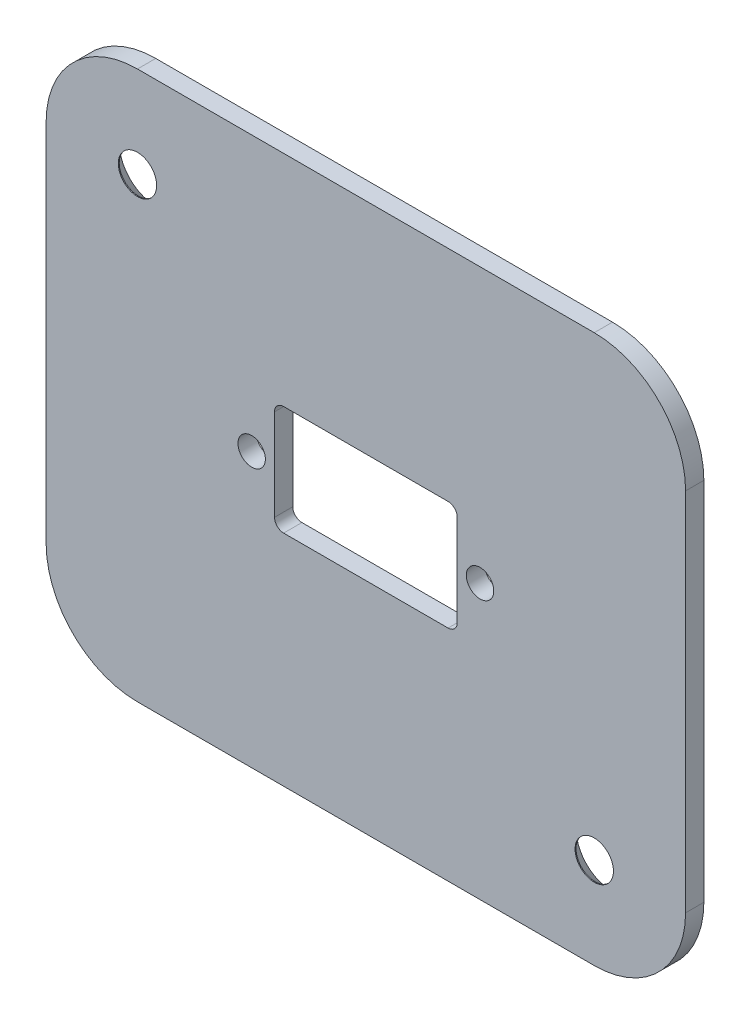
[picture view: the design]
ISO-10303-21;
HEADER;
FILE_DESCRIPTION(('STEP AP214'),'2;1');
FILE_NAME('part.step','',(''),(''),'','','');
FILE_SCHEMA(('AUTOMOTIVE_DESIGN { 1 0 10303 214 1 1 1 1 }'));
ENDSEC;
DATA;
#1=APPLICATION_CONTEXT('core data for automotive mechanical design processes');
#2=APPLICATION_PROTOCOL_DEFINITION('international standard','automotive_design',2000,#1);
#3=PRODUCT_CONTEXT('',#1,'mechanical');
#4=PRODUCT('Part','Part','',(#3));
#5=PRODUCT_RELATED_PRODUCT_CATEGORY('part','',(#4));
#6=PRODUCT_DEFINITION_FORMATION('','',#4);
#7=PRODUCT_DEFINITION_CONTEXT('part definition',#1,'design');
#8=PRODUCT_DEFINITION('design','',#6,#7);
#9=PRODUCT_DEFINITION_SHAPE('','',#8);
#10=(LENGTH_UNIT() NAMED_UNIT(*) SI_UNIT(.MILLI.,.METRE.));
#11=(NAMED_UNIT(*) PLANE_ANGLE_UNIT() SI_UNIT($,.RADIAN.));
#12=(NAMED_UNIT(*) SI_UNIT($,.STERADIAN.) SOLID_ANGLE_UNIT());
#13=UNCERTAINTY_MEASURE_WITH_UNIT(LENGTH_MEASURE(1.E-05),#10,'distance_accuracy_value','');
#14=(GEOMETRIC_REPRESENTATION_CONTEXT(3) GLOBAL_UNCERTAINTY_ASSIGNED_CONTEXT((#13)) GLOBAL_UNIT_ASSIGNED_CONTEXT((#10,
#11,#12)) REPRESENTATION_CONTEXT('',''));
#15=CARTESIAN_POINT('',(0.,0.,0.));
#16=DIRECTION('',(0.,0.,1.));
#17=DIRECTION('',(1.,0.,0.));
#18=AXIS2_PLACEMENT_3D('',#15,#16,#17);
#19=CARTESIAN_POINT('',(0.,0.,-2.));
#20=DIRECTION('',(0.,0.,-1.));
#21=DIRECTION('',(-1.,0.,0.));
#22=AXIS2_PLACEMENT_3D('',#19,#20,#21);
#23=PLANE('',#22);
#24=DIRECTION('',(1.,0.,0.));
#25=VECTOR('',#24,1.);
#26=CARTESIAN_POINT('',(33.2901806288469,15.781993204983,-2.));
#27=LINE('',#26,#25);
#28=CARTESIAN_POINT('',(33.2901806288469,15.781993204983,-2.));
#29=VERTEX_POINT('',#28);
#30=CARTESIAN_POINT('',(33.3350524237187,15.781993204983,-2.));
#31=VERTEX_POINT('',#30);
#32=EDGE_CURVE('E444',#29,#31,#27,.T.);
#33=ORIENTED_EDGE('',*,*,#32,.T.);
#34=DIRECTION('',(0.389639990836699,0.920967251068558,0.));
#35=VECTOR('',#34,1.);
#36=CARTESIAN_POINT('',(33.3350524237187,15.781993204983,-2.));
#37=LINE('',#36,#35);
#38=CARTESIAN_POINT('',(34.8158216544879,19.281993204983,-2.));
#39=VERTEX_POINT('',#38);
#40=EDGE_CURVE('E55',#31,#39,#37,.T.);
#41=ORIENTED_EDGE('',*,*,#40,.T.);
#42=DIRECTION('',(-1.,0.,0.));
#43=VECTOR('',#42,1.);
#44=CARTESIAN_POINT('',(34.8158216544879,19.281993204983,-2.));
#45=LINE('',#44,#43);
#46=CARTESIAN_POINT('',(34.4792831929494,19.281993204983,-2.));
#47=VERTEX_POINT('',#46);
#48=EDGE_CURVE('E434',#39,#47,#45,.T.);
#49=ORIENTED_EDGE('',*,*,#48,.T.);
#50=DIRECTION('',(-0.389563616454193,-0.920999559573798,0.));
#51=VECTOR('',#50,1.);
#52=CARTESIAN_POINT('',(34.4792831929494,19.281993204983,-2.));
#53=LINE('',#52,#51);
#54=CARTESIAN_POINT('',(33.3126165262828,16.5237800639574,-2.));
#55=VERTEX_POINT('',#54);
#56=EDGE_CURVE('E459',#47,#55,#53,.T.);
#57=ORIENTED_EDGE('',*,*,#56,.T.);
#58=DIRECTION('',(-0.389563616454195,0.920999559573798,0.));
#59=VECTOR('',#58,1.);
#60=CARTESIAN_POINT('',(33.3126165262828,16.5237800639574,-2.));
#61=LINE('',#60,#59);
#62=CARTESIAN_POINT('',(32.1459498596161,19.281993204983,-2.));
#63=VERTEX_POINT('',#62);
#64=EDGE_CURVE('E462',#55,#63,#61,.T.);
#65=ORIENTED_EDGE('',*,*,#64,.T.);
#66=DIRECTION('',(-1.,0.,0.));
#67=VECTOR('',#66,1.);
#68=CARTESIAN_POINT('',(32.1459498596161,19.281993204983,-2.));
#69=LINE('',#68,#67);
#70=CARTESIAN_POINT('',(31.8094113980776,19.281993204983,-2.));
#71=VERTEX_POINT('',#70);
#72=EDGE_CURVE('E465',#63,#71,#69,.T.);
#73=ORIENTED_EDGE('',*,*,#72,.T.);
#74=DIRECTION('',(0.389639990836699,-0.920967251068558,0.));
#75=VECTOR('',#74,1.);
#76=CARTESIAN_POINT('',(31.8094113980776,19.281993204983,-2.));
#77=LINE('',#76,#75);
#78=EDGE_CURVE('E468',#71,#29,#77,.T.);
#79=ORIENTED_EDGE('',*,*,#78,.T.);
#80=EDGE_LOOP('',(#33,#41,#49,#57,#65,#73,#79));
#81=FACE_BOUND('',#80,.T.);
#82=DIRECTION('',(-0.200944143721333,0.97960270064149,0.));
#83=VECTOR('',#82,1.);
#84=CARTESIAN_POINT('',(41.1876165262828,17.531993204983,-2.));
#85=LINE('',#84,#83);
#86=CARTESIAN_POINT('',(41.1876165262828,17.531993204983,-2.));
#87=VERTEX_POINT('',#86);
#88=CARTESIAN_POINT('',(40.8286421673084,19.281993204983,-2.));
#89=VERTEX_POINT('',#88);
#90=EDGE_CURVE('E610',#87,#89,#85,.T.);
#91=ORIENTED_EDGE('',*,*,#90,.T.);
#92=DIRECTION('',(-1.,0.,0.));
#93=VECTOR('',#92,1.);
#94=CARTESIAN_POINT('',(40.8286421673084,19.281993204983,-2.));
#95=LINE('',#94,#93);
#96=CARTESIAN_POINT('',(39.392744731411,19.281993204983,-2.));
#97=VERTEX_POINT('',#96);
#98=EDGE_CURVE('E605',#89,#97,#95,.T.);
#99=ORIENTED_EDGE('',*,*,#98,.T.);
#100=DIRECTION('',(0.,-1.,0.));
#101=VECTOR('',#100,1.);
#102=CARTESIAN_POINT('',(39.392744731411,19.281993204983,-2.));
#103=LINE('',#102,#101);
#104=CARTESIAN_POINT('',(39.392744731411,18.9230188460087,-2.));
#105=VERTEX_POINT('',#104);
#106=EDGE_CURVE('E1007',#97,#105,#103,.T.);
#107=ORIENTED_EDGE('',*,*,#106,.T.);
#108=DIRECTION('',(1.,0.,0.));
#109=VECTOR('',#108,1.);
#110=CARTESIAN_POINT('',(39.392744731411,18.9230188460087,-2.));
#111=LINE('',#110,#109);
#112=CARTESIAN_POINT('',(40.5832495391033,18.9230188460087,-2.));
#113=VERTEX_POINT('',#112);
#114=EDGE_CURVE('E1004',#105,#113,#111,.T.);
#115=ORIENTED_EDGE('',*,*,#114,.T.);
#116=DIRECTION('',(0.20070547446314,-0.979651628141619,0.));
#117=VECTOR('',#116,1.);
#118=CARTESIAN_POINT('',(40.5832495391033,18.9230188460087,-2.));
#119=LINE('',#118,#117);
#120=CARTESIAN_POINT('',(40.7718513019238,18.002445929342,-2.));
#121=VERTEX_POINT('',#120);
#122=EDGE_CURVE('E998',#113,#121,#119,.T.);
#123=ORIENTED_EDGE('',*,*,#122,.T.);
#124=CARTESIAN_POINT('',(40.7718513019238,18.002445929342,-2.));
#125=CARTESIAN_POINT('',(40.7347954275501,18.0126762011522,-2.));
#126=CARTESIAN_POINT('',(40.6630055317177,18.0324957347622,-2.));
#127=CARTESIAN_POINT('',(40.557045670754,18.0545015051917,-2.));
#128=CARTESIAN_POINT('',(40.456453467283,18.0677669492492,-2.));
#129=CARTESIAN_POINT('',(40.3911780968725,18.0695782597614,-2.));
#130=CARTESIAN_POINT('',(40.3595916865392,18.0704547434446,-2.));
#131=B_SPLINE_CURVE_WITH_KNOTS('',3,(#124,#125,#126,#127,#128,#129,#130),.UNSPECIFIED.,.F.,.F.,
(4,1,1,1,4),(0.,0.275068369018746,0.532901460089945,0.773973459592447,1.),.UNSPECIFIED.);
#132=CARTESIAN_POINT('',(40.3595916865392,18.0704547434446,-2.));
#133=VERTEX_POINT('',#132);
#134=EDGE_CURVE('E990',#121,#133,#131,.T.);
#135=ORIENTED_EDGE('',*,*,#134,.T.);
#136=CARTESIAN_POINT('',(40.3595916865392,18.0704547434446,-2.));
#137=CARTESIAN_POINT('',(40.320507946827,18.0696088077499,-2.));
#138=CARTESIAN_POINT('',(40.2436595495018,18.0679454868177,-2.));
#139=CARTESIAN_POINT('',(40.1312206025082,18.0519736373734,-2.));
#140=CARTESIAN_POINT('',(40.0238877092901,18.0268337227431,-2.));
#141=CARTESIAN_POINT('',(39.9218853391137,17.9917132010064,-2.));
#142=CARTESIAN_POINT('',(39.8250247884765,17.9468034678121,-2.));
#143=CARTESIAN_POINT('',(39.7341972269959,17.8907035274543,-2.));
#144=CARTESIAN_POINT('',(39.6480393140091,17.8251701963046,-2.));
#145=CARTESIAN_POINT('',(39.5680967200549,17.749825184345,-2.));
#146=CARTESIAN_POINT('',(39.4955724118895,17.6669035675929,-2.));
#147=CARTESIAN_POINT('',(39.4318064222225,17.5777456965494,-2.));
#148=CARTESIAN_POINT('',(39.3776438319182,17.4832180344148,-2.));
#149=CARTESIAN_POINT('',(39.3340830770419,17.3824174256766,-2.));
#150=CARTESIAN_POINT('',(39.2992987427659,17.2764582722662,-2.));
#151=CARTESIAN_POINT('',(39.2761467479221,17.164225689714,-2.));
#152=CARTESIAN_POINT('',(39.2607300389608,17.0467775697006,-2.));
#153=CARTESIAN_POINT('',(39.2590076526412,16.9664729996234,-2.));
#154=CARTESIAN_POINT('',(39.2581293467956,16.9255228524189,-2.));
#155=B_SPLINE_CURVE_WITH_KNOTS('',3,(#136,#137,#138,#139,#140,#141,#142,#143,#144,#145,#146,
#147,#148,#149,#150,#151,#152,#153,#154),.UNSPECIFIED.,.F.,.F.,(4,1,1,1,1,1,1,1,1,1,1,1,1,1,1,1,
4),(0.,0.0658076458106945,0.129394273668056,0.190894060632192,0.251281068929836,
0.310814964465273,0.370370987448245,0.430768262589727,0.492881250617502,0.555103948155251,
0.616067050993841,0.677256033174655,0.738259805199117,0.800762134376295,0.864777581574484,
0.931045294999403,1.),.UNSPECIFIED.);
#156=CARTESIAN_POINT('',(39.2581293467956,16.9255228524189,-2.));
#157=VERTEX_POINT('',#156);
#158=EDGE_CURVE('E982',#133,#157,#155,.T.);
#159=ORIENTED_EDGE('',*,*,#158,.T.);
#160=CARTESIAN_POINT('',(39.2581293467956,16.9255228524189,-2.));
#161=CARTESIAN_POINT('',(39.2587944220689,16.897000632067,-2.));
#162=CARTESIAN_POINT('',(39.2601155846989,16.8403416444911,-2.));
#163=CARTESIAN_POINT('',(39.2668341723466,16.7561974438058,-2.));
#164=CARTESIAN_POINT('',(39.2797698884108,16.6738346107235,-2.));
#165=CARTESIAN_POINT('',(39.2971376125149,16.5932422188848,-2.));
#166=CARTESIAN_POINT('',(39.3196800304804,16.5145728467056,-2.));
#167=CARTESIAN_POINT('',(39.3469690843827,16.4376013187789,-2.));
#168=CARTESIAN_POINT('',(39.3803651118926,16.3628067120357,-2.));
#169=CARTESIAN_POINT('',(39.4169964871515,16.2894813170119,-2.));
#170=CARTESIAN_POINT('',(39.4582429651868,16.2192828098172,-2.));
#171=CARTESIAN_POINT('',(39.5040214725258,16.1536338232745,-2.));
#172=CARTESIAN_POINT('',(39.5523869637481,16.0915495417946,-2.));
#173=CARTESIAN_POINT('',(39.6044283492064,16.0336958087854,-2.));
#174=CARTESIAN_POINT('',(39.660629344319,15.9804527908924,-2.));
#175=CARTESIAN_POINT('',(39.7203093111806,15.9315045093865,-2.));
#176=CARTESIAN_POINT('',(39.7829920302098,15.8860231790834,-2.));
#177=CARTESIAN_POINT('',(39.8496472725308,15.8458549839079,-2.));
#178=CARTESIAN_POINT('',(39.9187897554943,15.8088920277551,-2.));
#179=CARTESIAN_POINT('',(39.9914179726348,15.7785684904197,-2.));
#180=CARTESIAN_POINT('',(40.0658786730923,15.7514579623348,-2.));
#181=CARTESIAN_POINT('',(40.1432435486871,15.7298484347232,-2.));
#182=CARTESIAN_POINT('',(40.2233373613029,15.7129158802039,-2.));
#183=CARTESIAN_POINT('',(40.306292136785,15.7014152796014,-2.));
#184=CARTESIAN_POINT('',(40.3916728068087,15.6930388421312,-2.));
#185=CARTESIAN_POINT('',(40.4495478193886,15.6925144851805,-2.));
#186=CARTESIAN_POINT('',(40.4787823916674,15.6922496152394,-2.));
#187=B_SPLINE_CURVE_WITH_KNOTS('',3,(#160,#161,#162,#163,#164,#165,#166,#167,#168,#169,#170,
#171,#172,#173,#174,#175,#176,#177,#178,#179,#180,#181,#182,#183,#184,#185,#186),.UNSPECIFIED.,
.F.,.F.,(4,1,1,1,1,1,1,1,1,1,1,1,1,1,1,1,1,1,1,1,1,1,1,1,4),(0.,0.0440144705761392,
0.0874341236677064,0.130118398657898,0.172553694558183,0.21455475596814,0.256298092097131,
0.29843822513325,0.340849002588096,0.382715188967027,0.423924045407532,0.464246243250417,
0.504073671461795,0.543861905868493,0.583566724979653,0.623094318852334,0.663229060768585,
0.703551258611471,0.743937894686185,0.784541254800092,0.825750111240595,0.867757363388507,
0.910745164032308,0.954914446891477,1.),.UNSPECIFIED.);
#188=CARTESIAN_POINT('',(40.4787823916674,15.6922496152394,-2.));
#189=VERTEX_POINT('',#188);
#190=EDGE_CURVE('E974',#157,#189,#187,.T.);
#191=ORIENTED_EDGE('',*,*,#190,.T.);
#192=CARTESIAN_POINT('',(40.4787823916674,15.6922496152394,-2.));
#193=CARTESIAN_POINT('',(40.5136565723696,15.6929404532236,-2.));
#194=CARTESIAN_POINT('',(40.5822674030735,15.694299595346,-2.));
#195=CARTESIAN_POINT('',(40.682787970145,15.7085180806,-2.));
#196=CARTESIAN_POINT('',(40.7795025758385,15.7288819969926,-2.));
#197=CARTESIAN_POINT('',(40.8716326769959,15.7595182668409,-2.));
#198=CARTESIAN_POINT('',(40.9600039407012,15.7979055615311,-2.));
#199=CARTESIAN_POINT('',(41.04342665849,15.8464217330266,-2.));
#200=CARTESIAN_POINT('',(41.1240324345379,15.9014008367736,-2.));
#201=CARTESIAN_POINT('',(41.1985444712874,15.9662811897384,-2.));
#202=CARTESIAN_POINT('',(41.267700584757,16.0371968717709,-2.));
#203=CARTESIAN_POINT('',(41.3296070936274,16.1141545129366,-2.));
#204=CARTESIAN_POINT('',(41.384740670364,16.1958839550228,-2.));
#205=CARTESIAN_POINT('',(41.4322184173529,16.2827821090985,-2.));
#206=CARTESIAN_POINT('',(41.4727164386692,16.3746206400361,-2.));
#207=CARTESIAN_POINT('',(41.504531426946,16.4717436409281,-2.));
#208=CARTESIAN_POINT('',(41.5302097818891,16.5736436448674,-2.));
#209=CARTESIAN_POINT('',(41.5410732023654,16.643797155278,-2.));
#210=CARTESIAN_POINT('',(41.5465908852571,16.6794291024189,-2.));
#211=B_SPLINE_CURVE_WITH_KNOTS('',3,(#192,#193,#194,#195,#196,#197,#198,#199,#200,#201,#202,
#203,#204,#205,#206,#207,#208,#209,#210),.UNSPECIFIED.,.F.,.F.,(4,1,1,1,1,1,1,1,1,1,1,1,1,1,1,1,
4),(0.,0.0654211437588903,0.128708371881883,0.190236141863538,0.250724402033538,
0.310637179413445,0.370766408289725,0.431614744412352,0.493522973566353,0.555883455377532,
0.61734236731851,0.678668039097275,0.740711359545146,0.802985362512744,0.866802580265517,
0.932347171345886,1.),.UNSPECIFIED.);
#212=CARTESIAN_POINT('',(41.5465908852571,16.6794291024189,-2.));
#213=VERTEX_POINT('',#212);
#214=EDGE_CURVE('E969',#189,#213,#211,.T.);
#215=ORIENTED_EDGE('',*,*,#214,.T.);
#216=DIRECTION('',(-1.,0.,0.));
#217=VECTOR('',#216,1.);
#218=CARTESIAN_POINT('',(41.5465908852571,16.6794291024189,-2.));
#219=LINE('',#218,#217);
#220=CARTESIAN_POINT('',(41.2324883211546,16.6794291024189,-2.));
#221=VERTEX_POINT('',#220);
#222=EDGE_CURVE('E963',#213,#221,#219,.T.);
#223=ORIENTED_EDGE('',*,*,#222,.T.);
#224=CARTESIAN_POINT('',(41.2324883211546,16.6794291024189,-2.));
#225=CARTESIAN_POINT('',(41.2247597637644,16.6460526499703,-2.));
#226=CARTESIAN_POINT('',(41.2099050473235,16.5819012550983,-2.));
#227=CARTESIAN_POINT('',(41.1772992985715,16.4917699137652,-2.));
#228=CARTESIAN_POINT('',(41.1374334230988,16.4114506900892,-2.));
#229=CARTESIAN_POINT('',(41.0900290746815,16.3398811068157,-2.));
#230=CARTESIAN_POINT('',(41.0334790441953,16.2774721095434,-2.));
#231=CARTESIAN_POINT('',(40.9689496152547,16.2218550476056,-2.));
#232=CARTESIAN_POINT('',(40.8966018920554,16.1716799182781,-2.));
#233=CARTESIAN_POINT('',(40.8162086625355,16.1298571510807,-2.));
#234=CARTESIAN_POINT('',(40.7313955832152,16.0941883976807,-2.));
#235=CARTESIAN_POINT('',(40.6426283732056,16.0704367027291,-2.));
#236=CARTESIAN_POINT('',(40.5523240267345,16.0537358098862,-2.));
#237=CARTESIAN_POINT('',(40.491245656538,16.0520640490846,-2.));
#238=CARTESIAN_POINT('',(40.4605532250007,16.0512239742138,-2.));
#239=B_SPLINE_CURVE_WITH_KNOTS('',3,(#224,#225,#226,#227,#228,#229,#230,#231,#232,#233,#234,
#235,#236,#237,#238),.UNSPECIFIED.,.F.,.F.,(4,1,1,1,1,1,1,1,1,1,1,1,4),(0.,0.0946872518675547,
0.181994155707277,0.264376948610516,0.342179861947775,0.418617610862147,0.496509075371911,
0.577369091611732,0.661510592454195,0.746732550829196,0.831257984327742,0.915205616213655,1.),.UNSPECIFIED.);
#240=CARTESIAN_POINT('',(40.4605532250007,16.0512239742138,-2.));
#241=VERTEX_POINT('',#240);
#242=EDGE_CURVE('E955',#221,#241,#239,.T.);
#243=ORIENTED_EDGE('',*,*,#242,.T.);
#244=CARTESIAN_POINT('',(40.4605532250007,16.0512239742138,-2.));
#245=CARTESIAN_POINT('',(40.4305947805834,16.0520447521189,-2.));
#246=CARTESIAN_POINT('',(40.3716063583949,16.05366087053,-2.));
#247=CARTESIAN_POINT('',(40.2847949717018,16.0660998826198,-2.));
#248=CARTESIAN_POINT('',(40.2009820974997,16.0852574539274,-2.));
#249=CARTESIAN_POINT('',(40.1209947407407,16.1139273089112,-2.));
#250=CARTESIAN_POINT('',(40.0434332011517,16.148772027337,-2.));
#251=CARTESIAN_POINT('',(39.9702594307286,16.1934871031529,-2.));
#252=CARTESIAN_POINT('',(39.8993565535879,16.2449471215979,-2.));
#253=CARTESIAN_POINT('',(39.8329284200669,16.3039037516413,-2.));
#254=CARTESIAN_POINT('',(39.7720889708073,16.3688734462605,-2.));
#255=CARTESIAN_POINT('',(39.7183328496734,16.4383508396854,-2.));
#256=CARTESIAN_POINT('',(39.6735559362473,16.5124676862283,-2.));
#257=CARTESIAN_POINT('',(39.6358218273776,16.5899408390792,-2.));
#258=CARTESIAN_POINT('',(39.6071685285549,16.6716193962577,-2.));
#259=CARTESIAN_POINT('',(39.5867275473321,16.7571205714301,-2.));
#260=CARTESIAN_POINT('',(39.5747244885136,16.8466555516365,-2.));
#261=CARTESIAN_POINT('',(39.5730733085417,16.9077248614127,-2.));
#262=CARTESIAN_POINT('',(39.5722319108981,16.9388441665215,-2.));
#263=B_SPLINE_CURVE_WITH_KNOTS('',3,(#244,#245,#246,#247,#248,#249,#250,#251,#252,#253,#254,
#255,#256,#257,#258,#259,#260,#261,#262),.UNSPECIFIED.,.F.,.F.,(4,1,1,1,1,1,1,1,1,1,1,1,1,1,1,1,
4),(0.,0.0642072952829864,0.12642468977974,0.187680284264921,0.248216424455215,
0.308305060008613,0.369660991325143,0.43169855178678,0.495946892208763,0.559758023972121,
0.622295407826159,0.683910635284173,0.745092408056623,0.806740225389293,0.869086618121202,
0.9332900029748,1.),.UNSPECIFIED.);
#264=CARTESIAN_POINT('',(39.5722319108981,16.9388441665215,-2.));
#265=VERTEX_POINT('',#264);
#266=EDGE_CURVE('E947',#241,#265,#263,.T.);
#267=ORIENTED_EDGE('',*,*,#266,.T.);
#268=CARTESIAN_POINT('',(39.5722319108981,16.9388441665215,-2.));
#269=CARTESIAN_POINT('',(39.5728903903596,16.9669199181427,-2.));
#270=CARTESIAN_POINT('',(39.574179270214,17.0218742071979,-2.));
#271=CARTESIAN_POINT('',(39.5847098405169,17.1022734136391,-2.));
#272=CARTESIAN_POINT('',(39.6030268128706,17.1783464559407,-2.));
#273=CARTESIAN_POINT('',(39.6284506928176,17.2504606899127,-2.));
#274=CARTESIAN_POINT('',(39.6607302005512,17.3186841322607,-2.));
#275=CARTESIAN_POINT('',(39.70017651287,17.3830871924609,-2.));
#276=CARTESIAN_POINT('',(39.7475299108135,17.4428210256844,-2.));
#277=CARTESIAN_POINT('',(39.8016217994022,17.4979135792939,-2.));
#278=CARTESIAN_POINT('',(39.8608798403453,17.548758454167,-2.));
#279=CARTESIAN_POINT('',(39.9263235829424,17.5921025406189,-2.));
#280=CARTESIAN_POINT('',(39.9965835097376,17.6285664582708,-2.));
#281=CARTESIAN_POINT('',(40.0708131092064,17.6600344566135,-2.));
#282=CARTESIAN_POINT('',(40.1507780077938,17.6826352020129,-2.));
#283=CARTESIAN_POINT('',(40.2348946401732,17.699603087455,-2.));
#284=CARTESIAN_POINT('',(40.3240713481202,17.7094184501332,-2.));
#285=CARTESIAN_POINT('',(40.3850420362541,17.710780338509,-2.));
#286=CARTESIAN_POINT('',(40.4163825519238,17.7114803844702,-2.));
#287=B_SPLINE_CURVE_WITH_KNOTS('',3,(#268,#269,#270,#271,#272,#273,#274,#275,#276,#277,#278,
#279,#280,#281,#282,#283,#284,#285,#286),.UNSPECIFIED.,.F.,.F.,(4,1,1,1,1,1,1,1,1,1,1,1,1,1,1,1,
4),(0.,0.0653513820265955,0.127916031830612,0.1883602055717,0.247216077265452,0.305630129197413,
0.36376983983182,0.42266091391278,0.482687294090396,0.543300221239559,0.604117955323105,
0.664964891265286,0.727413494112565,0.791467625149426,0.858055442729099,0.927036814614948,1.),.UNSPECIFIED.);
#288=CARTESIAN_POINT('',(40.4163825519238,17.7114803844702,-2.));
#289=VERTEX_POINT('',#288);
#290=EDGE_CURVE('E939',#265,#289,#287,.T.);
#291=ORIENTED_EDGE('',*,*,#290,.T.);
#292=CARTESIAN_POINT('',(40.4163825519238,17.7114803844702,-2.));
#293=CARTESIAN_POINT('',(40.4435114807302,17.7108997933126,-2.));
#294=CARTESIAN_POINT('',(40.4995258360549,17.7097010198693,-2.));
#295=CARTESIAN_POINT('',(40.5854486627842,17.7008745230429,-2.));
#296=CARTESIAN_POINT('',(40.6757403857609,17.6866352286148,-2.));
#297=CARTESIAN_POINT('',(40.7700548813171,17.6670489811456,-2.));
#298=CARTESIAN_POINT('',(40.8686753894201,17.641417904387,-2.));
#299=CARTESIAN_POINT('',(40.9713937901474,17.6107034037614,-2.));
#300=CARTESIAN_POINT('',(41.0784260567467,17.5739814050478,-2.));
#301=CARTESIAN_POINT('',(41.1505437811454,17.5462491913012,-2.));
#302=CARTESIAN_POINT('',(41.1876165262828,17.531993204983,-2.));
#303=B_SPLINE_CURVE_WITH_KNOTS('',3,(#292,#293,#294,#295,#296,#297,#298,#299,#300,#301,#302),
.UNSPECIFIED.,.F.,.F.,(4,1,1,1,1,1,1,1,4),(0.,0.102203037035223,0.211023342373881,
0.325099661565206,0.446502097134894,0.573787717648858,0.708900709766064,0.850357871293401,1.),.UNSPECIFIED.);
#304=EDGE_CURVE('E934',#289,#87,#303,.T.);
#305=ORIENTED_EDGE('',*,*,#304,.T.);
#306=EDGE_LOOP('',(#91,#99,#107,#115,#123,#135,#159,#191,#215,#223,#243,#267,#291,#305));
#307=FACE_BOUND('',#306,.T.);
#308=CARTESIAN_POINT('',(44.,25.,-2.));
#309=DIRECTION('',(0.,0.,-1.));
#310=DIRECTION('',(-1.,0.,0.));
#311=AXIS2_PLACEMENT_3D('',#308,#309,#310);
#312=CIRCLE('',#311,1.);
#313=CARTESIAN_POINT('',(45.,25.,-2.));
#314=VERTEX_POINT('',#313);
#315=CARTESIAN_POINT('',(44.,24.,-2.));
#316=VERTEX_POINT('',#315);
#317=EDGE_CURVE('E877',#314,#316,#312,.T.);
#318=ORIENTED_EDGE('',*,*,#317,.F.);
#319=DIRECTION('',(0.,-1.,0.));
#320=VECTOR('',#319,1.);
#321=CARTESIAN_POINT('',(45.,35.,-2.));
#322=LINE('',#321,#320);
#323=CARTESIAN_POINT('',(45.,35.,-2.));
#324=VERTEX_POINT('',#323);
#325=EDGE_CURVE('E855',#324,#314,#322,.T.);
#326=ORIENTED_EDGE('',*,*,#325,.F.);
#327=CARTESIAN_POINT('',(44.,35.,-2.));
#328=DIRECTION('',(0.,0.,-1.));
#329=DIRECTION('',(-1.,0.,0.));
#330=AXIS2_PLACEMENT_3D('',#327,#328,#329);
#331=CIRCLE('',#330,1.);
#332=CARTESIAN_POINT('',(44.,36.,-2.));
#333=VERTEX_POINT('',#332);
#334=EDGE_CURVE('E859',#333,#324,#331,.T.);
#335=ORIENTED_EDGE('',*,*,#334,.F.);
#336=DIRECTION('',(1.,0.,0.));
#337=VECTOR('',#336,1.);
#338=CARTESIAN_POINT('',(44.,36.,-2.));
#339=LINE('',#338,#337);
#340=CARTESIAN_POINT('',(26.,36.,-2.));
#341=VERTEX_POINT('',#340);
#342=EDGE_CURVE('E862',#341,#333,#339,.T.);
#343=ORIENTED_EDGE('',*,*,#342,.F.);
#344=CARTESIAN_POINT('',(26.,35.,-2.));
#345=DIRECTION('',(0.,0.,-1.));
#346=DIRECTION('',(-1.,0.,0.));
#347=AXIS2_PLACEMENT_3D('',#344,#345,#346);
#348=CIRCLE('',#347,1.);
#349=CARTESIAN_POINT('',(25.,35.,-2.));
#350=VERTEX_POINT('',#349);
#351=EDGE_CURVE('E865',#350,#341,#348,.T.);
#352=ORIENTED_EDGE('',*,*,#351,.F.);
#353=DIRECTION('',(0.,1.,0.));
#354=VECTOR('',#353,1.);
#355=CARTESIAN_POINT('',(25.,35.,-2.));
#356=LINE('',#355,#354);
#357=CARTESIAN_POINT('',(25.,25.,-2.));
#358=VERTEX_POINT('',#357);
#359=EDGE_CURVE('E868',#358,#350,#356,.T.);
#360=ORIENTED_EDGE('',*,*,#359,.F.);
#361=CARTESIAN_POINT('',(26.,25.,-2.));
#362=DIRECTION('',(0.,0.,-1.));
#363=DIRECTION('',(-1.,0.,0.));
#364=AXIS2_PLACEMENT_3D('',#361,#362,#363);
#365=CIRCLE('',#364,1.);
#366=CARTESIAN_POINT('',(26.,24.,-2.));
#367=VERTEX_POINT('',#366);
#368=EDGE_CURVE('E871',#367,#358,#365,.T.);
#369=ORIENTED_EDGE('',*,*,#368,.F.);
#370=DIRECTION('',(-1.,0.,0.));
#371=VECTOR('',#370,1.);
#372=CARTESIAN_POINT('',(44.,24.,-2.));
#373=LINE('',#372,#371);
#374=EDGE_CURVE('E874',#316,#367,#373,.T.);
#375=ORIENTED_EDGE('',*,*,#374,.F.);
#376=EDGE_LOOP('',(#318,#326,#335,#343,#352,#360,#369,#375));
#377=FACE_BOUND('',#376,.T.);
#378=CARTESIAN_POINT('',(22.5,30.,-2.));
#379=DIRECTION('',(0.,0.,-1.));
#380=DIRECTION('',(-1.,0.,0.));
#381=AXIS2_PLACEMENT_3D('',#378,#379,#380);
#382=CIRCLE('',#381,1.5);
#383=CARTESIAN_POINT('',(21.,30.,-2.));
#384=VERTEX_POINT('',#383);
#385=EDGE_CURVE('E832',#384,#384,#382,.T.);
#386=ORIENTED_EDGE('',*,*,#385,.F.);
#387=EDGE_LOOP('',(#386));
#388=FACE_BOUND('',#387,.T.);
#389=CARTESIAN_POINT('',(47.5,30.,-2.));
#390=DIRECTION('',(0.,0.,-1.));
#391=DIRECTION('',(-1.,0.,0.));
#392=AXIS2_PLACEMENT_3D('',#389,#390,#391);
#393=CIRCLE('',#392,1.5);
#394=CARTESIAN_POINT('',(46.,30.,-2.));
#395=VERTEX_POINT('',#394);
#396=EDGE_CURVE('E826',#395,#395,#393,.T.);
#397=ORIENTED_EDGE('',*,*,#396,.F.);
#398=EDGE_LOOP('',(#397));
#399=FACE_BOUND('',#398,.T.);
#400=CARTESIAN_POINT('',(10.,50.,-2.));
#401=DIRECTION('',(0.,0.,-1.));
#402=DIRECTION('',(-1.,0.,0.));
#403=AXIS2_PLACEMENT_3D('',#400,#401,#402);
#404=CIRCLE('',#403,4.);
#405=CARTESIAN_POINT('',(6.,50.,-2.));
#406=VERTEX_POINT('',#405);
#407=EDGE_CURVE('E752',#406,#406,#404,.F.);
#408=ORIENTED_EDGE('',*,*,#407,.T.);
#409=EDGE_LOOP('',(#408));
#410=FACE_BOUND('',#409,.T.);
#411=CARTESIAN_POINT('',(60.,10.,-2.));
#412=DIRECTION('',(0.,0.,-1.));
#413=DIRECTION('',(-1.,0.,0.));
#414=AXIS2_PLACEMENT_3D('',#411,#412,#413);
#415=CIRCLE('',#414,4.);
#416=CARTESIAN_POINT('',(56.,10.,-2.));
#417=VERTEX_POINT('',#416);
#418=EDGE_CURVE('E754',#417,#417,#415,.F.);
#419=ORIENTED_EDGE('',*,*,#418,.T.);
#420=EDGE_LOOP('',(#419));
#421=FACE_BOUND('',#420,.T.);
#422=DIRECTION('',(0.,1.,0.));
#423=VECTOR('',#422,1.);
#424=CARTESIAN_POINT('',(70.,0.,-2.));
#425=LINE('',#424,#423);
#426=CARTESIAN_POINT('',(70.,10.,-2.));
#427=VERTEX_POINT('',#426);
#428=CARTESIAN_POINT('',(70.,50.,-2.));
#429=VERTEX_POINT('',#428);
#430=EDGE_CURVE('E812',#427,#429,#425,.T.);
#431=ORIENTED_EDGE('',*,*,#430,.F.);
#432=CARTESIAN_POINT('',(60.,10.,-2.));
#433=DIRECTION('',(0.,0.,-1.));
#434=DIRECTION('',(-1.,0.,0.));
#435=AXIS2_PLACEMENT_3D('',#432,#433,#434);
#436=CIRCLE('',#435,10.);
#437=CARTESIAN_POINT('',(60.,0.,-2.));
#438=VERTEX_POINT('',#437);
#439=EDGE_CURVE('E769',#427,#438,#436,.T.);
#440=ORIENTED_EDGE('',*,*,#439,.T.);
#441=DIRECTION('',(1.,0.,0.));
#442=VECTOR('',#441,1.);
#443=CARTESIAN_POINT('',(0.,0.,-2.));
#444=LINE('',#443,#442);
#445=CARTESIAN_POINT('',(10.,0.,-2.));
#446=VERTEX_POINT('',#445);
#447=EDGE_CURVE('E815',#446,#438,#444,.T.);
#448=ORIENTED_EDGE('',*,*,#447,.F.);
#449=CARTESIAN_POINT('',(10.,10.,-2.));
#450=DIRECTION('',(0.,0.,-1.));
#451=DIRECTION('',(-1.,0.,0.));
#452=AXIS2_PLACEMENT_3D('',#449,#450,#451);
#453=CIRCLE('',#452,10.);
#454=CARTESIAN_POINT('',(0.,10.,-2.));
#455=VERTEX_POINT('',#454);
#456=EDGE_CURVE('E771',#446,#455,#453,.T.);
#457=ORIENTED_EDGE('',*,*,#456,.T.);
#458=DIRECTION('',(0.,-1.,0.));
#459=VECTOR('',#458,1.);
#460=CARTESIAN_POINT('',(0.,0.,-2.));
#461=LINE('',#460,#459);
#462=CARTESIAN_POINT('',(0.,50.,-2.));
#463=VERTEX_POINT('',#462);
#464=EDGE_CURVE('E799',#463,#455,#461,.T.);
#465=ORIENTED_EDGE('',*,*,#464,.F.);
#466=CARTESIAN_POINT('',(10.,50.,-2.));
#467=DIRECTION('',(0.,0.,-1.));
#468=DIRECTION('',(-1.,0.,0.));
#469=AXIS2_PLACEMENT_3D('',#466,#467,#468);
#470=CIRCLE('',#469,10.);
#471=CARTESIAN_POINT('',(10.,60.,-2.));
#472=VERTEX_POINT('',#471);
#473=EDGE_CURVE('E773',#463,#472,#470,.T.);
#474=ORIENTED_EDGE('',*,*,#473,.T.);
#475=DIRECTION('',(-1.,0.,0.));
#476=VECTOR('',#475,1.);
#477=CARTESIAN_POINT('',(0.,60.,-2.));
#478=LINE('',#477,#476);
#479=CARTESIAN_POINT('',(60.,60.,-2.));
#480=VERTEX_POINT('',#479);
#481=EDGE_CURVE('E795',#480,#472,#478,.T.);
#482=ORIENTED_EDGE('',*,*,#481,.F.);
#483=CARTESIAN_POINT('',(60.,50.,-2.));
#484=DIRECTION('',(0.,0.,-1.));
#485=DIRECTION('',(-1.,0.,0.));
#486=AXIS2_PLACEMENT_3D('',#483,#484,#485);
#487=CIRCLE('',#486,10.);
#488=EDGE_CURVE('E775',#480,#429,#487,.T.);
#489=ORIENTED_EDGE('',*,*,#488,.T.);
#490=EDGE_LOOP('',(#431,#440,#448,#457,#465,#474,#482,#489));
#491=FACE_BOUND('',#490,.T.);
#492=CARTESIAN_POINT('',(36.6555652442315,18.2962159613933,-2.));
#493=CARTESIAN_POINT('',(36.6567436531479,18.2594721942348,-2.));
#494=CARTESIAN_POINT('',(36.65913376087,18.1849466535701,-2.));
#495=CARTESIAN_POINT('',(36.6758700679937,18.0717163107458,-2.));
#496=CARTESIAN_POINT('',(36.7042902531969,17.9562650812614,-2.));
#497=CARTESIAN_POINT('',(36.736541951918,17.8585434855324,-2.));
#498=CARTESIAN_POINT('',(36.7676741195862,17.7778350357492,-2.));
#499=CARTESIAN_POINT('',(36.7969752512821,17.7140834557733,-2.));
#500=CARTESIAN_POINT('',(36.8294874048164,17.6469821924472,-2.));
#501=CARTESIAN_POINT('',(36.8674061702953,17.5772348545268,-2.));
#502=CARTESIAN_POINT('',(36.9081684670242,17.5039523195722,-2.));
#503=CARTESIAN_POINT('',(36.9542277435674,17.4278696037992,-2.));
#504=CARTESIAN_POINT('',(37.0045333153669,17.3488846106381,-2.));
#505=CARTESIAN_POINT('',(37.0403630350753,17.2956375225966,-2.));
#506=CARTESIAN_POINT('',(37.0587102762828,17.2683714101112,-2.));
#507=B_SPLINE_CURVE_WITH_KNOTS('',3,(#492,#493,#494,#495,#496,#497,#498,#499,#500,#501,#502,
#503,#504,#505,#506),.UNSPECIFIED.,.F.,.F.,(4,1,1,1,1,1,1,1,1,1,1,1,4),(0.,0.0983199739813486,
0.19941747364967,0.305602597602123,0.416162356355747,0.474582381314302,0.537006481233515,
0.603857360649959,0.674089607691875,0.749416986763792,0.828253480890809,0.912054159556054,1.),.UNSPECIFIED.);
#508=CARTESIAN_POINT('',(36.6555652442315,18.2962159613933,-2.));
#509=VERTEX_POINT('',#508);
#510=CARTESIAN_POINT('',(37.0587102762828,17.2683714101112,-2.));
#511=VERTEX_POINT('',#510);
#512=EDGE_CURVE('E576',#509,#511,#507,.T.);
#513=ORIENTED_EDGE('',*,*,#512,.T.);
#514=DIRECTION('',(0.564407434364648,-0.825496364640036,0.));
#515=VECTOR('',#514,1.);
#516=CARTESIAN_POINT('',(37.0587102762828,17.2683714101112,-2.));
#517=LINE('',#516,#515);
#518=CARTESIAN_POINT('',(38.1363344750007,15.6922496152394,-2.));
#519=VERTEX_POINT('',#518);
#520=EDGE_CURVE('E534',#511,#519,#517,.T.);
#521=ORIENTED_EDGE('',*,*,#520,.T.);
#522=DIRECTION('',(0.820951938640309,0.570997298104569,0.));
#523=VECTOR('',#522,1.);
#524=CARTESIAN_POINT('',(38.1363344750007,15.6922496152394,-2.));
#525=LINE('',#524,#523);
#526=CARTESIAN_POINT('',(38.3873360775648,15.8668289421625,-2.));
#527=VERTEX_POINT('',#526);
#528=EDGE_CURVE('E540',#519,#527,#525,.T.);
#529=ORIENTED_EDGE('',*,*,#528,.T.);
#530=DIRECTION('',(-0.564610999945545,0.825357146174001,0.));
#531=VECTOR('',#530,1.);
#532=CARTESIAN_POINT('',(38.3873360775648,15.8668289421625,-2.));
#533=LINE('',#532,#531);
#534=CARTESIAN_POINT('',(37.4141790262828,17.2894050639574,-2.));
#535=VERTEX_POINT('',#534);
#536=EDGE_CURVE('E544',#527,#535,#533,.T.);
#537=ORIENTED_EDGE('',*,*,#536,.T.);
#538=CARTESIAN_POINT('',(37.4141790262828,17.2894050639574,-2.));
#539=CARTESIAN_POINT('',(37.4762697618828,17.2818120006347,-2.));
#540=CARTESIAN_POINT('',(37.5985298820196,17.2668608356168,-2.));
#541=CARTESIAN_POINT('',(37.7216669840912,17.2641141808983,-2.));
#542=CARTESIAN_POINT('',(37.7822679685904,17.2627624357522,-2.));
#543=B_SPLINE_CURVE_WITH_KNOTS('',3,(#538,#539,#540,#541,#542),.UNSPECIFIED.,.F.,.F.,(4,1,4),
(0.,0.50785763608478,1.),.UNSPECIFIED.);
#544=CARTESIAN_POINT('',(37.7822679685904,17.2627624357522,-2.));
#545=VERTEX_POINT('',#544);
#546=EDGE_CURVE('E547',#535,#545,#543,.T.);
#547=ORIENTED_EDGE('',*,*,#546,.T.);
#548=CARTESIAN_POINT('',(37.7822679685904,17.2627624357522,-2.));
#549=CARTESIAN_POINT('',(37.8190100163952,17.2637035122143,-2.));
#550=CARTESIAN_POINT('',(37.8911314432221,17.2655507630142,-2.));
#551=CARTESIAN_POINT('',(37.9971630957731,17.2801925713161,-2.));
#552=CARTESIAN_POINT('',(38.0990486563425,17.3027426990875,-2.));
#553=CARTESIAN_POINT('',(38.1965180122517,17.3363914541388,-2.));
#554=CARTESIAN_POINT('',(38.2899375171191,17.3782096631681,-2.));
#555=CARTESIAN_POINT('',(38.3791032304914,17.4300666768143,-2.));
#556=CARTESIAN_POINT('',(38.4638951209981,17.4910729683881,-2.));
#557=CARTESIAN_POINT('',(38.5434025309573,17.5609059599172,-2.));
#558=CARTESIAN_POINT('',(38.6157142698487,17.6375840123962,-2.));
#559=CARTESIAN_POINT('',(38.6801375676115,17.7187396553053,-2.));
#560=CARTESIAN_POINT('',(38.7336786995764,17.8053156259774,-2.));
#561=CARTESIAN_POINT('',(38.7781552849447,17.8955458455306,-2.));
#562=CARTESIAN_POINT('',(38.8118857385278,17.9907271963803,-2.));
#563=CARTESIAN_POINT('',(38.8364482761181,18.089776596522,-2.));
#564=CARTESIAN_POINT('',(38.8515706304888,18.1933882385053,-2.));
#565=CARTESIAN_POINT('',(38.8533697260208,18.2639133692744,-2.));
#566=CARTESIAN_POINT('',(38.8542831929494,18.2997215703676,-2.));
#567=B_SPLINE_CURVE_WITH_KNOTS('',3,(#548,#549,#550,#551,#552,#553,#554,#555,#556,#557,#558,
#559,#560,#561,#562,#563,#564,#565,#566),.UNSPECIFIED.,.F.,.F.,(4,1,1,1,1,1,1,1,1,1,1,1,1,1,1,1,
4),(0.,0.066294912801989,0.130131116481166,0.192862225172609,0.254360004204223,
0.315909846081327,0.377338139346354,0.44020526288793,0.504175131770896,0.56803363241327,
0.63022772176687,0.690861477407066,0.751421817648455,0.811465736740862,0.872750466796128,
0.935390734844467,1.),.UNSPECIFIED.);
#568=CARTESIAN_POINT('',(38.8542831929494,18.2997215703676,-2.));
#569=VERTEX_POINT('',#568);
#570=EDGE_CURVE('E552',#545,#569,#567,.T.);
#571=ORIENTED_EDGE('',*,*,#570,.T.);
#572=CARTESIAN_POINT('',(38.8542831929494,18.2997215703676,-2.));
#573=CARTESIAN_POINT('',(38.8525487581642,18.3486902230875,-2.));
#574=CARTESIAN_POINT('',(38.8491444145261,18.4448057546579,-2.));
#575=CARTESIAN_POINT('',(38.8217458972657,18.5852395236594,-2.));
#576=CARTESIAN_POINT('',(38.7766855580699,18.7180260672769,-2.));
#577=CARTESIAN_POINT('',(38.7138571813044,18.8428162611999,-2.));
#578=CARTESIAN_POINT('',(38.6347224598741,18.9578150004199,-2.));
#579=CARTESIAN_POINT('',(38.5396138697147,19.0614236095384,-2.));
#580=CARTESIAN_POINT('',(38.4291099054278,19.1521684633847,-2.));
#581=CARTESIAN_POINT('',(38.305727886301,19.2301725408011,-2.));
#582=CARTESIAN_POINT('',(38.1723748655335,19.2929075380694,-2.));
#583=CARTESIAN_POINT('',(38.0327062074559,19.3391468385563,-2.));
#584=CARTESIAN_POINT('',(37.8877920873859,19.3663455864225,-2.));
#585=CARTESIAN_POINT('',(37.7896244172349,19.3699314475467,-2.));
#586=CARTESIAN_POINT('',(37.7402006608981,19.3717367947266,-2.));
#587=B_SPLINE_CURVE_WITH_KNOTS('',3,(#572,#573,#574,#575,#576,#577,#578,#579,#580,#581,#582,
#583,#584,#585,#586),.UNSPECIFIED.,.F.,.F.,(4,1,1,1,1,1,1,1,1,1,1,1,4),(0.,0.0852490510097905,
0.167326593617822,0.248175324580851,0.328829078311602,0.409908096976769,0.490584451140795,
0.57299348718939,0.658264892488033,0.744221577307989,0.829060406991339,0.913938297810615,1.),.UNSPECIFIED.);
#588=CARTESIAN_POINT('',(37.7402006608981,19.3717367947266,-2.));
#589=VERTEX_POINT('',#588);
#590=EDGE_CURVE('E560',#569,#589,#587,.T.);
#591=ORIENTED_EDGE('',*,*,#590,.T.);
#592=CARTESIAN_POINT('',(37.7402006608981,19.3717367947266,-2.));
#593=CARTESIAN_POINT('',(37.691712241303,19.3699066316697,-2.));
#594=CARTESIAN_POINT('',(37.5959036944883,19.3662904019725,-2.));
#595=CARTESIAN_POINT('',(37.4550146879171,19.3398064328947,-2.));
#596=CARTESIAN_POINT('',(37.3200736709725,19.2951697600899,-2.));
#597=CARTESIAN_POINT('',(37.1918286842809,19.2334851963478,-2.));
#598=CARTESIAN_POINT('',(37.0730892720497,19.1561642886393,-2.));
#599=CARTESIAN_POINT('',(36.9663134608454,19.0640297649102,-2.));
#600=CARTESIAN_POINT('',(36.8739379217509,18.9570242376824,-2.));
#601=CARTESIAN_POINT('',(36.7961140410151,18.8377357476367,-2.));
#602=CARTESIAN_POINT('',(36.7336440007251,18.7095687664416,-2.));
#603=CARTESIAN_POINT('',(36.6885717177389,18.5757848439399,-2.));
#604=CARTESIAN_POINT('',(36.6608260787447,18.437346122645,-2.));
#605=CARTESIAN_POINT('',(36.6573297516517,18.3435516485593,-2.));
#606=CARTESIAN_POINT('',(36.6555652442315,18.2962159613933,-2.));
#607=B_SPLINE_CURVE_WITH_KNOTS('',3,(#592,#593,#594,#595,#596,#597,#598,#599,#600,#601,#602,
#603,#604,#605,#606),.UNSPECIFIED.,.F.,.F.,(4,1,1,1,1,1,1,1,1,1,1,1,4),(0.,0.0855321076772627,
0.169003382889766,0.25194324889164,0.335682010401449,0.419408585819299,0.501264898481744,
0.583702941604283,0.668000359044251,0.751918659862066,0.834597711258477,0.916525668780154,1.),.UNSPECIFIED.);
#608=EDGE_CURVE('E568',#589,#509,#607,.T.);
#609=ORIENTED_EDGE('',*,*,#608,.T.);
#610=EDGE_LOOP('',(#513,#521,#529,#537,#547,#571,#591,#609));
#611=FACE_BOUND('',#610,.T.);
#612=CARTESIAN_POINT('',(31.3606934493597,17.5523257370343,-2.));
#613=CARTESIAN_POINT('',(31.3591382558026,17.6152811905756,-2.));
#614=CARTESIAN_POINT('',(31.3560785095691,17.7391421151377,-2.));
#615=CARTESIAN_POINT('',(31.3300827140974,17.9209160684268,-2.));
#616=CARTESIAN_POINT('',(31.2882639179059,18.0950674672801,-2.));
#617=CARTESIAN_POINT('',(31.2288670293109,18.261271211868,-2.));
#618=CARTESIAN_POINT('',(31.1535616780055,18.4204014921,-2.));
#619=CARTESIAN_POINT('',(31.060535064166,18.5712426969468,-2.));
#620=CARTESIAN_POINT('',(30.9508679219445,18.7147594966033,-2.));
#621=CARTESIAN_POINT('',(30.8254203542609,18.8487742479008,-2.));
#622=CARTESIAN_POINT('',(30.6878530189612,18.9713136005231,-2.));
#623=CARTESIAN_POINT('',(30.5405342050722,19.0791198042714,-2.));
#624=CARTESIAN_POINT('',(30.3837522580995,19.1688373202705,-2.));
#625=CARTESIAN_POINT('',(30.219234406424,19.2438334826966,-2.));
#626=CARTESIAN_POINT('',(30.0457487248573,19.3014779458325,-2.));
#627=CARTESIAN_POINT('',(29.8636653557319,19.3418311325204,-2.));
#628=CARTESIAN_POINT('',(29.6733264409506,19.3669482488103,-2.));
#629=CARTESIAN_POINT('',(29.5434640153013,19.3701234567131,-2.));
#630=CARTESIAN_POINT('',(29.477480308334,19.3717367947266,-2.));
#631=B_SPLINE_CURVE_WITH_KNOTS('',3,(#612,#613,#614,#615,#616,#617,#618,#619,#620,#621,#622,
#623,#624,#625,#626,#627,#628,#629,#630),.UNSPECIFIED.,.F.,.F.,(4,1,1,1,1,1,1,1,1,1,1,1,1,1,1,1,
4),(0.,0.0645578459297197,0.127013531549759,0.18795481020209,0.248013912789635,
0.307747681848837,0.368234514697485,0.42946984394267,0.492743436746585,0.556257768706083,
0.618216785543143,0.679655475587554,0.74124554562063,0.803415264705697,0.866815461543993,
0.932328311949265,1.),.UNSPECIFIED.);
#632=CARTESIAN_POINT('',(31.3606934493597,17.5523257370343,-2.));
#633=VERTEX_POINT('',#632);
#634=CARTESIAN_POINT('',(29.477480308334,19.3717367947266,-2.));
#635=VERTEX_POINT('',#634);
#636=EDGE_CURVE('E427',#633,#635,#631,.T.);
#637=ORIENTED_EDGE('',*,*,#636,.T.);
#638=CARTESIAN_POINT('',(29.477480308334,19.3717367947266,-2.));
#639=CARTESIAN_POINT('',(29.4372658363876,19.3712546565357,-2.));
#640=CARTESIAN_POINT('',(29.3576653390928,19.3703003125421,-2.));
#641=CARTESIAN_POINT('',(29.2399126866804,19.3609941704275,-2.));
#642=CARTESIAN_POINT('',(29.1252703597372,19.3454805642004,-2.));
#643=CARTESIAN_POINT('',(29.0136593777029,19.3243644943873,-2.));
#644=CARTESIAN_POINT('',(28.9045367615,19.2981571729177,-2.));
#645=CARTESIAN_POINT('',(28.7987365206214,19.2640168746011,-2.));
#646=CARTESIAN_POINT('',(28.6956378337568,19.2249803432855,-2.));
#647=CARTESIAN_POINT('',(28.5958909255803,19.1800218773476,-2.));
#648=CARTESIAN_POINT('',(28.49997437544,19.1295551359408,-2.));
#649=CARTESIAN_POINT('',(28.4079180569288,19.0741395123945,-2.));
#650=CARTESIAN_POINT('',(28.3204531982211,19.01384370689,-2.));
#651=CARTESIAN_POINT('',(28.2369643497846,18.9491805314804,-2.));
#652=CARTESIAN_POINT('',(28.1588481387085,18.878781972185,-2.));
#653=CARTESIAN_POINT('',(28.0838866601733,18.8045843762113,-2.));
#654=CARTESIAN_POINT('',(28.0146255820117,18.724450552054,-2.));
#655=CARTESIAN_POINT('',(27.9718723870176,18.668045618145,-2.));
#656=CARTESIAN_POINT('',(27.9504370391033,18.6397656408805,-2.));
#657=B_SPLINE_CURVE_WITH_KNOTS('',3,(#638,#639,#640,#641,#642,#643,#644,#645,#646,#647,#648,
#649,#650,#651,#652,#653,#654,#655,#656),.UNSPECIFIED.,.F.,.F.,(4,1,1,1,1,1,1,1,1,1,1,1,1,1,1,1,
4),(0.,0.0685475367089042,0.135682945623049,0.20121498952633,0.265682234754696,
0.329266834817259,0.392395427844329,0.455069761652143,0.517126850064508,0.578790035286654,
0.639739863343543,0.700191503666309,0.759806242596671,0.819628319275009,0.879354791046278,
0.939511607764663,1.),.UNSPECIFIED.);
#658=CARTESIAN_POINT('',(27.9504370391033,18.6397656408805,-2.));
#659=VERTEX_POINT('',#658);
#660=EDGE_CURVE('E47',#635,#659,#657,.T.);
#661=ORIENTED_EDGE('',*,*,#660,.T.);
#662=DIRECTION('',(0.794127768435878,-0.607750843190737,0.));
#663=VECTOR('',#662,1.);
#664=CARTESIAN_POINT('',(27.9504370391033,18.6397656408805,-2.));
#665=LINE('',#664,#663);
#666=CARTESIAN_POINT('',(28.225276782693,18.4294291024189,-2.));
#667=VERTEX_POINT('',#666);
#668=EDGE_CURVE('E431',#659,#667,#665,.T.);
#669=ORIENTED_EDGE('',*,*,#668,.T.);
#670=CARTESIAN_POINT('',(28.225276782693,18.4294291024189,-2.));
#671=CARTESIAN_POINT('',(28.2448826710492,18.45279507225,-2.));
#672=CARTESIAN_POINT('',(28.2838301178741,18.4992119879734,-2.));
#673=CARTESIAN_POINT('',(28.346489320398,18.5643915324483,-2.));
#674=CARTESIAN_POINT('',(28.4117909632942,18.625456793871,-2.));
#675=CARTESIAN_POINT('',(28.4797100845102,18.6826986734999,-2.));
#676=CARTESIAN_POINT('',(28.5514692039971,18.7341154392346,-2.));
#677=CARTESIAN_POINT('',(28.6253300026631,18.7823865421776,-2.));
#678=CARTESIAN_POINT('',(28.7025280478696,18.8256542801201,-2.));
#679=CARTESIAN_POINT('',(28.8092797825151,18.878117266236,-2.));
#680=CARTESIAN_POINT('',(28.9489276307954,18.9328634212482,-2.));
#681=CARTESIAN_POINT('',(29.1247224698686,18.9787666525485,-2.));
#682=CARTESIAN_POINT('',(29.3082335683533,19.0079878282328,-2.));
#683=CARTESIAN_POINT('',(29.4334311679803,19.0111526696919,-2.));
#684=CARTESIAN_POINT('',(29.4971117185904,19.0127624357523,-2.));
#685=B_SPLINE_CURVE_WITH_KNOTS('',3,(#670,#671,#672,#673,#674,#675,#676,#677,#678,#679,#680,
#681,#682,#683,#684),.UNSPECIFIED.,.F.,.F.,(4,1,1,1,1,1,1,1,1,1,1,1,4),(0.,0.0631632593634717,
0.125474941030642,0.187121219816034,0.248294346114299,0.309294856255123,0.369850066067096,
0.430973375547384,0.492455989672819,0.616147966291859,0.740843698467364,0.868182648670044,1.),.UNSPECIFIED.);
#686=CARTESIAN_POINT('',(29.4971117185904,19.0127624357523,-2.));
#687=VERTEX_POINT('',#686);
#688=EDGE_CURVE('E1483',#667,#687,#685,.T.);
#689=ORIENTED_EDGE('',*,*,#688,.T.);
#690=CARTESIAN_POINT('',(29.4971117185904,19.0127624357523,-2.));
#691=CARTESIAN_POINT('',(29.5321950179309,19.0123584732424,-2.));
#692=CARTESIAN_POINT('',(29.6020360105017,19.0115542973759,-2.));
#693=CARTESIAN_POINT('',(29.7056844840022,19.0009451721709,-2.));
#694=CARTESIAN_POINT('',(29.8073975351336,18.9860339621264,-2.));
#695=CARTESIAN_POINT('',(29.9071090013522,18.9639086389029,-2.));
#696=CARTESIAN_POINT('',(30.0046919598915,18.9359360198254,-2.));
#697=CARTESIAN_POINT('',(30.1007843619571,18.9025106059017,-2.));
#698=CARTESIAN_POINT('',(30.1939949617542,18.8611557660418,-2.));
#699=CARTESIAN_POINT('',(30.2856131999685,18.8154475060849,-2.));
#700=CARTESIAN_POINT('',(30.3733924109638,18.7638200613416,-2.));
#701=CARTESIAN_POINT('',(30.4564474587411,18.70750670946,-2.));
#702=CARTESIAN_POINT('',(30.5344754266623,18.6471376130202,-2.));
#703=CARTESIAN_POINT('',(30.6075380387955,18.5824865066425,-2.));
#704=CARTESIAN_POINT('',(30.6757099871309,18.5138445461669,-2.));
#705=CARTESIAN_POINT('',(30.7384972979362,18.4404802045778,-2.));
#706=CARTESIAN_POINT('',(30.7956827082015,18.3626280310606,-2.));
#707=CARTESIAN_POINT('',(30.8483997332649,18.2813146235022,-2.));
#708=CARTESIAN_POINT('',(30.8956124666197,18.1967768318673,-2.));
#709=CARTESIAN_POINT('',(30.9351423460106,18.1087017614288,-2.));
#710=CARTESIAN_POINT('',(30.9701474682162,18.0185976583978,-2.));
#711=CARTESIAN_POINT('',(30.9978467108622,17.9254464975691,-2.));
#712=CARTESIAN_POINT('',(31.0197712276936,17.8299037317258,-2.));
#713=CARTESIAN_POINT('',(31.0348988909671,17.7317129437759,-2.));
#714=CARTESIAN_POINT('',(31.0453873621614,17.6310792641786,-2.));
#715=CARTESIAN_POINT('',(31.0461875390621,17.5628699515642,-2.));
#716=CARTESIAN_POINT('',(31.0465908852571,17.5284875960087,-2.));
#717=B_SPLINE_CURVE_WITH_KNOTS('',3,(#690,#691,#692,#693,#694,#695,#696,#697,#698,#699,#700,
#701,#702,#703,#704,#705,#706,#707,#708,#709,#710,#711,#712,#713,#714,#715,#716),.UNSPECIFIED.,
.F.,.F.,(4,1,1,1,1,1,1,1,1,1,1,1,1,1,1,1,1,1,1,1,1,1,1,1,4),(0.,0.0439549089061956,
0.0875018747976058,0.130462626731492,0.172752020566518,0.215403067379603,0.25764982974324,
0.300152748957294,0.343121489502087,0.385925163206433,0.427685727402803,0.46881795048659,
0.509491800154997,0.54988303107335,0.589980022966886,0.630405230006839,0.670868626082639,
0.711383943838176,0.751627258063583,0.791775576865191,0.832458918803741,0.873319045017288,
0.914542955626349,0.956923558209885,1.),.UNSPECIFIED.);
#718=CARTESIAN_POINT('',(31.0465908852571,17.5284875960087,-2.));
#719=VERTEX_POINT('',#718);
#720=EDGE_CURVE('E1427',#687,#719,#717,.T.);
#721=ORIENTED_EDGE('',*,*,#720,.T.);
#722=CARTESIAN_POINT('',(31.0465908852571,17.5284875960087,-2.));
#723=CARTESIAN_POINT('',(31.0453290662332,17.4767562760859,-2.));
#724=CARTESIAN_POINT('',(31.0428516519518,17.3751886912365,-2.));
#725=CARTESIAN_POINT('',(31.0208033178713,17.2264180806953,-2.));
#726=CARTESIAN_POINT('',(30.9872982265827,17.083897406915,-2.));
#727=CARTESIAN_POINT('',(30.937082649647,16.9485175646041,-2.));
#728=CARTESIAN_POINT('',(30.8751635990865,16.8186092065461,-2.));
#729=CARTESIAN_POINT('',(30.7969229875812,16.6963703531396,-2.));
#730=CARTESIAN_POINT('',(30.706306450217,16.5799537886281,-2.));
#731=CARTESIAN_POINT('',(30.6020320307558,16.4721108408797,-2.));
#732=CARTESIAN_POINT('',(30.4876262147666,16.3735971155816,-2.));
#733=CARTESIAN_POINT('',(30.3648783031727,16.2868465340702,-2.));
#734=CARTESIAN_POINT('',(30.2340940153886,16.2145316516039,-2.));
#735=CARTESIAN_POINT('',(30.096717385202,16.1543557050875,-2.));
#736=CARTESIAN_POINT('',(29.9516912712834,16.108098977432,-2.));
#737=CARTESIAN_POINT('',(29.7992764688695,16.0755348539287,-2.));
#738=CARTESIAN_POINT('',(29.6398044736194,16.0542926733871,-2.));
#739=CARTESIAN_POINT('',(29.5308350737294,16.052258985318,-2.));
#740=CARTESIAN_POINT('',(29.4753769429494,16.0512239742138,-2.));
#741=B_SPLINE_CURVE_WITH_KNOTS('',3,(#722,#723,#724,#725,#726,#727,#728,#729,#730,#731,#732,
#733,#734,#735,#736,#737,#738,#739,#740),.UNSPECIFIED.,.F.,.F.,(4,1,1,1,1,1,1,1,1,1,1,1,1,1,1,1,
4),(0.,0.0643232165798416,0.126290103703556,0.186726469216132,0.246146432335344,
0.305575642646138,0.365429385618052,0.42632630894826,0.488839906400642,0.551724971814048,
0.613918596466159,0.675483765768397,0.737333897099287,0.800229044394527,0.864502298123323,
0.931040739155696,1.),.UNSPECIFIED.);
#742=CARTESIAN_POINT('',(29.4753769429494,16.0512239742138,-2.));
#743=VERTEX_POINT('',#742);
#744=EDGE_CURVE('E1424',#719,#743,#741,.T.);
#745=ORIENTED_EDGE('',*,*,#744,.T.);
#746=CARTESIAN_POINT('',(29.4753769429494,16.0512239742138,-2.));
#747=CARTESIAN_POINT('',(29.4142742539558,16.0529127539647,-2.));
#748=CARTESIAN_POINT('',(29.2940095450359,16.0562366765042,-2.));
#749=CARTESIAN_POINT('',(29.1176415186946,16.0843959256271,-2.));
#750=CARTESIAN_POINT('',(28.9488057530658,16.1300538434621,-2.));
#751=CARTESIAN_POINT('',(28.7874931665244,16.1939517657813,-2.));
#752=CARTESIAN_POINT('',(28.6341585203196,16.277017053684,-2.));
#753=CARTESIAN_POINT('',(28.4885618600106,16.3777149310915,-2.));
#754=CARTESIAN_POINT('',(28.3505802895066,16.4970032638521,-2.));
#755=CARTESIAN_POINT('',(28.2676090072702,16.5880863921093,-2.));
#756=CARTESIAN_POINT('',(28.225276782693,16.6345573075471,-2.));
#757=B_SPLINE_CURVE_WITH_KNOTS('',3,(#746,#747,#748,#749,#750,#751,#752,#753,#754,#755,#756),
.UNSPECIFIED.,.F.,.F.,(4,1,1,1,1,1,1,1,4),(0.,0.128515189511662,0.252948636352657,
0.374754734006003,0.495939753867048,0.617180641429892,0.740909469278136,0.867811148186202,1.),.UNSPECIFIED.);
#758=CARTESIAN_POINT('',(28.225276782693,16.6345573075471,-2.));
#759=VERTEX_POINT('',#758);
#760=EDGE_CURVE('E1417',#743,#759,#757,.T.);
#761=ORIENTED_EDGE('',*,*,#760,.T.);
#762=DIRECTION('',(-0.797062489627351,-0.603896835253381,0.));
#763=VECTOR('',#762,1.);
#764=CARTESIAN_POINT('',(28.225276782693,16.6345573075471,-2.));
#765=LINE('',#764,#763);
#766=CARTESIAN_POINT('',(27.9504370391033,16.4263241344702,-2.));
#767=VERTEX_POINT('',#766);
#768=EDGE_CURVE('E1408',#759,#767,#765,.T.);
#769=ORIENTED_EDGE('',*,*,#768,.T.);
#770=CARTESIAN_POINT('',(27.9504370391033,16.4263241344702,-2.));
#771=CARTESIAN_POINT('',(27.9725551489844,16.3977856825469,-2.));
#772=CARTESIAN_POINT('',(28.0166854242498,16.3408454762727,-2.));
#773=CARTESIAN_POINT('',(28.0881434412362,16.2605737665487,-2.));
#774=CARTESIAN_POINT('',(28.1634207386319,16.1850697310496,-2.));
#775=CARTESIAN_POINT('',(28.2430764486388,16.1149421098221,-2.));
#776=CARTESIAN_POINT('',(28.3261942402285,16.0487876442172,-2.));
#777=CARTESIAN_POINT('',(28.4142665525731,15.9884858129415,-2.));
#778=CARTESIAN_POINT('',(28.5061355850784,15.9331949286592,-2.));
#779=CARTESIAN_POINT('',(28.601490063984,15.8825680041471,-2.));
#780=CARTESIAN_POINT('',(28.7002286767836,15.8376507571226,-2.));
#781=CARTESIAN_POINT('',(28.8022331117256,15.7991969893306,-2.));
#782=CARTESIAN_POINT('',(28.9070636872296,15.766072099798,-2.));
#783=CARTESIAN_POINT('',(29.0147251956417,15.7388201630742,-2.));
#784=CARTESIAN_POINT('',(29.1254409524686,15.7175490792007,-2.));
#785=CARTESIAN_POINT('',(29.2388114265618,15.7033294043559,-2.));
#786=CARTESIAN_POINT('',(29.3550813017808,15.6935874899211,-2.));
#787=CARTESIAN_POINT('',(29.4335227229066,15.6926995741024,-2.));
#788=CARTESIAN_POINT('',(29.4732735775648,15.6922496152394,-2.));
#789=B_SPLINE_CURVE_WITH_KNOTS('',3,(#770,#771,#772,#773,#774,#775,#776,#777,#778,#779,#780,
#781,#782,#783,#784,#785,#786,#787,#788),.UNSPECIFIED.,.F.,.F.,(4,1,1,1,1,1,1,1,1,1,1,1,1,1,1,1,
4),(0.,0.061674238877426,0.123053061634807,0.183475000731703,0.243726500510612,
0.304278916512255,0.364862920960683,0.42594620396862,0.487391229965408,0.549220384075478,
0.611143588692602,0.673528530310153,0.736961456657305,0.80078528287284,0.866012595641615,
0.932100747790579,1.),.UNSPECIFIED.);
#790=CARTESIAN_POINT('',(29.4732735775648,15.6922496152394,-2.));
#791=VERTEX_POINT('',#790);
#792=EDGE_CURVE('E1416',#767,#791,#789,.T.);
#793=ORIENTED_EDGE('',*,*,#792,.T.);
#794=CARTESIAN_POINT('',(29.4732735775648,15.6922496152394,-2.));
#795=CARTESIAN_POINT('',(29.5109172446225,15.6925116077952,-2.));
#796=CARTESIAN_POINT('',(29.5853529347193,15.6930296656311,-2.));
#797=CARTESIAN_POINT('',(29.6952516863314,15.7014218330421,-2.));
#798=CARTESIAN_POINT('',(29.802241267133,15.712871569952,-2.));
#799=CARTESIAN_POINT('',(29.9060158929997,15.730111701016,-2.));
#800=CARTESIAN_POINT('',(30.0071418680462,15.7504560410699,-2.));
#801=CARTESIAN_POINT('',(30.104702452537,15.7777272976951,-2.));
#802=CARTESIAN_POINT('',(30.1996576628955,15.8082764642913,-2.));
#803=CARTESIAN_POINT('',(30.2916260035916,15.844181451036,-2.));
#804=CARTESIAN_POINT('',(30.3806857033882,15.8846976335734,-2.));
#805=CARTESIAN_POINT('',(30.4665495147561,15.9304891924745,-2.));
#806=CARTESIAN_POINT('',(30.5491779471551,15.9811710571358,-2.));
#807=CARTESIAN_POINT('',(30.6293833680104,16.0356260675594,-2.));
#808=CARTESIAN_POINT('',(30.7059809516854,16.0956033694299,-2.));
#809=CARTESIAN_POINT('',(30.7796344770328,16.1602700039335,-2.));
#810=CARTESIAN_POINT('',(30.8507569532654,16.2294080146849,-2.));
#811=CARTESIAN_POINT('',(30.8947596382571,16.2792628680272,-2.));
#812=CARTESIAN_POINT('',(30.9168833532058,16.3043289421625,-2.));
#813=B_SPLINE_CURVE_WITH_KNOTS('',3,(#794,#795,#796,#797,#798,#799,#800,#801,#802,#803,#804,
#805,#806,#807,#808,#809,#810,#811,#812),.UNSPECIFIED.,.F.,.F.,(4,1,1,1,1,1,1,1,1,1,1,1,1,1,1,1,
4),(0.,0.0696628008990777,0.137749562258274,0.203916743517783,0.268779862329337,
0.332413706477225,0.394753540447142,0.45618003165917,0.516995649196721,0.577395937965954,
0.637198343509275,0.696999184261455,0.75675619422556,0.816553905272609,0.876947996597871,
0.938131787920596,1.),.UNSPECIFIED.);
#814=CARTESIAN_POINT('',(30.9168833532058,16.3043289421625,-2.));
#815=VERTEX_POINT('',#814);
#816=EDGE_CURVE('E1441',#791,#815,#813,.T.);
#817=ORIENTED_EDGE('',*,*,#816,.T.);
#818=CARTESIAN_POINT('',(30.9168833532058,16.3043289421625,-2.));
#819=CARTESIAN_POINT('',(30.9523189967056,16.3478701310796,-2.));
#820=CARTESIAN_POINT('',(31.0227624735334,16.4344268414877,-2.));
#821=CARTESIAN_POINT('',(31.1128881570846,16.5747128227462,-2.));
#822=CARTESIAN_POINT('',(31.1900357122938,16.721181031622,-2.));
#823=CARTESIAN_POINT('',(31.252411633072,16.8746009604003,-2.));
#824=CARTESIAN_POINT('',(31.3011743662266,17.0346283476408,-2.));
#825=CARTESIAN_POINT('',(31.3349555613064,17.2013438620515,-2.));
#826=CARTESIAN_POINT('',(31.3569071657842,17.3745918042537,-2.));
#827=CARTESIAN_POINT('',(31.3594174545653,17.4924285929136,-2.));
#828=CARTESIAN_POINT('',(31.3606934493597,17.5523257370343,-2.));
#829=B_SPLINE_CURVE_WITH_KNOTS('',3,(#818,#819,#820,#821,#822,#823,#824,#825,#826,#827,#828),
.UNSPECIFIED.,.F.,.F.,(4,1,1,1,1,1,1,1,4),(0.,0.12432850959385,0.247156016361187,
0.368779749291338,0.490733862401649,0.613613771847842,0.738957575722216,0.867310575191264,1.),.UNSPECIFIED.);
#830=EDGE_CURVE('E1449',#815,#633,#829,.T.);
#831=ORIENTED_EDGE('',*,*,#830,.T.);
#832=EDGE_LOOP('',(#637,#661,#669,#689,#721,#745,#761,#769,#793,#817,#831));
#833=FACE_BOUND('',#832,.T.);
#834=ADVANCED_FACE('F32',(#81,#307,#377,#388,#399,#410,#421,#491,#611,#833),#23,.T.);
#835=CARTESIAN_POINT('',(0.,0.,-2.));
#836=DIRECTION('',(-1.,0.,0.));
#837=DIRECTION('',(0.,0.,1.));
#838=AXIS2_PLACEMENT_3D('',#835,#836,#837);
#839=PLANE('',#838);
#840=ORIENTED_EDGE('',*,*,#464,.T.);
#841=DIRECTION('',(0.,0.,1.));
#842=VECTOR('',#841,1.);
#843=CARTESIAN_POINT('',(0.,10.,-2.));
#844=LINE('',#843,#842);
#845=CARTESIAN_POINT('',(0.,10.,0.));
#846=VERTEX_POINT('',#845);
#847=EDGE_CURVE('E764',#455,#846,#844,.T.);
#848=ORIENTED_EDGE('',*,*,#847,.T.);
#849=DIRECTION('',(0.,-1.,0.));
#850=VECTOR('',#849,1.);
#851=CARTESIAN_POINT('',(0.,0.,0.));
#852=LINE('',#851,#850);
#853=CARTESIAN_POINT('',(0.,50.,0.));
#854=VERTEX_POINT('',#853);
#855=EDGE_CURVE('E806',#854,#846,#852,.T.);
#856=ORIENTED_EDGE('',*,*,#855,.F.);
#857=DIRECTION('',(0.,0.,1.));
#858=VECTOR('',#857,1.);
#859=CARTESIAN_POINT('',(0.,50.,-2.));
#860=LINE('',#859,#858);
#861=EDGE_CURVE('E767',#854,#463,#860,.F.);
#862=ORIENTED_EDGE('',*,*,#861,.T.);
#863=EDGE_LOOP('',(#840,#848,#856,#862));
#864=FACE_BOUND('',#863,.T.);
#865=ADVANCED_FACE('F705',(#864),#839,.T.);
#866=CARTESIAN_POINT('',(0.,60.,-2.));
#867=DIRECTION('',(0.,1.,0.));
#868=DIRECTION('',(0.,0.,1.));
#869=AXIS2_PLACEMENT_3D('',#866,#867,#868);
#870=PLANE('',#869);
#871=ORIENTED_EDGE('',*,*,#481,.T.);
#872=DIRECTION('',(0.,0.,1.));
#873=VECTOR('',#872,1.);
#874=CARTESIAN_POINT('',(10.,60.,-2.));
#875=LINE('',#874,#873);
#876=CARTESIAN_POINT('',(10.,60.,0.));
#877=VERTEX_POINT('',#876);
#878=EDGE_CURVE('E757',#472,#877,#875,.T.);
#879=ORIENTED_EDGE('',*,*,#878,.T.);
#880=DIRECTION('',(-1.,0.,0.));
#881=VECTOR('',#880,1.);
#882=CARTESIAN_POINT('',(0.,60.,0.));
#883=LINE('',#882,#881);
#884=CARTESIAN_POINT('',(60.,60.,0.));
#885=VERTEX_POINT('',#884);
#886=EDGE_CURVE('E796',#885,#877,#883,.T.);
#887=ORIENTED_EDGE('',*,*,#886,.F.);
#888=DIRECTION('',(0.,0.,1.));
#889=VECTOR('',#888,1.);
#890=CARTESIAN_POINT('',(60.,60.,-2.));
#891=LINE('',#890,#889);
#892=EDGE_CURVE('E762',#885,#480,#891,.F.);
#893=ORIENTED_EDGE('',*,*,#892,.T.);
#894=EDGE_LOOP('',(#871,#879,#887,#893));
#895=FACE_BOUND('',#894,.T.);
#896=ADVANCED_FACE('F714',(#895),#870,.T.);
#897=CARTESIAN_POINT('',(70.,0.,-2.));
#898=DIRECTION('',(1.,0.,0.));
#899=DIRECTION('',(0.,0.,-1.));
#900=AXIS2_PLACEMENT_3D('',#897,#898,#899);
#901=PLANE('',#900);
#902=DIRECTION('',(0.,1.,0.));
#903=VECTOR('',#902,1.);
#904=CARTESIAN_POINT('',(70.,0.,0.));
#905=LINE('',#904,#903);
#906=CARTESIAN_POINT('',(70.,10.,0.));
#907=VERTEX_POINT('',#906);
#908=CARTESIAN_POINT('',(70.,50.,0.));
#909=VERTEX_POINT('',#908);
#910=EDGE_CURVE('E800',#907,#909,#905,.T.);
#911=ORIENTED_EDGE('',*,*,#910,.F.);
#912=DIRECTION('',(0.,0.,1.));
#913=VECTOR('',#912,1.);
#914=CARTESIAN_POINT('',(70.,10.,-2.));
#915=LINE('',#914,#913);
#916=EDGE_CURVE('E777',#907,#427,#915,.F.);
#917=ORIENTED_EDGE('',*,*,#916,.T.);
#918=ORIENTED_EDGE('',*,*,#430,.T.);
#919=DIRECTION('',(0.,0.,1.));
#920=VECTOR('',#919,1.);
#921=CARTESIAN_POINT('',(70.,50.,-2.));
#922=LINE('',#921,#920);
#923=EDGE_CURVE('E779',#429,#909,#922,.T.);
#924=ORIENTED_EDGE('',*,*,#923,.T.);
#925=EDGE_LOOP('',(#911,#917,#918,#924));
#926=FACE_BOUND('',#925,.T.);
#927=ADVANCED_FACE('F717',(#926),#901,.T.);
#928=CARTESIAN_POINT('',(0.,0.,-2.));
#929=DIRECTION('',(0.,-1.,0.));
#930=DIRECTION('',(0.,0.,-1.));
#931=AXIS2_PLACEMENT_3D('',#928,#929,#930);
#932=PLANE('',#931);
#933=ORIENTED_EDGE('',*,*,#447,.T.);
#934=DIRECTION('',(0.,0.,1.));
#935=VECTOR('',#934,1.);
#936=CARTESIAN_POINT('',(60.,0.,-2.));
#937=LINE('',#936,#935);
#938=CARTESIAN_POINT('',(60.,0.,0.));
#939=VERTEX_POINT('',#938);
#940=EDGE_CURVE('E790',#438,#939,#937,.T.);
#941=ORIENTED_EDGE('',*,*,#940,.T.);
#942=DIRECTION('',(1.,0.,0.));
#943=VECTOR('',#942,1.);
#944=CARTESIAN_POINT('',(0.,0.,0.));
#945=LINE('',#944,#943);
#946=CARTESIAN_POINT('',(10.,0.,0.));
#947=VERTEX_POINT('',#946);
#948=EDGE_CURVE('E803',#947,#939,#945,.T.);
#949=ORIENTED_EDGE('',*,*,#948,.F.);
#950=DIRECTION('',(0.,0.,1.));
#951=VECTOR('',#950,1.);
#952=CARTESIAN_POINT('',(10.,0.,-2.));
#953=LINE('',#952,#951);
#954=EDGE_CURVE('E793',#947,#446,#953,.F.);
#955=ORIENTED_EDGE('',*,*,#954,.T.);
#956=EDGE_LOOP('',(#933,#941,#949,#955));
#957=FACE_BOUND('',#956,.T.);
#958=ADVANCED_FACE('F712',(#957),#932,.T.);
#959=CARTESIAN_POINT('',(0.,0.,0.));
#960=DIRECTION('',(0.,0.,-1.));
#961=DIRECTION('',(-1.,0.,0.));
#962=AXIS2_PLACEMENT_3D('',#959,#960,#961);
#963=PLANE('',#962);
#964=DIRECTION('',(0.,-1.,0.));
#965=VECTOR('',#964,1.);
#966=CARTESIAN_POINT('',(45.,35.,0.));
#967=LINE('',#966,#965);
#968=CARTESIAN_POINT('',(45.,35.,0.));
#969=VERTEX_POINT('',#968);
#970=CARTESIAN_POINT('',(45.,25.,0.));
#971=VERTEX_POINT('',#970);
#972=EDGE_CURVE('E842',#969,#971,#967,.T.);
#973=ORIENTED_EDGE('',*,*,#972,.T.);
#974=CARTESIAN_POINT('',(44.,25.,0.));
#975=DIRECTION('',(0.,0.,-1.));
#976=DIRECTION('',(-1.,0.,0.));
#977=AXIS2_PLACEMENT_3D('',#974,#975,#976);
#978=CIRCLE('',#977,1.);
#979=CARTESIAN_POINT('',(44.,24.,0.));
#980=VERTEX_POINT('',#979);
#981=EDGE_CURVE('E858',#971,#980,#978,.T.);
#982=ORIENTED_EDGE('',*,*,#981,.T.);
#983=DIRECTION('',(-1.,0.,0.));
#984=VECTOR('',#983,1.);
#985=CARTESIAN_POINT('',(44.,24.,0.));
#986=LINE('',#985,#984);
#987=CARTESIAN_POINT('',(26.,24.,0.));
#988=VERTEX_POINT('',#987);
#989=EDGE_CURVE('E897',#980,#988,#986,.T.);
#990=ORIENTED_EDGE('',*,*,#989,.T.);
#991=CARTESIAN_POINT('',(26.,25.,0.));
#992=DIRECTION('',(0.,0.,-1.));
#993=DIRECTION('',(-1.,0.,0.));
#994=AXIS2_PLACEMENT_3D('',#991,#992,#993);
#995=CIRCLE('',#994,1.);
#996=CARTESIAN_POINT('',(25.,25.,0.));
#997=VERTEX_POINT('',#996);
#998=EDGE_CURVE('E894',#988,#997,#995,.T.);
#999=ORIENTED_EDGE('',*,*,#998,.T.);
#1000=DIRECTION('',(0.,1.,0.));
#1001=VECTOR('',#1000,1.);
#1002=CARTESIAN_POINT('',(25.,35.,0.));
#1003=LINE('',#1002,#1001);
#1004=CARTESIAN_POINT('',(25.,35.,0.));
#1005=VERTEX_POINT('',#1004);
#1006=EDGE_CURVE('E891',#997,#1005,#1003,.T.);
#1007=ORIENTED_EDGE('',*,*,#1006,.T.);
#1008=CARTESIAN_POINT('',(26.,35.,0.));
#1009=DIRECTION('',(0.,0.,-1.));
#1010=DIRECTION('',(-1.,0.,0.));
#1011=AXIS2_PLACEMENT_3D('',#1008,#1009,#1010);
#1012=CIRCLE('',#1011,1.);
#1013=CARTESIAN_POINT('',(26.,36.,0.));
#1014=VERTEX_POINT('',#1013);
#1015=EDGE_CURVE('E888',#1005,#1014,#1012,.T.);
#1016=ORIENTED_EDGE('',*,*,#1015,.T.);
#1017=DIRECTION('',(1.,0.,0.));
#1018=VECTOR('',#1017,1.);
#1019=CARTESIAN_POINT('',(44.,36.,0.));
#1020=LINE('',#1019,#1018);
#1021=CARTESIAN_POINT('',(44.,36.,0.));
#1022=VERTEX_POINT('',#1021);
#1023=EDGE_CURVE('E885',#1014,#1022,#1020,.T.);
#1024=ORIENTED_EDGE('',*,*,#1023,.T.);
#1025=CARTESIAN_POINT('',(44.,35.,0.));
#1026=DIRECTION('',(0.,0.,-1.));
#1027=DIRECTION('',(-1.,0.,0.));
#1028=AXIS2_PLACEMENT_3D('',#1025,#1026,#1027);
#1029=CIRCLE('',#1028,1.);
#1030=EDGE_CURVE('E882',#1022,#969,#1029,.T.);
#1031=ORIENTED_EDGE('',*,*,#1030,.T.);
#1032=EDGE_LOOP('',(#973,#982,#990,#999,#1007,#1016,#1024,#1031));
#1033=FACE_BOUND('',#1032,.T.);
#1034=CARTESIAN_POINT('',(22.5,30.,0.));
#1035=DIRECTION('',(0.,0.,-1.));
#1036=DIRECTION('',(-1.,0.,0.));
#1037=AXIS2_PLACEMENT_3D('',#1034,#1035,#1036);
#1038=CIRCLE('',#1037,1.5);
#1039=CARTESIAN_POINT('',(21.,30.,0.));
#1040=VERTEX_POINT('',#1039);
#1041=EDGE_CURVE('E829',#1040,#1040,#1038,.T.);
#1042=ORIENTED_EDGE('',*,*,#1041,.T.);
#1043=EDGE_LOOP('',(#1042));
#1044=FACE_BOUND('',#1043,.T.);
#1045=CARTESIAN_POINT('',(47.5,30.,0.));
#1046=DIRECTION('',(0.,0.,-1.));
#1047=DIRECTION('',(-1.,0.,0.));
#1048=AXIS2_PLACEMENT_3D('',#1045,#1046,#1047);
#1049=CIRCLE('',#1048,1.5);
#1050=CARTESIAN_POINT('',(46.,30.,0.));
#1051=VERTEX_POINT('',#1050);
#1052=EDGE_CURVE('E825',#1051,#1051,#1049,.T.);
#1053=ORIENTED_EDGE('',*,*,#1052,.T.);
#1054=EDGE_LOOP('',(#1053));
#1055=FACE_BOUND('',#1054,.T.);
#1056=CARTESIAN_POINT('',(60.,10.,0.));
#1057=DIRECTION('',(0.,0.,1.));
#1058=DIRECTION('',(1.,0.,0.));
#1059=AXIS2_PLACEMENT_3D('',#1056,#1057,#1058);
#1060=CIRCLE('',#1059,2.1);
#1061=CARTESIAN_POINT('',(62.1,10.,0.));
#1062=VERTEX_POINT('',#1061);
#1063=EDGE_CURVE('E822',#1062,#1062,#1060,.T.);
#1064=ORIENTED_EDGE('',*,*,#1063,.F.);
#1065=EDGE_LOOP('',(#1064));
#1066=FACE_BOUND('',#1065,.T.);
#1067=CARTESIAN_POINT('',(10.,50.,0.));
#1068=DIRECTION('',(0.,0.,1.));
#1069=DIRECTION('',(1.,0.,0.));
#1070=AXIS2_PLACEMENT_3D('',#1067,#1068,#1069);
#1071=CIRCLE('',#1070,2.1);
#1072=CARTESIAN_POINT('',(12.1,50.,0.));
#1073=VERTEX_POINT('',#1072);
#1074=EDGE_CURVE('E809',#1073,#1073,#1071,.T.);
#1075=ORIENTED_EDGE('',*,*,#1074,.F.);
#1076=EDGE_LOOP('',(#1075));
#1077=FACE_BOUND('',#1076,.T.);
#1078=ORIENTED_EDGE('',*,*,#948,.T.);
#1079=CARTESIAN_POINT('',(60.,10.,0.));
#1080=DIRECTION('',(0.,0.,-1.));
#1081=DIRECTION('',(-1.,0.,0.));
#1082=AXIS2_PLACEMENT_3D('',#1079,#1080,#1081);
#1083=CIRCLE('',#1082,10.);
#1084=EDGE_CURVE('E782',#939,#907,#1083,.F.);
#1085=ORIENTED_EDGE('',*,*,#1084,.T.);
#1086=ORIENTED_EDGE('',*,*,#910,.T.);
#1087=CARTESIAN_POINT('',(60.,50.,0.));
#1088=DIRECTION('',(0.,0.,-1.));
#1089=DIRECTION('',(-1.,0.,0.));
#1090=AXIS2_PLACEMENT_3D('',#1087,#1088,#1089);
#1091=CIRCLE('',#1090,10.);
#1092=EDGE_CURVE('E788',#909,#885,#1091,.F.);
#1093=ORIENTED_EDGE('',*,*,#1092,.T.);
#1094=ORIENTED_EDGE('',*,*,#886,.T.);
#1095=CARTESIAN_POINT('',(10.,50.,0.));
#1096=DIRECTION('',(0.,0.,-1.));
#1097=DIRECTION('',(-1.,0.,0.));
#1098=AXIS2_PLACEMENT_3D('',#1095,#1096,#1097);
#1099=CIRCLE('',#1098,10.);
#1100=EDGE_CURVE('E786',#877,#854,#1099,.F.);
#1101=ORIENTED_EDGE('',*,*,#1100,.T.);
#1102=ORIENTED_EDGE('',*,*,#855,.T.);
#1103=CARTESIAN_POINT('',(10.,10.,0.));
#1104=DIRECTION('',(0.,0.,-1.));
#1105=DIRECTION('',(-1.,0.,0.));
#1106=AXIS2_PLACEMENT_3D('',#1103,#1104,#1105);
#1107=CIRCLE('',#1106,10.);
#1108=EDGE_CURVE('E784',#846,#947,#1107,.F.);
#1109=ORIENTED_EDGE('',*,*,#1108,.T.);
#1110=EDGE_LOOP('',(#1078,#1085,#1086,#1093,#1094,#1101,#1102,#1109));
#1111=FACE_BOUND('',#1110,.T.);
#1112=ADVANCED_FACE('F708',(#1033,#1044,#1055,#1066,#1077,#1111),#963,.F.);
#1113=CARTESIAN_POINT('',(60.,10.,-2.));
#1114=DIRECTION('',(0.,0.,1.));
#1115=DIRECTION('',(1.,0.,0.));
#1116=AXIS2_PLACEMENT_3D('',#1113,#1114,#1115);
#1117=CYLINDRICAL_SURFACE('',#1116,10.);
#1118=ORIENTED_EDGE('',*,*,#439,.F.);
#1119=ORIENTED_EDGE('',*,*,#916,.F.);
#1120=ORIENTED_EDGE('',*,*,#1084,.F.);
#1121=ORIENTED_EDGE('',*,*,#940,.F.);
#1122=EDGE_LOOP('',(#1118,#1119,#1120,#1121));
#1123=FACE_BOUND('',#1122,.T.);
#1124=ADVANCED_FACE('F711',(#1123),#1117,.T.);
#1125=CARTESIAN_POINT('',(10.,10.,-2.));
#1126=DIRECTION('',(0.,0.,1.));
#1127=DIRECTION('',(1.,0.,0.));
#1128=AXIS2_PLACEMENT_3D('',#1125,#1126,#1127);
#1129=CYLINDRICAL_SURFACE('',#1128,10.);
#1130=ORIENTED_EDGE('',*,*,#456,.F.);
#1131=ORIENTED_EDGE('',*,*,#954,.F.);
#1132=ORIENTED_EDGE('',*,*,#1108,.F.);
#1133=ORIENTED_EDGE('',*,*,#847,.F.);
#1134=EDGE_LOOP('',(#1130,#1131,#1132,#1133));
#1135=FACE_BOUND('',#1134,.T.);
#1136=ADVANCED_FACE('F730',(#1135),#1129,.T.);
#1137=CARTESIAN_POINT('',(10.,50.,-2.));
#1138=DIRECTION('',(0.,0.,1.));
#1139=DIRECTION('',(1.,0.,0.));
#1140=AXIS2_PLACEMENT_3D('',#1137,#1138,#1139);
#1141=CYLINDRICAL_SURFACE('',#1140,10.);
#1142=ORIENTED_EDGE('',*,*,#473,.F.);
#1143=ORIENTED_EDGE('',*,*,#861,.F.);
#1144=ORIENTED_EDGE('',*,*,#1100,.F.);
#1145=ORIENTED_EDGE('',*,*,#878,.F.);
#1146=EDGE_LOOP('',(#1142,#1143,#1144,#1145));
#1147=FACE_BOUND('',#1146,.T.);
#1148=ADVANCED_FACE('F734',(#1147),#1141,.T.);
#1149=CARTESIAN_POINT('',(60.,50.,-2.));
#1150=DIRECTION('',(0.,0.,1.));
#1151=DIRECTION('',(1.,0.,0.));
#1152=AXIS2_PLACEMENT_3D('',#1149,#1150,#1151);
#1153=CYLINDRICAL_SURFACE('',#1152,10.);
#1154=ORIENTED_EDGE('',*,*,#488,.F.);
#1155=ORIENTED_EDGE('',*,*,#892,.F.);
#1156=ORIENTED_EDGE('',*,*,#1092,.F.);
#1157=ORIENTED_EDGE('',*,*,#923,.F.);
#1158=EDGE_LOOP('',(#1154,#1155,#1156,#1157));
#1159=FACE_BOUND('',#1158,.T.);
#1160=ADVANCED_FACE('F701',(#1159),#1153,.T.);
#1161=CARTESIAN_POINT('',(10.,50.,-2.));
#1162=DIRECTION('',(0.,0.,1.));
#1163=DIRECTION('',(1.,0.,0.));
#1164=AXIS2_PLACEMENT_3D('',#1161,#1162,#1163);
#1165=CYLINDRICAL_SURFACE('',#1164,2.1);
#1166=CARTESIAN_POINT('',(10.,50.,-0.100000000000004));
#1167=DIRECTION('',(0.,0.,-1.));
#1168=DIRECTION('',(-1.,0.,0.));
#1169=AXIS2_PLACEMENT_3D('',#1166,#1167,#1168);
#1170=CIRCLE('',#1169,2.1);
#1171=CARTESIAN_POINT('',(7.9,50.,-0.100000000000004));
#1172=VERTEX_POINT('',#1171);
#1173=EDGE_CURVE('E40',#1172,#1172,#1170,.T.);
#1174=ORIENTED_EDGE('',*,*,#1173,.T.);
#1175=EDGE_LOOP('',(#1174));
#1176=FACE_BOUND('',#1175,.T.);
#1177=ORIENTED_EDGE('',*,*,#1074,.T.);
#1178=EDGE_LOOP('',(#1177));
#1179=FACE_BOUND('',#1178,.T.);
#1180=ADVANCED_FACE('F697',(#1176,#1179),#1165,.F.);
#1181=CARTESIAN_POINT('',(60.,10.,-2.));
#1182=DIRECTION('',(0.,0.,1.));
#1183=DIRECTION('',(1.,0.,0.));
#1184=AXIS2_PLACEMENT_3D('',#1181,#1182,#1183);
#1185=CYLINDRICAL_SURFACE('',#1184,2.1);
#1186=CARTESIAN_POINT('',(60.,10.,-0.100000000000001));
#1187=DIRECTION('',(0.,0.,-1.));
#1188=DIRECTION('',(-1.,0.,0.));
#1189=AXIS2_PLACEMENT_3D('',#1186,#1187,#1188);
#1190=CIRCLE('',#1189,2.1);
#1191=CARTESIAN_POINT('',(57.9,10.,-0.100000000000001));
#1192=VERTEX_POINT('',#1191);
#1193=EDGE_CURVE('E11',#1192,#1192,#1190,.T.);
#1194=ORIENTED_EDGE('',*,*,#1193,.T.);
#1195=EDGE_LOOP('',(#1194));
#1196=FACE_BOUND('',#1195,.T.);
#1197=ORIENTED_EDGE('',*,*,#1063,.T.);
#1198=EDGE_LOOP('',(#1197));
#1199=FACE_BOUND('',#1198,.T.);
#1200=ADVANCED_FACE('F693',(#1196,#1199),#1185,.F.);
#1201=CARTESIAN_POINT('',(10.,50.,-2.));
#1202=DIRECTION('',(0.,0.,-1.));
#1203=DIRECTION('',(-1.,0.,0.));
#1204=AXIS2_PLACEMENT_3D('',#1201,#1202,#1203);
#1205=CONICAL_SURFACE('',#1204,4.,0.78539816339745);
#1206=CARTESIAN_POINT('',(7.9,50.,-0.100000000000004));
#1207=CARTESIAN_POINT('',(7.88020833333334,50.,-0.11979166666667));
#1208=CARTESIAN_POINT('',(7.86041666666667,50.,-0.139583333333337));
#1209=CARTESIAN_POINT('',(7.82083333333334,50.,-0.17916666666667));
#1210=CARTESIAN_POINT('',(7.80104166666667,50.,-0.198958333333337));
#1211=CARTESIAN_POINT('',(7.76145833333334,50.,-0.23854166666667));
#1212=CARTESIAN_POINT('',(7.74166666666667,50.,-0.258333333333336));
#1213=CARTESIAN_POINT('',(7.70208333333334,50.,-0.29791666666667));
#1214=CARTESIAN_POINT('',(7.68229166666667,50.,-0.317708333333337));
#1215=CARTESIAN_POINT('',(7.64270833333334,50.,-0.35729166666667));
#1216=CARTESIAN_POINT('',(7.62291666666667,50.,-0.377083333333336));
#1217=CARTESIAN_POINT('',(7.58333333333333,50.,-0.41666666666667));
#1218=CARTESIAN_POINT('',(7.56354166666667,50.,-0.436458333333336));
#1219=CARTESIAN_POINT('',(7.52395833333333,50.,-0.47604166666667));
#1220=CARTESIAN_POINT('',(7.50416666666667,50.,-0.495833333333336));
#1221=CARTESIAN_POINT('',(7.46458333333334,50.,-0.535416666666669));
#1222=CARTESIAN_POINT('',(7.44479166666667,50.,-0.555208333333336));
#1223=CARTESIAN_POINT('',(7.40520833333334,50.,-0.594791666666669));
#1224=CARTESIAN_POINT('',(7.38541666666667,50.,-0.614583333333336));
#1225=CARTESIAN_POINT('',(7.34583333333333,50.,-0.654166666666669));
#1226=CARTESIAN_POINT('',(7.32604166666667,50.,-0.673958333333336));
#1227=CARTESIAN_POINT('',(7.28645833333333,50.,-0.713541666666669));
#1228=CARTESIAN_POINT('',(7.26666666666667,50.,-0.733333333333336));
#1229=CARTESIAN_POINT('',(7.22708333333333,50.,-0.772916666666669));
#1230=CARTESIAN_POINT('',(7.20729166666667,50.,-0.792708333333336));
#1231=CARTESIAN_POINT('',(7.16770833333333,50.,-0.832291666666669));
#1232=CARTESIAN_POINT('',(7.14791666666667,50.,-0.852083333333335));
#1233=CARTESIAN_POINT('',(7.10833333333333,50.,-0.891666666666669));
#1234=CARTESIAN_POINT('',(7.08854166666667,50.,-0.911458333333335));
#1235=CARTESIAN_POINT('',(7.04895833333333,50.,-0.951041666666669));
#1236=CARTESIAN_POINT('',(7.02916666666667,50.,-0.970833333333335));
#1237=CARTESIAN_POINT('',(6.98958333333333,50.,-1.01041666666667));
#1238=CARTESIAN_POINT('',(6.96979166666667,50.,-1.03020833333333));
#1239=CARTESIAN_POINT('',(6.93020833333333,50.,-1.06979166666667));
#1240=CARTESIAN_POINT('',(6.91041666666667,50.,-1.08958333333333));
#1241=CARTESIAN_POINT('',(6.87083333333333,50.,-1.12916666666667));
#1242=CARTESIAN_POINT('',(6.85104166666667,50.,-1.14895833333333));
#1243=CARTESIAN_POINT('',(6.81145833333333,50.,-1.18854166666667));
#1244=CARTESIAN_POINT('',(6.79166666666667,50.,-1.20833333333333));
#1245=CARTESIAN_POINT('',(6.75208333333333,50.,-1.24791666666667));
#1246=CARTESIAN_POINT('',(6.73229166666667,50.,-1.26770833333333));
#1247=CARTESIAN_POINT('',(6.69270833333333,50.,-1.30729166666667));
#1248=CARTESIAN_POINT('',(6.67291666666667,50.,-1.32708333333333));
#1249=CARTESIAN_POINT('',(6.63333333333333,50.,-1.36666666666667));
#1250=CARTESIAN_POINT('',(6.61354166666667,50.,-1.38645833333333));
#1251=CARTESIAN_POINT('',(6.57395833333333,50.,-1.42604166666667));
#1252=CARTESIAN_POINT('',(6.55416666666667,50.,-1.44583333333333));
#1253=CARTESIAN_POINT('',(6.51458333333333,50.,-1.48541666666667));
#1254=CARTESIAN_POINT('',(6.49479166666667,50.,-1.50520833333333));
#1255=CARTESIAN_POINT('',(6.45520833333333,50.,-1.54479166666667));
#1256=CARTESIAN_POINT('',(6.43541666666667,50.,-1.56458333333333));
#1257=CARTESIAN_POINT('',(6.39583333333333,50.,-1.60416666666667));
#1258=CARTESIAN_POINT('',(6.37604166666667,50.,-1.62395833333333));
#1259=CARTESIAN_POINT('',(6.33645833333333,50.,-1.66354166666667));
#1260=CARTESIAN_POINT('',(6.31666666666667,50.,-1.68333333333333));
#1261=CARTESIAN_POINT('',(6.27708333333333,50.,-1.72291666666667));
#1262=CARTESIAN_POINT('',(6.25729166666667,50.,-1.74270833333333));
#1263=CARTESIAN_POINT('',(6.21770833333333,50.,-1.78229166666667));
#1264=CARTESIAN_POINT('',(6.19791666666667,50.,-1.80208333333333));
#1265=CARTESIAN_POINT('',(6.15833333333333,50.,-1.84166666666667));
#1266=CARTESIAN_POINT('',(6.13854166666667,50.,-1.86145833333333));
#1267=CARTESIAN_POINT('',(6.09895833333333,50.,-1.90104166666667));
#1268=CARTESIAN_POINT('',(6.07916666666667,50.,-1.92083333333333));
#1269=CARTESIAN_POINT('',(6.03958333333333,50.,-1.96041666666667));
#1270=CARTESIAN_POINT('',(6.01979166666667,50.,-1.98020833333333));
#1271=CARTESIAN_POINT('',(6.,50.,-2.));
#1272=B_SPLINE_CURVE_WITH_KNOTS('',3,(#1206,#1207,#1208,#1209,#1210,#1211,#1212,#1213,#1214,
#1215,#1216,#1217,#1218,#1219,#1220,#1221,#1222,#1223,#1224,#1225,#1226,#1227,#1228,#1229,#1230,
#1231,#1232,#1233,#1234,#1235,#1236,#1237,#1238,#1239,#1240,#1241,#1242,#1243,#1244,#1245,#1246,
#1247,#1248,#1249,#1250,#1251,#1252,#1253,#1254,#1255,#1256,#1257,#1258,#1259,#1260,#1261,#1262,
#1263,#1264,#1265,#1266,#1267,#1268,#1269,#1270,#1271),.UNSPECIFIED.,.F.,.F.,(4,2,2,2,2,2,2,2,2,
2,2,2,2,2,2,2,2,2,2,2,2,2,2,2,2,2,2,2,2,2,2,2,4),(0.,0.0839689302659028,0.167937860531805,
0.251906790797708,0.33587572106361,0.419844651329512,0.503813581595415,0.587782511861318,
0.67175144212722,0.755720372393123,0.839689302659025,0.923658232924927,1.00762716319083,
1.09159609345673,1.17556502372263,1.25953395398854,1.34350288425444,1.42747181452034,
1.51144074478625,1.59540967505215,1.67937860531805,1.76334753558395,1.84731646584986,
1.93128539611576,2.01525432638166,2.09922325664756,2.18319218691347,2.26716111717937,
2.35113004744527,2.43509897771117,2.51906790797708,2.60303683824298,2.68700576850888),.UNSPECIFIED.);
#1273=EDGE_CURVE('BSEAM696',#1172,#406,#1272,.T.);
#1274=ORIENTED_EDGE('',*,*,#1173,.F.);
#1275=ORIENTED_EDGE('',*,*,#407,.F.);
#1276=ORIENTED_EDGE('',*,*,#1273,.T.);
#1277=ORIENTED_EDGE('',*,*,#1273,.F.);
#1278=EDGE_LOOP('',(#1274,#1276,#1275,#1277));
#1279=FACE_BOUND('',#1278,.T.);
#1280=ADVANCED_FACE('F696',(#1279),#1205,.F.);
#1281=CARTESIAN_POINT('',(60.,10.,-2.));
#1282=DIRECTION('',(0.,0.,-1.));
#1283=DIRECTION('',(-1.,0.,0.));
#1284=AXIS2_PLACEMENT_3D('',#1281,#1282,#1283);
#1285=CONICAL_SURFACE('',#1284,4.,0.78539816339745);
#1286=ORIENTED_EDGE('',*,*,#1193,.F.);
#1287=EDGE_LOOP('',(#1286));
#1288=FACE_BOUND('',#1287,.T.);
#1289=ORIENTED_EDGE('',*,*,#418,.F.);
#1290=EDGE_LOOP('',(#1289));
#1291=FACE_BOUND('',#1290,.T.);
#1292=ADVANCED_FACE('F34',(#1288,#1291),#1285,.F.);
#1293=CARTESIAN_POINT('',(47.5,30.,0.));
#1294=DIRECTION('',(0.,0.,-1.));
#1295=DIRECTION('',(-1.,0.,0.));
#1296=AXIS2_PLACEMENT_3D('',#1293,#1294,#1295);
#1297=CYLINDRICAL_SURFACE('',#1296,1.5);
#1298=ORIENTED_EDGE('',*,*,#1052,.F.);
#1299=EDGE_LOOP('',(#1298));
#1300=FACE_BOUND('',#1299,.T.);
#1301=ORIENTED_EDGE('',*,*,#396,.T.);
#1302=EDGE_LOOP('',(#1301));
#1303=FACE_BOUND('',#1302,.T.);
#1304=ADVANCED_FACE('F688',(#1300,#1303),#1297,.F.);
#1305=CARTESIAN_POINT('',(22.5,30.,0.));
#1306=DIRECTION('',(0.,0.,-1.));
#1307=DIRECTION('',(-1.,0.,0.));
#1308=AXIS2_PLACEMENT_3D('',#1305,#1306,#1307);
#1309=CYLINDRICAL_SURFACE('',#1308,1.5);
#1310=ORIENTED_EDGE('',*,*,#1041,.F.);
#1311=EDGE_LOOP('',(#1310));
#1312=FACE_BOUND('',#1311,.T.);
#1313=ORIENTED_EDGE('',*,*,#385,.T.);
#1314=EDGE_LOOP('',(#1313));
#1315=FACE_BOUND('',#1314,.T.);
#1316=ADVANCED_FACE('F684',(#1312,#1315),#1309,.F.);
#1317=CARTESIAN_POINT('',(44.,25.,0.));
#1318=DIRECTION('',(0.,0.,-1.));
#1319=DIRECTION('',(-1.,0.,0.));
#1320=AXIS2_PLACEMENT_3D('',#1317,#1318,#1319);
#1321=CYLINDRICAL_SURFACE('',#1320,1.);
#1322=ORIENTED_EDGE('',*,*,#317,.T.);
#1323=DIRECTION('',(0.,0.,-1.));
#1324=VECTOR('',#1323,1.);
#1325=CARTESIAN_POINT('',(44.,24.,0.));
#1326=LINE('',#1325,#1324);
#1327=EDGE_CURVE('E838',#980,#316,#1326,.T.);
#1328=ORIENTED_EDGE('',*,*,#1327,.F.);
#1329=ORIENTED_EDGE('',*,*,#981,.F.);
#1330=DIRECTION('',(0.,0.,-1.));
#1331=VECTOR('',#1330,1.);
#1332=CARTESIAN_POINT('',(45.,25.,0.));
#1333=LINE('',#1332,#1331);
#1334=EDGE_CURVE('E835',#971,#314,#1333,.T.);
#1335=ORIENTED_EDGE('',*,*,#1334,.T.);
#1336=EDGE_LOOP('',(#1322,#1328,#1329,#1335));
#1337=FACE_BOUND('',#1336,.T.);
#1338=ADVANCED_FACE('F658',(#1337),#1321,.F.);
#1339=CARTESIAN_POINT('',(45.,35.,0.));
#1340=DIRECTION('',(1.,0.,0.));
#1341=DIRECTION('',(0.,0.,-1.));
#1342=AXIS2_PLACEMENT_3D('',#1339,#1340,#1341);
#1343=PLANE('',#1342);
#1344=ORIENTED_EDGE('',*,*,#325,.T.);
#1345=ORIENTED_EDGE('',*,*,#1334,.F.);
#1346=ORIENTED_EDGE('',*,*,#972,.F.);
#1347=DIRECTION('',(0.,0.,-1.));
#1348=VECTOR('',#1347,1.);
#1349=CARTESIAN_POINT('',(45.,35.,0.));
#1350=LINE('',#1349,#1348);
#1351=EDGE_CURVE('E852',#969,#324,#1350,.T.);
#1352=ORIENTED_EDGE('',*,*,#1351,.T.);
#1353=EDGE_LOOP('',(#1344,#1345,#1346,#1352));
#1354=FACE_BOUND('',#1353,.T.);
#1355=ADVANCED_FACE('F654',(#1354),#1343,.F.);
#1356=CARTESIAN_POINT('',(44.,35.,0.));
#1357=DIRECTION('',(0.,0.,-1.));
#1358=DIRECTION('',(-1.,0.,0.));
#1359=AXIS2_PLACEMENT_3D('',#1356,#1357,#1358);
#1360=CYLINDRICAL_SURFACE('',#1359,1.);
#1361=ORIENTED_EDGE('',*,*,#334,.T.);
#1362=ORIENTED_EDGE('',*,*,#1351,.F.);
#1363=ORIENTED_EDGE('',*,*,#1030,.F.);
#1364=DIRECTION('',(0.,0.,-1.));
#1365=VECTOR('',#1364,1.);
#1366=CARTESIAN_POINT('',(44.,36.,0.));
#1367=LINE('',#1366,#1365);
#1368=EDGE_CURVE('E850',#1022,#333,#1367,.T.);
#1369=ORIENTED_EDGE('',*,*,#1368,.T.);
#1370=EDGE_LOOP('',(#1361,#1362,#1363,#1369));
#1371=FACE_BOUND('',#1370,.T.);
#1372=ADVANCED_FACE('F657',(#1371),#1360,.F.);
#1373=CARTESIAN_POINT('',(44.,36.,0.));
#1374=DIRECTION('',(0.,1.,0.));
#1375=DIRECTION('',(0.,0.,1.));
#1376=AXIS2_PLACEMENT_3D('',#1373,#1374,#1375);
#1377=PLANE('',#1376);
#1378=ORIENTED_EDGE('',*,*,#342,.T.);
#1379=ORIENTED_EDGE('',*,*,#1368,.F.);
#1380=ORIENTED_EDGE('',*,*,#1023,.F.);
#1381=DIRECTION('',(0.,0.,-1.));
#1382=VECTOR('',#1381,1.);
#1383=CARTESIAN_POINT('',(26.,36.,0.));
#1384=LINE('',#1383,#1382);
#1385=EDGE_CURVE('E848',#1014,#341,#1384,.T.);
#1386=ORIENTED_EDGE('',*,*,#1385,.T.);
#1387=EDGE_LOOP('',(#1378,#1379,#1380,#1386));
#1388=FACE_BOUND('',#1387,.T.);
#1389=ADVANCED_FACE('F662',(#1388),#1377,.F.);
#1390=CARTESIAN_POINT('',(26.,35.,0.));
#1391=DIRECTION('',(0.,0.,-1.));
#1392=DIRECTION('',(-1.,0.,0.));
#1393=AXIS2_PLACEMENT_3D('',#1390,#1391,#1392);
#1394=CYLINDRICAL_SURFACE('',#1393,1.);
#1395=ORIENTED_EDGE('',*,*,#351,.T.);
#1396=ORIENTED_EDGE('',*,*,#1385,.F.);
#1397=ORIENTED_EDGE('',*,*,#1015,.F.);
#1398=DIRECTION('',(0.,0.,-1.));
#1399=VECTOR('',#1398,1.);
#1400=CARTESIAN_POINT('',(25.,35.,0.));
#1401=LINE('',#1400,#1399);
#1402=EDGE_CURVE('E846',#1005,#350,#1401,.T.);
#1403=ORIENTED_EDGE('',*,*,#1402,.T.);
#1404=EDGE_LOOP('',(#1395,#1396,#1397,#1403));
#1405=FACE_BOUND('',#1404,.T.);
#1406=ADVANCED_FACE('F666',(#1405),#1394,.F.);
#1407=CARTESIAN_POINT('',(25.,35.,0.));
#1408=DIRECTION('',(-1.,0.,0.));
#1409=DIRECTION('',(0.,0.,1.));
#1410=AXIS2_PLACEMENT_3D('',#1407,#1408,#1409);
#1411=PLANE('',#1410);
#1412=ORIENTED_EDGE('',*,*,#359,.T.);
#1413=ORIENTED_EDGE('',*,*,#1402,.F.);
#1414=ORIENTED_EDGE('',*,*,#1006,.F.);
#1415=DIRECTION('',(0.,0.,-1.));
#1416=VECTOR('',#1415,1.);
#1417=CARTESIAN_POINT('',(25.,25.,0.));
#1418=LINE('',#1417,#1416);
#1419=EDGE_CURVE('E844',#997,#358,#1418,.T.);
#1420=ORIENTED_EDGE('',*,*,#1419,.T.);
#1421=EDGE_LOOP('',(#1412,#1413,#1414,#1420));
#1422=FACE_BOUND('',#1421,.T.);
#1423=ADVANCED_FACE('F670',(#1422),#1411,.F.);
#1424=CARTESIAN_POINT('',(26.,25.,0.));
#1425=DIRECTION('',(0.,0.,-1.));
#1426=DIRECTION('',(-1.,0.,0.));
#1427=AXIS2_PLACEMENT_3D('',#1424,#1425,#1426);
#1428=CYLINDRICAL_SURFACE('',#1427,1.);
#1429=ORIENTED_EDGE('',*,*,#368,.T.);
#1430=ORIENTED_EDGE('',*,*,#1419,.F.);
#1431=ORIENTED_EDGE('',*,*,#998,.F.);
#1432=DIRECTION('',(0.,0.,-1.));
#1433=VECTOR('',#1432,1.);
#1434=CARTESIAN_POINT('',(26.,24.,0.));
#1435=LINE('',#1434,#1433);
#1436=EDGE_CURVE('E841',#988,#367,#1435,.T.);
#1437=ORIENTED_EDGE('',*,*,#1436,.T.);
#1438=EDGE_LOOP('',(#1429,#1430,#1431,#1437));
#1439=FACE_BOUND('',#1438,.T.);
#1440=ADVANCED_FACE('F674',(#1439),#1428,.F.);
#1441=CARTESIAN_POINT('',(44.,24.,0.));
#1442=DIRECTION('',(0.,-1.,0.));
#1443=DIRECTION('',(0.,0.,-1.));
#1444=AXIS2_PLACEMENT_3D('',#1441,#1442,#1443);
#1445=PLANE('',#1444);
#1446=ORIENTED_EDGE('',*,*,#374,.T.);
#1447=ORIENTED_EDGE('',*,*,#1436,.F.);
#1448=ORIENTED_EDGE('',*,*,#989,.F.);
#1449=ORIENTED_EDGE('',*,*,#1327,.T.);
#1450=EDGE_LOOP('',(#1446,#1447,#1448,#1449));
#1451=FACE_BOUND('',#1450,.T.);
#1452=ADVANCED_FACE('F652',(#1451),#1445,.F.);
#1453=CARTESIAN_POINT('',(40.8286421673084,19.281993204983,-1.));
#1454=DIRECTION('',(0.,-1.,0.));
#1455=DIRECTION('',(0.,0.,-1.));
#1456=AXIS2_PLACEMENT_3D('',#1453,#1454,#1455);
#1457=PLANE('',#1456);
#1458=ORIENTED_EDGE('',*,*,#98,.F.);
#1459=DIRECTION('',(0.,0.,-1.));
#1460=VECTOR('',#1459,1.);
#1461=CARTESIAN_POINT('',(40.8286421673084,19.281993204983,-1.));
#1462=LINE('',#1461,#1460);
#1463=CARTESIAN_POINT('',(40.8286421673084,19.281993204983,-1.));
#1464=VERTEX_POINT('',#1463);
#1465=EDGE_CURVE('E928',#1464,#89,#1462,.T.);
#1466=ORIENTED_EDGE('',*,*,#1465,.F.);
#1467=DIRECTION('',(-1.,0.,0.));
#1468=VECTOR('',#1467,1.);
#1469=CARTESIAN_POINT('',(40.8286421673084,19.281993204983,-1.));
#1470=LINE('',#1469,#1468);
#1471=CARTESIAN_POINT('',(39.392744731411,19.281993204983,-1.));
#1472=VERTEX_POINT('',#1471);
#1473=EDGE_CURVE('E606',#1464,#1472,#1470,.T.);
#1474=ORIENTED_EDGE('',*,*,#1473,.T.);
#1475=DIRECTION('',(0.,0.,-1.));
#1476=VECTOR('',#1475,1.);
#1477=CARTESIAN_POINT('',(39.392744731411,19.281993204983,-1.));
#1478=LINE('',#1477,#1476);
#1479=EDGE_CURVE('E879',#1472,#97,#1478,.T.);
#1480=ORIENTED_EDGE('',*,*,#1479,.T.);
#1481=EDGE_LOOP('',(#1458,#1466,#1474,#1480));
#1482=FACE_BOUND('',#1481,.T.);
#1483=ADVANCED_FACE('F648',(#1482),#1457,.T.);
#1484=CARTESIAN_POINT('',(39.392744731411,19.281993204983,-1.));
#1485=DIRECTION('',(1.,0.,0.));
#1486=DIRECTION('',(0.,0.,-1.));
#1487=AXIS2_PLACEMENT_3D('',#1484,#1485,#1486);
#1488=PLANE('',#1487);
#1489=ORIENTED_EDGE('',*,*,#106,.F.);
#1490=ORIENTED_EDGE('',*,*,#1479,.F.);
#1491=DIRECTION('',(0.,-1.,0.));
#1492=VECTOR('',#1491,1.);
#1493=CARTESIAN_POINT('',(39.392744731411,19.281993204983,-1.));
#1494=LINE('',#1493,#1492);
#1495=CARTESIAN_POINT('',(39.392744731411,18.9230188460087,-1.));
#1496=VERTEX_POINT('',#1495);
#1497=EDGE_CURVE('E609',#1472,#1496,#1494,.T.);
#1498=ORIENTED_EDGE('',*,*,#1497,.T.);
#1499=DIRECTION('',(0.,0.,-1.));
#1500=VECTOR('',#1499,1.);
#1501=CARTESIAN_POINT('',(39.392744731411,18.9230188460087,-1.));
#1502=LINE('',#1501,#1500);
#1503=EDGE_CURVE('E904',#1496,#105,#1502,.T.);
#1504=ORIENTED_EDGE('',*,*,#1503,.T.);
#1505=EDGE_LOOP('',(#1489,#1490,#1498,#1504));
#1506=FACE_BOUND('',#1505,.T.);
#1507=ADVANCED_FACE('F644',(#1506),#1488,.T.);
#1508=CARTESIAN_POINT('',(39.392744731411,18.9230188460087,-1.));
#1509=DIRECTION('',(0.,1.,0.));
#1510=DIRECTION('',(0.,0.,1.));
#1511=AXIS2_PLACEMENT_3D('',#1508,#1509,#1510);
#1512=PLANE('',#1511);
#1513=ORIENTED_EDGE('',*,*,#114,.F.);
#1514=ORIENTED_EDGE('',*,*,#1503,.F.);
#1515=DIRECTION('',(1.,0.,0.));
#1516=VECTOR('',#1515,1.);
#1517=CARTESIAN_POINT('',(39.392744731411,18.9230188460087,-1.));
#1518=LINE('',#1517,#1516);
#1519=CARTESIAN_POINT('',(40.5832495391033,18.9230188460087,-1.));
#1520=VERTEX_POINT('',#1519);
#1521=EDGE_CURVE('E612',#1496,#1520,#1518,.T.);
#1522=ORIENTED_EDGE('',*,*,#1521,.T.);
#1523=DIRECTION('',(0.,0.,-1.));
#1524=VECTOR('',#1523,1.);
#1525=CARTESIAN_POINT('',(40.5832495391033,18.9230188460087,-1.));
#1526=LINE('',#1525,#1524);
#1527=EDGE_CURVE('E906',#1520,#113,#1526,.T.);
#1528=ORIENTED_EDGE('',*,*,#1527,.T.);
#1529=EDGE_LOOP('',(#1513,#1514,#1522,#1528));
#1530=FACE_BOUND('',#1529,.T.);
#1531=ADVANCED_FACE('F640',(#1530),#1512,.T.);
#1532=CARTESIAN_POINT('',(40.5832495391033,18.9230188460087,-1.));
#1533=DIRECTION('',(0.979651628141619,0.20070547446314,0.));
#1534=DIRECTION('',(-0.20070547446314,0.979651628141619,0.));
#1535=AXIS2_PLACEMENT_3D('',#1532,#1533,#1534);
#1536=PLANE('',#1535);
#1537=ORIENTED_EDGE('',*,*,#122,.F.);
#1538=ORIENTED_EDGE('',*,*,#1527,.F.);
#1539=DIRECTION('',(0.20070547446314,-0.979651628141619,0.));
#1540=VECTOR('',#1539,1.);
#1541=CARTESIAN_POINT('',(40.5832495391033,18.9230188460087,-1.));
#1542=LINE('',#1541,#1540);
#1543=CARTESIAN_POINT('',(40.7718513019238,18.002445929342,-1.));
#1544=VERTEX_POINT('',#1543);
#1545=EDGE_CURVE('E614',#1520,#1544,#1542,.T.);
#1546=ORIENTED_EDGE('',*,*,#1545,.T.);
#1547=DIRECTION('',(0.,0.,-1.));
#1548=VECTOR('',#1547,1.);
#1549=CARTESIAN_POINT('',(40.7718513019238,18.002445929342,-1.));
#1550=LINE('',#1549,#1548);
#1551=EDGE_CURVE('E908',#1544,#121,#1550,.T.);
#1552=ORIENTED_EDGE('',*,*,#1551,.T.);
#1553=EDGE_LOOP('',(#1537,#1538,#1546,#1552));
#1554=FACE_BOUND('',#1553,.T.);
#1555=ADVANCED_FACE('F635',(#1554),#1536,.T.);
#1556=CARTESIAN_POINT('',(40.7718513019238,18.002445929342,-1.));
#1557=CARTESIAN_POINT('',(40.7347954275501,18.0126762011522,-1.));
#1558=CARTESIAN_POINT('',(40.6630055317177,18.0324957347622,-1.));
#1559=CARTESIAN_POINT('',(40.557045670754,18.0545015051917,-1.));
#1560=CARTESIAN_POINT('',(40.456453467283,18.0677669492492,-1.));
#1561=CARTESIAN_POINT('',(40.3911780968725,18.0695782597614,-1.));
#1562=CARTESIAN_POINT('',(40.3595916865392,18.0704547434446,-1.));
#1563=B_SPLINE_CURVE_WITH_KNOTS('',3,(#1556,#1557,#1558,#1559,#1560,#1561,#1562),.UNSPECIFIED.,
.F.,.F.,(4,1,1,1,4),(0.,0.275068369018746,0.532901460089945,0.773973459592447,1.),.UNSPECIFIED.);
#1564=DIRECTION('',(0.,0.,-1.));
#1565=VECTOR('',#1564,1.);
#1566=SURFACE_OF_LINEAR_EXTRUSION('',#1563,#1565);
#1567=ORIENTED_EDGE('',*,*,#134,.F.);
#1568=ORIENTED_EDGE('',*,*,#1551,.F.);
#1569=CARTESIAN_POINT('',(40.3595916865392,18.0704547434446,-1.));
#1570=VERTEX_POINT('',#1569);
#1571=EDGE_CURVE('E616',#1544,#1570,#1563,.T.);
#1572=ORIENTED_EDGE('',*,*,#1571,.T.);
#1573=DIRECTION('',(0.,0.,-1.));
#1574=VECTOR('',#1573,1.);
#1575=CARTESIAN_POINT('',(40.3595916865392,18.0704547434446,-1.));
#1576=LINE('',#1575,#1574);
#1577=EDGE_CURVE('E910',#1570,#133,#1576,.T.);
#1578=ORIENTED_EDGE('',*,*,#1577,.T.);
#1579=EDGE_LOOP('',(#1567,#1568,#1572,#1578));
#1580=FACE_BOUND('',#1579,.T.);
#1581=ADVANCED_FACE('F630',(#1580),#1566,.T.);
#1582=CARTESIAN_POINT('',(40.3595916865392,18.0704547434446,-1.));
#1583=CARTESIAN_POINT('',(40.320507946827,18.0696088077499,-1.));
#1584=CARTESIAN_POINT('',(40.2436595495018,18.0679454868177,-1.));
#1585=CARTESIAN_POINT('',(40.1312206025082,18.0519736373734,-0.999999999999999));
#1586=CARTESIAN_POINT('',(40.0238877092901,18.0268337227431,-1.));
#1587=CARTESIAN_POINT('',(39.9218853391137,17.9917132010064,-1.));
#1588=CARTESIAN_POINT('',(39.8250247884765,17.9468034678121,-1.));
#1589=CARTESIAN_POINT('',(39.7341972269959,17.8907035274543,-1.));
#1590=CARTESIAN_POINT('',(39.6480393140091,17.8251701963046,-1.));
#1591=CARTESIAN_POINT('',(39.5680967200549,17.749825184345,-1.));
#1592=CARTESIAN_POINT('',(39.4955724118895,17.6669035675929,-1.));
#1593=CARTESIAN_POINT('',(39.4318064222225,17.5777456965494,-1.));
#1594=CARTESIAN_POINT('',(39.3776438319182,17.4832180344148,-0.999999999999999));
#1595=CARTESIAN_POINT('',(39.3340830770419,17.3824174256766,-1.));
#1596=CARTESIAN_POINT('',(39.2992987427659,17.2764582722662,-1.));
#1597=CARTESIAN_POINT('',(39.2761467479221,17.164225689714,-1.));
#1598=CARTESIAN_POINT('',(39.2607300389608,17.0467775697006,-1.));
#1599=CARTESIAN_POINT('',(39.2590076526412,16.9664729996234,-1.));
#1600=CARTESIAN_POINT('',(39.2581293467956,16.9255228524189,-1.));
#1601=B_SPLINE_CURVE_WITH_KNOTS('',3,(#1582,#1583,#1584,#1585,#1586,#1587,#1588,#1589,#1590,
#1591,#1592,#1593,#1594,#1595,#1596,#1597,#1598,#1599,#1600),.UNSPECIFIED.,.F.,.F.,(4,1,1,1,1,1,
1,1,1,1,1,1,1,1,1,1,4),(0.,0.0658076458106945,0.129394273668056,0.190894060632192,
0.251281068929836,0.310814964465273,0.370370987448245,0.430768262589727,0.492881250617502,
0.555103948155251,0.616067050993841,0.677256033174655,0.738259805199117,0.800762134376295,
0.864777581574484,0.931045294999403,1.),.UNSPECIFIED.);
#1602=DIRECTION('',(0.,0.,-1.));
#1603=VECTOR('',#1602,1.);
#1604=SURFACE_OF_LINEAR_EXTRUSION('',#1601,#1603);
#1605=ORIENTED_EDGE('',*,*,#158,.F.);
#1606=ORIENTED_EDGE('',*,*,#1577,.F.);
#1607=CARTESIAN_POINT('',(39.2581293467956,16.9255228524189,-1.));
#1608=VERTEX_POINT('',#1607);
#1609=EDGE_CURVE('E621',#1570,#1608,#1601,.T.);
#1610=ORIENTED_EDGE('',*,*,#1609,.T.);
#1611=DIRECTION('',(0.,0.,-1.));
#1612=VECTOR('',#1611,1.);
#1613=CARTESIAN_POINT('',(39.2581293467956,16.9255228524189,-1.));
#1614=LINE('',#1613,#1612);
#1615=EDGE_CURVE('E912',#1608,#157,#1614,.T.);
#1616=ORIENTED_EDGE('',*,*,#1615,.T.);
#1617=EDGE_LOOP('',(#1605,#1606,#1610,#1616));
#1618=FACE_BOUND('',#1617,.T.);
#1619=ADVANCED_FACE('F634',(#1618),#1604,.T.);
#1620=CARTESIAN_POINT('',(39.2581293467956,16.9255228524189,-1.));
#1621=CARTESIAN_POINT('',(39.2587944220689,16.897000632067,-1.));
#1622=CARTESIAN_POINT('',(39.2601155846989,16.8403416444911,-1.));
#1623=CARTESIAN_POINT('',(39.2668341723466,16.7561974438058,-1.));
#1624=CARTESIAN_POINT('',(39.2797698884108,16.6738346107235,-1.));
#1625=CARTESIAN_POINT('',(39.2971376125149,16.5932422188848,-1.));
#1626=CARTESIAN_POINT('',(39.3196800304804,16.5145728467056,-1.));
#1627=CARTESIAN_POINT('',(39.3469690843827,16.4376013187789,-1.));
#1628=CARTESIAN_POINT('',(39.3803651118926,16.3628067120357,-1.));
#1629=CARTESIAN_POINT('',(39.4169964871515,16.2894813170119,-0.999999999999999));
#1630=CARTESIAN_POINT('',(39.4582429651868,16.2192828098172,-1.));
#1631=CARTESIAN_POINT('',(39.5040214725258,16.1536338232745,-1.));
#1632=CARTESIAN_POINT('',(39.5523869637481,16.0915495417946,-1.));
#1633=CARTESIAN_POINT('',(39.6044283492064,16.0336958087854,-1.));
#1634=CARTESIAN_POINT('',(39.660629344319,15.9804527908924,-1.));
#1635=CARTESIAN_POINT('',(39.7203093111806,15.9315045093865,-1.));
#1636=CARTESIAN_POINT('',(39.7829920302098,15.8860231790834,-1.));
#1637=CARTESIAN_POINT('',(39.8496472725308,15.8458549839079,-1.));
#1638=CARTESIAN_POINT('',(39.9187897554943,15.8088920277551,-1.));
#1639=CARTESIAN_POINT('',(39.9914179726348,15.7785684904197,-1.));
#1640=CARTESIAN_POINT('',(40.0658786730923,15.7514579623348,-1.));
#1641=CARTESIAN_POINT('',(40.1432435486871,15.7298484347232,-1.));
#1642=CARTESIAN_POINT('',(40.2233373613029,15.7129158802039,-1.));
#1643=CARTESIAN_POINT('',(40.306292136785,15.7014152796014,-1.));
#1644=CARTESIAN_POINT('',(40.3916728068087,15.6930388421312,-1.));
#1645=CARTESIAN_POINT('',(40.4495478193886,15.6925144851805,-1.));
#1646=CARTESIAN_POINT('',(40.4787823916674,15.6922496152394,-1.));
#1647=B_SPLINE_CURVE_WITH_KNOTS('',3,(#1620,#1621,#1622,#1623,#1624,#1625,#1626,#1627,#1628,
#1629,#1630,#1631,#1632,#1633,#1634,#1635,#1636,#1637,#1638,#1639,#1640,#1641,#1642,#1643,#1644,
#1645,#1646),.UNSPECIFIED.,.F.,.F.,(4,1,1,1,1,1,1,1,1,1,1,1,1,1,1,1,1,1,1,1,1,1,1,1,4),(0.,
0.0440144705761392,0.0874341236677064,0.130118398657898,0.172553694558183,0.21455475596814,
0.256298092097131,0.29843822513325,0.340849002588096,0.382715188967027,0.423924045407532,
0.464246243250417,0.504073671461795,0.543861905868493,0.583566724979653,0.623094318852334,
0.663229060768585,0.703551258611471,0.743937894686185,0.784541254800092,0.825750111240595,
0.867757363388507,0.910745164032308,0.954914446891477,1.),.UNSPECIFIED.);
#1648=DIRECTION('',(0.,0.,-1.));
#1649=VECTOR('',#1648,1.);
#1650=SURFACE_OF_LINEAR_EXTRUSION('',#1647,#1649);
#1651=ORIENTED_EDGE('',*,*,#190,.F.);
#1652=ORIENTED_EDGE('',*,*,#1615,.F.);
#1653=CARTESIAN_POINT('',(40.4787823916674,15.6922496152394,-1.));
#1654=VERTEX_POINT('',#1653);
#1655=EDGE_CURVE('E1066',#1608,#1654,#1647,.T.);
#1656=ORIENTED_EDGE('',*,*,#1655,.T.);
#1657=DIRECTION('',(0.,0.,-1.));
#1658=VECTOR('',#1657,1.);
#1659=CARTESIAN_POINT('',(40.4787823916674,15.6922496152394,-1.));
#1660=LINE('',#1659,#1658);
#1661=EDGE_CURVE('E914',#1654,#189,#1660,.T.);
#1662=ORIENTED_EDGE('',*,*,#1661,.T.);
#1663=EDGE_LOOP('',(#1651,#1652,#1656,#1662));
#1664=FACE_BOUND('',#1663,.T.);
#1665=ADVANCED_FACE('F1077',(#1664),#1650,.T.);
#1666=CARTESIAN_POINT('',(40.4787823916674,15.6922496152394,-1.));
#1667=CARTESIAN_POINT('',(40.5136565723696,15.6929404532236,-1.));
#1668=CARTESIAN_POINT('',(40.5822674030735,15.694299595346,-1.));
#1669=CARTESIAN_POINT('',(40.682787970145,15.7085180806,-1.));
#1670=CARTESIAN_POINT('',(40.7795025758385,15.7288819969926,-1.));
#1671=CARTESIAN_POINT('',(40.8716326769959,15.7595182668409,-1.));
#1672=CARTESIAN_POINT('',(40.9600039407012,15.7979055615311,-1.));
#1673=CARTESIAN_POINT('',(41.04342665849,15.8464217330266,-1.));
#1674=CARTESIAN_POINT('',(41.1240324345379,15.9014008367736,-0.999999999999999));
#1675=CARTESIAN_POINT('',(41.1985444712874,15.9662811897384,-1.));
#1676=CARTESIAN_POINT('',(41.267700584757,16.0371968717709,-1.));
#1677=CARTESIAN_POINT('',(41.3296070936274,16.1141545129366,-1.));
#1678=CARTESIAN_POINT('',(41.384740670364,16.1958839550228,-1.));
#1679=CARTESIAN_POINT('',(41.4322184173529,16.2827821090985,-1.));
#1680=CARTESIAN_POINT('',(41.4727164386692,16.3746206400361,-1.));
#1681=CARTESIAN_POINT('',(41.504531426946,16.4717436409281,-1.));
#1682=CARTESIAN_POINT('',(41.5302097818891,16.5736436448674,-1.));
#1683=CARTESIAN_POINT('',(41.5410732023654,16.643797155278,-0.999999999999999));
#1684=CARTESIAN_POINT('',(41.5465908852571,16.6794291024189,-1.));
#1685=B_SPLINE_CURVE_WITH_KNOTS('',3,(#1666,#1667,#1668,#1669,#1670,#1671,#1672,#1673,#1674,
#1675,#1676,#1677,#1678,#1679,#1680,#1681,#1682,#1683,#1684),.UNSPECIFIED.,.F.,.F.,(4,1,1,1,1,1,
1,1,1,1,1,1,1,1,1,1,4),(0.,0.0654211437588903,0.128708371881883,0.190236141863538,
0.250724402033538,0.310637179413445,0.370766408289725,0.431614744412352,0.493522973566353,
0.555883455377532,0.61734236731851,0.678668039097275,0.740711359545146,0.802985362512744,
0.866802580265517,0.932347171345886,1.),.UNSPECIFIED.);
#1686=DIRECTION('',(0.,0.,-1.));
#1687=VECTOR('',#1686,1.);
#1688=SURFACE_OF_LINEAR_EXTRUSION('',#1685,#1687);
#1689=ORIENTED_EDGE('',*,*,#214,.F.);
#1690=ORIENTED_EDGE('',*,*,#1661,.F.);
#1691=CARTESIAN_POINT('',(41.5465908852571,16.6794291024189,-1.));
#1692=VERTEX_POINT('',#1691);
#1693=EDGE_CURVE('E1062',#1654,#1692,#1685,.T.);
#1694=ORIENTED_EDGE('',*,*,#1693,.T.);
#1695=DIRECTION('',(0.,0.,-1.));
#1696=VECTOR('',#1695,1.);
#1697=CARTESIAN_POINT('',(41.5465908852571,16.6794291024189,-1.));
#1698=LINE('',#1697,#1696);
#1699=EDGE_CURVE('E916',#1692,#213,#1698,.T.);
#1700=ORIENTED_EDGE('',*,*,#1699,.T.);
#1701=EDGE_LOOP('',(#1689,#1690,#1694,#1700));
#1702=FACE_BOUND('',#1701,.T.);
#1703=ADVANCED_FACE('F1074',(#1702),#1688,.T.);
#1704=CARTESIAN_POINT('',(41.5465908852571,16.6794291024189,-1.));
#1705=DIRECTION('',(0.,-1.,0.));
#1706=DIRECTION('',(0.,0.,-1.));
#1707=AXIS2_PLACEMENT_3D('',#1704,#1705,#1706);
#1708=PLANE('',#1707);
#1709=ORIENTED_EDGE('',*,*,#222,.F.);
#1710=ORIENTED_EDGE('',*,*,#1699,.F.);
#1711=DIRECTION('',(-1.,0.,0.));
#1712=VECTOR('',#1711,1.);
#1713=CARTESIAN_POINT('',(41.5465908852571,16.6794291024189,-1.));
#1714=LINE('',#1713,#1712);
#1715=CARTESIAN_POINT('',(41.2324883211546,16.6794291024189,-1.));
#1716=VERTEX_POINT('',#1715);
#1717=EDGE_CURVE('E1057',#1692,#1716,#1714,.T.);
#1718=ORIENTED_EDGE('',*,*,#1717,.T.);
#1719=DIRECTION('',(0.,0.,-1.));
#1720=VECTOR('',#1719,1.);
#1721=CARTESIAN_POINT('',(41.2324883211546,16.6794291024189,-1.));
#1722=LINE('',#1721,#1720);
#1723=EDGE_CURVE('E918',#1716,#221,#1722,.T.);
#1724=ORIENTED_EDGE('',*,*,#1723,.T.);
#1725=EDGE_LOOP('',(#1709,#1710,#1718,#1724));
#1726=FACE_BOUND('',#1725,.T.);
#1727=ADVANCED_FACE('F1076',(#1726),#1708,.T.);
#1728=CARTESIAN_POINT('',(41.2324883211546,16.6794291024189,-1.));
#1729=CARTESIAN_POINT('',(41.2247597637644,16.6460526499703,-1.));
#1730=CARTESIAN_POINT('',(41.2099050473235,16.5819012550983,-0.999999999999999));
#1731=CARTESIAN_POINT('',(41.1772992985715,16.4917699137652,-1.));
#1732=CARTESIAN_POINT('',(41.1374334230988,16.4114506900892,-1.));
#1733=CARTESIAN_POINT('',(41.0900290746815,16.3398811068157,-1.));
#1734=CARTESIAN_POINT('',(41.0334790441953,16.2774721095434,-1.));
#1735=CARTESIAN_POINT('',(40.9689496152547,16.2218550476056,-1.));
#1736=CARTESIAN_POINT('',(40.8966018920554,16.1716799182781,-1.));
#1737=CARTESIAN_POINT('',(40.8162086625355,16.1298571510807,-1.));
#1738=CARTESIAN_POINT('',(40.7313955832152,16.0941883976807,-1.));
#1739=CARTESIAN_POINT('',(40.6426283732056,16.0704367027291,-1.));
#1740=CARTESIAN_POINT('',(40.5523240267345,16.0537358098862,-1.));
#1741=CARTESIAN_POINT('',(40.491245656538,16.0520640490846,-1.));
#1742=CARTESIAN_POINT('',(40.4605532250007,16.0512239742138,-1.));
#1743=B_SPLINE_CURVE_WITH_KNOTS('',3,(#1728,#1729,#1730,#1731,#1732,#1733,#1734,#1735,#1736,
#1737,#1738,#1739,#1740,#1741,#1742),.UNSPECIFIED.,.F.,.F.,(4,1,1,1,1,1,1,1,1,1,1,1,4),(0.,
0.0946872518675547,0.181994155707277,0.264376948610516,0.342179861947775,0.418617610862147,
0.496509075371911,0.577369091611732,0.661510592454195,0.746732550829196,0.831257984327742,
0.915205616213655,1.),.UNSPECIFIED.);
#1744=DIRECTION('',(0.,0.,-1.));
#1745=VECTOR('',#1744,1.);
#1746=SURFACE_OF_LINEAR_EXTRUSION('',#1743,#1745);
#1747=ORIENTED_EDGE('',*,*,#242,.F.);
#1748=ORIENTED_EDGE('',*,*,#1723,.F.);
#1749=CARTESIAN_POINT('',(40.4605532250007,16.0512239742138,-1.));
#1750=VERTEX_POINT('',#1749);
#1751=EDGE_CURVE('E1049',#1716,#1750,#1743,.T.);
#1752=ORIENTED_EDGE('',*,*,#1751,.T.);
#1753=DIRECTION('',(0.,0.,-1.));
#1754=VECTOR('',#1753,1.);
#1755=CARTESIAN_POINT('',(40.4605532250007,16.0512239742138,-1.));
#1756=LINE('',#1755,#1754);
#1757=EDGE_CURVE('E920',#1750,#241,#1756,.T.);
#1758=ORIENTED_EDGE('',*,*,#1757,.T.);
#1759=EDGE_LOOP('',(#1747,#1748,#1752,#1758));
#1760=FACE_BOUND('',#1759,.T.);
#1761=ADVANCED_FACE('F1041',(#1760),#1746,.T.);
#1762=CARTESIAN_POINT('',(40.4605532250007,16.0512239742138,-1.));
#1763=CARTESIAN_POINT('',(40.4305947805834,16.0520447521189,-1.));
#1764=CARTESIAN_POINT('',(40.3716063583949,16.05366087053,-1.));
#1765=CARTESIAN_POINT('',(40.2847949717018,16.0660998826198,-1.));
#1766=CARTESIAN_POINT('',(40.2009820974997,16.0852574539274,-1.));
#1767=CARTESIAN_POINT('',(40.1209947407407,16.1139273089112,-1.));
#1768=CARTESIAN_POINT('',(40.0434332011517,16.148772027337,-1.));
#1769=CARTESIAN_POINT('',(39.9702594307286,16.1934871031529,-1.));
#1770=CARTESIAN_POINT('',(39.8993565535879,16.2449471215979,-1.));
#1771=CARTESIAN_POINT('',(39.8329284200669,16.3039037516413,-1.));
#1772=CARTESIAN_POINT('',(39.7720889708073,16.3688734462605,-1.));
#1773=CARTESIAN_POINT('',(39.7183328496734,16.4383508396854,-1.));
#1774=CARTESIAN_POINT('',(39.6735559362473,16.5124676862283,-1.));
#1775=CARTESIAN_POINT('',(39.6358218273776,16.5899408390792,-1.));
#1776=CARTESIAN_POINT('',(39.6071685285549,16.6716193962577,-1.));
#1777=CARTESIAN_POINT('',(39.5867275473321,16.7571205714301,-1.));
#1778=CARTESIAN_POINT('',(39.5747244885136,16.8466555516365,-1.));
#1779=CARTESIAN_POINT('',(39.5730733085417,16.9077248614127,-1.));
#1780=CARTESIAN_POINT('',(39.5722319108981,16.9388441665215,-1.));
#1781=B_SPLINE_CURVE_WITH_KNOTS('',3,(#1762,#1763,#1764,#1765,#1766,#1767,#1768,#1769,#1770,
#1771,#1772,#1773,#1774,#1775,#1776,#1777,#1778,#1779,#1780),.UNSPECIFIED.,.F.,.F.,(4,1,1,1,1,1,
1,1,1,1,1,1,1,1,1,1,4),(0.,0.0642072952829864,0.12642468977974,0.187680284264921,
0.248216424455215,0.308305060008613,0.369660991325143,0.43169855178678,0.495946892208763,
0.559758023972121,0.622295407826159,0.683910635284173,0.745092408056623,0.806740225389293,
0.869086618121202,0.9332900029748,1.),.UNSPECIFIED.);
#1782=DIRECTION('',(0.,0.,-1.));
#1783=VECTOR('',#1782,1.);
#1784=SURFACE_OF_LINEAR_EXTRUSION('',#1781,#1783);
#1785=ORIENTED_EDGE('',*,*,#266,.F.);
#1786=ORIENTED_EDGE('',*,*,#1757,.F.);
#1787=CARTESIAN_POINT('',(39.5722319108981,16.9388441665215,-1.));
#1788=VERTEX_POINT('',#1787);
#1789=EDGE_CURVE('E1045',#1750,#1788,#1781,.T.);
#1790=ORIENTED_EDGE('',*,*,#1789,.T.);
#1791=DIRECTION('',(0.,0.,-1.));
#1792=VECTOR('',#1791,1.);
#1793=CARTESIAN_POINT('',(39.5722319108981,16.9388441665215,-1.));
#1794=LINE('',#1793,#1792);
#1795=EDGE_CURVE('E922',#1788,#265,#1794,.T.);
#1796=ORIENTED_EDGE('',*,*,#1795,.T.);
#1797=EDGE_LOOP('',(#1785,#1786,#1790,#1796));
#1798=FACE_BOUND('',#1797,.T.);
#1799=ADVANCED_FACE('F1037',(#1798),#1784,.T.);
#1800=CARTESIAN_POINT('',(39.5722319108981,16.9388441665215,-1.));
#1801=CARTESIAN_POINT('',(39.5728903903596,16.9669199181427,-1.));
#1802=CARTESIAN_POINT('',(39.574179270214,17.0218742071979,-1.));
#1803=CARTESIAN_POINT('',(39.5847098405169,17.1022734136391,-1.));
#1804=CARTESIAN_POINT('',(39.6030268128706,17.1783464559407,-1.));
#1805=CARTESIAN_POINT('',(39.6284506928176,17.2504606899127,-1.));
#1806=CARTESIAN_POINT('',(39.6607302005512,17.3186841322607,-1.));
#1807=CARTESIAN_POINT('',(39.70017651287,17.3830871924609,-1.));
#1808=CARTESIAN_POINT('',(39.7475299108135,17.4428210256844,-1.));
#1809=CARTESIAN_POINT('',(39.8016217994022,17.4979135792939,-1.));
#1810=CARTESIAN_POINT('',(39.8608798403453,17.548758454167,-1.));
#1811=CARTESIAN_POINT('',(39.9263235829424,17.5921025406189,-1.));
#1812=CARTESIAN_POINT('',(39.9965835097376,17.6285664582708,-1.));
#1813=CARTESIAN_POINT('',(40.0708131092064,17.6600344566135,-1.));
#1814=CARTESIAN_POINT('',(40.1507780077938,17.6826352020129,-1.));
#1815=CARTESIAN_POINT('',(40.2348946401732,17.699603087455,-1.));
#1816=CARTESIAN_POINT('',(40.3240713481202,17.7094184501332,-1.));
#1817=CARTESIAN_POINT('',(40.3850420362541,17.710780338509,-1.));
#1818=CARTESIAN_POINT('',(40.4163825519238,17.7114803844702,-1.));
#1819=B_SPLINE_CURVE_WITH_KNOTS('',3,(#1800,#1801,#1802,#1803,#1804,#1805,#1806,#1807,#1808,
#1809,#1810,#1811,#1812,#1813,#1814,#1815,#1816,#1817,#1818),.UNSPECIFIED.,.F.,.F.,(4,1,1,1,1,1,
1,1,1,1,1,1,1,1,1,1,4),(0.,0.0653513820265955,0.127916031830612,0.1883602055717,
0.247216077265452,0.305630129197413,0.36376983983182,0.42266091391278,0.482687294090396,
0.543300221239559,0.604117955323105,0.664964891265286,0.727413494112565,0.791467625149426,
0.858055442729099,0.927036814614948,1.),.UNSPECIFIED.);
#1820=DIRECTION('',(0.,0.,-1.));
#1821=VECTOR('',#1820,1.);
#1822=SURFACE_OF_LINEAR_EXTRUSION('',#1819,#1821);
#1823=ORIENTED_EDGE('',*,*,#290,.F.);
#1824=ORIENTED_EDGE('',*,*,#1795,.F.);
#1825=CARTESIAN_POINT('',(40.4163825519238,17.7114803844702,-1.));
#1826=VERTEX_POINT('',#1825);
#1827=EDGE_CURVE('E1018',#1788,#1826,#1819,.T.);
#1828=ORIENTED_EDGE('',*,*,#1827,.T.);
#1829=DIRECTION('',(0.,0.,-1.));
#1830=VECTOR('',#1829,1.);
#1831=CARTESIAN_POINT('',(40.4163825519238,17.7114803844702,-1.));
#1832=LINE('',#1831,#1830);
#1833=EDGE_CURVE('E924',#1826,#289,#1832,.T.);
#1834=ORIENTED_EDGE('',*,*,#1833,.T.);
#1835=EDGE_LOOP('',(#1823,#1824,#1828,#1834));
#1836=FACE_BOUND('',#1835,.T.);
#1837=ADVANCED_FACE('F1032',(#1836),#1822,.T.);
#1838=CARTESIAN_POINT('',(40.4163825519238,17.7114803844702,-1.));
#1839=CARTESIAN_POINT('',(40.4435114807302,17.7108997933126,-1.));
#1840=CARTESIAN_POINT('',(40.4995258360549,17.7097010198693,-1.));
#1841=CARTESIAN_POINT('',(40.5854486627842,17.7008745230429,-0.999999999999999));
#1842=CARTESIAN_POINT('',(40.6757403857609,17.6866352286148,-1.));
#1843=CARTESIAN_POINT('',(40.7700548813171,17.6670489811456,-1.));
#1844=CARTESIAN_POINT('',(40.8686753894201,17.641417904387,-1.));
#1845=CARTESIAN_POINT('',(40.9713937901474,17.6107034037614,-1.));
#1846=CARTESIAN_POINT('',(41.0784260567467,17.5739814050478,-1.));
#1847=CARTESIAN_POINT('',(41.1505437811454,17.5462491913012,-1.));
#1848=CARTESIAN_POINT('',(41.1876165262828,17.531993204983,-1.));
#1849=B_SPLINE_CURVE_WITH_KNOTS('',3,(#1838,#1839,#1840,#1841,#1842,#1843,#1844,#1845,#1846,
#1847,#1848),.UNSPECIFIED.,.F.,.F.,(4,1,1,1,1,1,1,1,4),(0.,0.102203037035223,0.211023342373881,
0.325099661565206,0.446502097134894,0.573787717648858,0.708900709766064,0.850357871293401,1.),.UNSPECIFIED.);
#1850=DIRECTION('',(0.,0.,-1.));
#1851=VECTOR('',#1850,1.);
#1852=SURFACE_OF_LINEAR_EXTRUSION('',#1849,#1851);
#1853=ORIENTED_EDGE('',*,*,#304,.F.);
#1854=ORIENTED_EDGE('',*,*,#1833,.F.);
#1855=CARTESIAN_POINT('',(41.1876165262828,17.531993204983,-1.));
#1856=VERTEX_POINT('',#1855);
#1857=EDGE_CURVE('E1013',#1826,#1856,#1849,.T.);
#1858=ORIENTED_EDGE('',*,*,#1857,.T.);
#1859=DIRECTION('',(0.,0.,-1.));
#1860=VECTOR('',#1859,1.);
#1861=CARTESIAN_POINT('',(41.1876165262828,17.531993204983,-1.));
#1862=LINE('',#1861,#1860);
#1863=EDGE_CURVE('E926',#1856,#87,#1862,.T.);
#1864=ORIENTED_EDGE('',*,*,#1863,.T.);
#1865=EDGE_LOOP('',(#1853,#1854,#1858,#1864));
#1866=FACE_BOUND('',#1865,.T.);
#1867=ADVANCED_FACE('F1027',(#1866),#1852,.T.);
#1868=CARTESIAN_POINT('',(41.1876165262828,17.531993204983,-1.));
#1869=DIRECTION('',(-0.97960270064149,-0.200944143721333,0.));
#1870=DIRECTION('',(0.200944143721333,-0.97960270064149,0.));
#1871=AXIS2_PLACEMENT_3D('',#1868,#1869,#1870);
#1872=PLANE('',#1871);
#1873=ORIENTED_EDGE('',*,*,#90,.F.);
#1874=ORIENTED_EDGE('',*,*,#1863,.F.);
#1875=DIRECTION('',(-0.200944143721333,0.97960270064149,0.));
#1876=VECTOR('',#1875,1.);
#1877=CARTESIAN_POINT('',(41.1876165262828,17.531993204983,-1.));
#1878=LINE('',#1877,#1876);
#1879=EDGE_CURVE('E931',#1856,#1464,#1878,.T.);
#1880=ORIENTED_EDGE('',*,*,#1879,.T.);
#1881=ORIENTED_EDGE('',*,*,#1465,.T.);
#1882=EDGE_LOOP('',(#1873,#1874,#1880,#1881));
#1883=FACE_BOUND('',#1882,.T.);
#1884=ADVANCED_FACE('F1031',(#1883),#1872,.T.);
#1885=CARTESIAN_POINT('',(40.5680991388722,18.0512729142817,-1.));
#1886=DIRECTION('',(0.,0.,-1.));
#1887=DIRECTION('',(0.,1.,0.));
#1888=AXIS2_PLACEMENT_3D('',#1885,#1886,#1887);
#1889=PLANE('',#1888);
#1890=ORIENTED_EDGE('',*,*,#1473,.F.);
#1891=ORIENTED_EDGE('',*,*,#1879,.F.);
#1892=ORIENTED_EDGE('',*,*,#1857,.F.);
#1893=ORIENTED_EDGE('',*,*,#1827,.F.);
#1894=ORIENTED_EDGE('',*,*,#1789,.F.);
#1895=ORIENTED_EDGE('',*,*,#1751,.F.);
#1896=ORIENTED_EDGE('',*,*,#1717,.F.);
#1897=ORIENTED_EDGE('',*,*,#1693,.F.);
#1898=ORIENTED_EDGE('',*,*,#1655,.F.);
#1899=ORIENTED_EDGE('',*,*,#1609,.F.);
#1900=ORIENTED_EDGE('',*,*,#1571,.F.);
#1901=ORIENTED_EDGE('',*,*,#1545,.F.);
#1902=ORIENTED_EDGE('',*,*,#1521,.F.);
#1903=ORIENTED_EDGE('',*,*,#1497,.F.);
#1904=EDGE_LOOP('',(#1890,#1891,#1892,#1893,#1894,#1895,#1896,#1897,#1898,#1899,#1900,#1901,
#1902,#1903));
#1905=FACE_BOUND('',#1904,.T.);
#1906=ADVANCED_FACE('F1102',(#1905),#1889,.T.);
#1907=CARTESIAN_POINT('',(37.0587102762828,17.2683714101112,-1.));
#1908=DIRECTION('',(0.825496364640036,0.564407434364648,0.));
#1909=DIRECTION('',(-0.564407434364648,0.825496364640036,0.));
#1910=AXIS2_PLACEMENT_3D('',#1907,#1908,#1909);
#1911=PLANE('',#1910);
#1912=ORIENTED_EDGE('',*,*,#520,.F.);
#1913=DIRECTION('',(0.,0.,-1.));
#1914=VECTOR('',#1913,1.);
#1915=CARTESIAN_POINT('',(37.0587102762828,17.2683714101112,-1.));
#1916=LINE('',#1915,#1914);
#1917=CARTESIAN_POINT('',(37.0587102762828,17.2683714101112,-1.));
#1918=VERTEX_POINT('',#1917);
#1919=EDGE_CURVE('E528',#1918,#511,#1916,.T.);
#1920=ORIENTED_EDGE('',*,*,#1919,.F.);
#1921=DIRECTION('',(0.564407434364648,-0.825496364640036,0.));
#1922=VECTOR('',#1921,1.);
#1923=CARTESIAN_POINT('',(37.0587102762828,17.2683714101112,-1.));
#1924=LINE('',#1923,#1922);
#1925=CARTESIAN_POINT('',(38.1363344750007,15.6922496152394,-1.));
#1926=VERTEX_POINT('',#1925);
#1927=EDGE_CURVE('E584',#1918,#1926,#1924,.T.);
#1928=ORIENTED_EDGE('',*,*,#1927,.T.);
#1929=DIRECTION('',(0.,0.,-1.));
#1930=VECTOR('',#1929,1.);
#1931=CARTESIAN_POINT('',(38.1363344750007,15.6922496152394,-1.));
#1932=LINE('',#1931,#1930);
#1933=EDGE_CURVE('E602',#1926,#519,#1932,.T.);
#1934=ORIENTED_EDGE('',*,*,#1933,.T.);
#1935=EDGE_LOOP('',(#1912,#1920,#1928,#1934));
#1936=FACE_BOUND('',#1935,.T.);
#1937=ADVANCED_FACE('F1135',(#1936),#1911,.T.);
#1938=CARTESIAN_POINT('',(38.1363344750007,15.6922496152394,-1.));
#1939=DIRECTION('',(-0.570997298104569,0.820951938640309,0.));
#1940=DIRECTION('',(-0.820951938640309,-0.570997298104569,0.));
#1941=AXIS2_PLACEMENT_3D('',#1938,#1939,#1940);
#1942=PLANE('',#1941);
#1943=ORIENTED_EDGE('',*,*,#528,.F.);
#1944=ORIENTED_EDGE('',*,*,#1933,.F.);
#1945=DIRECTION('',(0.820951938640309,0.570997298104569,0.));
#1946=VECTOR('',#1945,1.);
#1947=CARTESIAN_POINT('',(38.1363344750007,15.6922496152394,-1.));
#1948=LINE('',#1947,#1946);
#1949=CARTESIAN_POINT('',(38.3873360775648,15.8668289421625,-1.));
#1950=VERTEX_POINT('',#1949);
#1951=EDGE_CURVE('E1212',#1926,#1950,#1948,.T.);
#1952=ORIENTED_EDGE('',*,*,#1951,.T.);
#1953=DIRECTION('',(0.,0.,-1.));
#1954=VECTOR('',#1953,1.);
#1955=CARTESIAN_POINT('',(38.3873360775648,15.8668289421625,-1.));
#1956=LINE('',#1955,#1954);
#1957=EDGE_CURVE('E600',#1950,#527,#1956,.T.);
#1958=ORIENTED_EDGE('',*,*,#1957,.T.);
#1959=EDGE_LOOP('',(#1943,#1944,#1952,#1958));
#1960=FACE_BOUND('',#1959,.T.);
#1961=ADVANCED_FACE('F1139',(#1960),#1942,.T.);
#1962=CARTESIAN_POINT('',(38.3873360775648,15.8668289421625,-1.));
#1963=DIRECTION('',(-0.825357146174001,-0.564610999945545,0.));
#1964=DIRECTION('',(0.564610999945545,-0.825357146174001,0.));
#1965=AXIS2_PLACEMENT_3D('',#1962,#1963,#1964);
#1966=PLANE('',#1965);
#1967=ORIENTED_EDGE('',*,*,#536,.F.);
#1968=ORIENTED_EDGE('',*,*,#1957,.F.);
#1969=DIRECTION('',(-0.564610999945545,0.825357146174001,0.));
#1970=VECTOR('',#1969,1.);
#1971=CARTESIAN_POINT('',(38.3873360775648,15.8668289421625,-1.));
#1972=LINE('',#1971,#1970);
#1973=CARTESIAN_POINT('',(37.4141790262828,17.2894050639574,-1.));
#1974=VERTEX_POINT('',#1973);
#1975=EDGE_CURVE('E1163',#1950,#1974,#1972,.T.);
#1976=ORIENTED_EDGE('',*,*,#1975,.T.);
#1977=DIRECTION('',(0.,0.,-1.));
#1978=VECTOR('',#1977,1.);
#1979=CARTESIAN_POINT('',(37.4141790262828,17.2894050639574,-1.));
#1980=LINE('',#1979,#1978);
#1981=EDGE_CURVE('E598',#1974,#535,#1980,.T.);
#1982=ORIENTED_EDGE('',*,*,#1981,.T.);
#1983=EDGE_LOOP('',(#1967,#1968,#1976,#1982));
#1984=FACE_BOUND('',#1983,.T.);
#1985=ADVANCED_FACE('F1145',(#1984),#1966,.T.);
#1986=CARTESIAN_POINT('',(37.4141790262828,17.2894050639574,-1.));
#1987=CARTESIAN_POINT('',(37.4762697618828,17.2818120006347,-1.));
#1988=CARTESIAN_POINT('',(37.5985298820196,17.2668608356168,-1.));
#1989=CARTESIAN_POINT('',(37.7216669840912,17.2641141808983,-1.));
#1990=CARTESIAN_POINT('',(37.7822679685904,17.2627624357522,-1.));
#1991=B_SPLINE_CURVE_WITH_KNOTS('',3,(#1986,#1987,#1988,#1989,#1990),.UNSPECIFIED.,.F.,.F.,(4,1,
4),(0.,0.50785763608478,1.),.UNSPECIFIED.);
#1992=DIRECTION('',(0.,0.,-1.));
#1993=VECTOR('',#1992,1.);
#1994=SURFACE_OF_LINEAR_EXTRUSION('',#1991,#1993);
#1995=ORIENTED_EDGE('',*,*,#546,.F.);
#1996=ORIENTED_EDGE('',*,*,#1981,.F.);
#1997=CARTESIAN_POINT('',(37.7822679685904,17.2627624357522,-1.));
#1998=VERTEX_POINT('',#1997);
#1999=EDGE_CURVE('E1157',#1974,#1998,#1991,.T.);
#2000=ORIENTED_EDGE('',*,*,#1999,.T.);
#2001=DIRECTION('',(0.,0.,-1.));
#2002=VECTOR('',#2001,1.);
#2003=CARTESIAN_POINT('',(37.7822679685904,17.2627624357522,-1.));
#2004=LINE('',#2003,#2002);
#2005=EDGE_CURVE('E596',#1998,#545,#2004,.T.);
#2006=ORIENTED_EDGE('',*,*,#2005,.T.);
#2007=EDGE_LOOP('',(#1995,#1996,#2000,#2006));
#2008=FACE_BOUND('',#2007,.T.);
#2009=ADVANCED_FACE('F1149',(#2008),#1994,.T.);
#2010=CARTESIAN_POINT('',(37.7822679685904,17.2627624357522,-1.));
#2011=CARTESIAN_POINT('',(37.8190100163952,17.2637035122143,-1.));
#2012=CARTESIAN_POINT('',(37.8911314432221,17.2655507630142,-1.));
#2013=CARTESIAN_POINT('',(37.9971630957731,17.2801925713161,-1.));
#2014=CARTESIAN_POINT('',(38.0990486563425,17.3027426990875,-1.));
#2015=CARTESIAN_POINT('',(38.1965180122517,17.3363914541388,-1.));
#2016=CARTESIAN_POINT('',(38.2899375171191,17.3782096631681,-1.));
#2017=CARTESIAN_POINT('',(38.3791032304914,17.4300666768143,-1.));
#2018=CARTESIAN_POINT('',(38.4638951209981,17.4910729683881,-1.));
#2019=CARTESIAN_POINT('',(38.5434025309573,17.5609059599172,-1.));
#2020=CARTESIAN_POINT('',(38.6157142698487,17.6375840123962,-1.));
#2021=CARTESIAN_POINT('',(38.6801375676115,17.7187396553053,-1.));
#2022=CARTESIAN_POINT('',(38.7336786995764,17.8053156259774,-1.));
#2023=CARTESIAN_POINT('',(38.7781552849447,17.8955458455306,-1.));
#2024=CARTESIAN_POINT('',(38.8118857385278,17.9907271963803,-1.));
#2025=CARTESIAN_POINT('',(38.8364482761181,18.089776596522,-1.));
#2026=CARTESIAN_POINT('',(38.8515706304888,18.1933882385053,-1.));
#2027=CARTESIAN_POINT('',(38.8533697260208,18.2639133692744,-1.));
#2028=CARTESIAN_POINT('',(38.8542831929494,18.2997215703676,-1.));
#2029=B_SPLINE_CURVE_WITH_KNOTS('',3,(#2010,#2011,#2012,#2013,#2014,#2015,#2016,#2017,#2018,
#2019,#2020,#2021,#2022,#2023,#2024,#2025,#2026,#2027,#2028),.UNSPECIFIED.,.F.,.F.,(4,1,1,1,1,1,
1,1,1,1,1,1,1,1,1,1,4),(0.,0.066294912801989,0.130131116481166,0.192862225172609,
0.254360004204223,0.315909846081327,0.377338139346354,0.44020526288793,0.504175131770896,
0.56803363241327,0.63022772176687,0.690861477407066,0.751421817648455,0.811465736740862,
0.872750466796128,0.935390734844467,1.),.UNSPECIFIED.);
#2030=DIRECTION('',(0.,0.,-1.));
#2031=VECTOR('',#2030,1.);
#2032=SURFACE_OF_LINEAR_EXTRUSION('',#2029,#2031);
#2033=ORIENTED_EDGE('',*,*,#570,.F.);
#2034=ORIENTED_EDGE('',*,*,#2005,.F.);
#2035=CARTESIAN_POINT('',(38.8542831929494,18.2997215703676,-1.));
#2036=VERTEX_POINT('',#2035);
#2037=EDGE_CURVE('E1162',#1998,#2036,#2029,.T.);
#2038=ORIENTED_EDGE('',*,*,#2037,.T.);
#2039=DIRECTION('',(0.,0.,-1.));
#2040=VECTOR('',#2039,1.);
#2041=CARTESIAN_POINT('',(38.8542831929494,18.2997215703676,-1.));
#2042=LINE('',#2041,#2040);
#2043=EDGE_CURVE('E594',#2036,#569,#2042,.T.);
#2044=ORIENTED_EDGE('',*,*,#2043,.T.);
#2045=EDGE_LOOP('',(#2033,#2034,#2038,#2044));
#2046=FACE_BOUND('',#2045,.T.);
#2047=ADVANCED_FACE('F1154',(#2046),#2032,.T.);
#2048=CARTESIAN_POINT('',(38.8542831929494,18.2997215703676,-1.));
#2049=CARTESIAN_POINT('',(38.8525487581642,18.3486902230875,-1.));
#2050=CARTESIAN_POINT('',(38.8491444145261,18.4448057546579,-1.));
#2051=CARTESIAN_POINT('',(38.8217458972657,18.5852395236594,-1.));
#2052=CARTESIAN_POINT('',(38.7766855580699,18.7180260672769,-1.));
#2053=CARTESIAN_POINT('',(38.7138571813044,18.8428162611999,-1.));
#2054=CARTESIAN_POINT('',(38.6347224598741,18.9578150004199,-1.));
#2055=CARTESIAN_POINT('',(38.5396138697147,19.0614236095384,-1.));
#2056=CARTESIAN_POINT('',(38.4291099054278,19.1521684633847,-1.));
#2057=CARTESIAN_POINT('',(38.305727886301,19.2301725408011,-1.));
#2058=CARTESIAN_POINT('',(38.1723748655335,19.2929075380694,-1.));
#2059=CARTESIAN_POINT('',(38.0327062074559,19.3391468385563,-1.));
#2060=CARTESIAN_POINT('',(37.8877920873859,19.3663455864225,-1.));
#2061=CARTESIAN_POINT('',(37.7896244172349,19.3699314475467,-1.));
#2062=CARTESIAN_POINT('',(37.7402006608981,19.3717367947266,-1.));
#2063=B_SPLINE_CURVE_WITH_KNOTS('',3,(#2048,#2049,#2050,#2051,#2052,#2053,#2054,#2055,#2056,
#2057,#2058,#2059,#2060,#2061,#2062),.UNSPECIFIED.,.F.,.F.,(4,1,1,1,1,1,1,1,1,1,1,1,4),(0.,
0.0852490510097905,0.167326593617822,0.248175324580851,0.328829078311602,0.409908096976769,
0.490584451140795,0.57299348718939,0.658264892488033,0.744221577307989,0.829060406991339,
0.913938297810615,1.),.UNSPECIFIED.);
#2064=DIRECTION('',(0.,0.,-1.));
#2065=VECTOR('',#2064,1.);
#2066=SURFACE_OF_LINEAR_EXTRUSION('',#2063,#2065);
#2067=ORIENTED_EDGE('',*,*,#590,.F.);
#2068=ORIENTED_EDGE('',*,*,#2043,.F.);
#2069=CARTESIAN_POINT('',(37.7402006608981,19.3717367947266,-1.));
#2070=VERTEX_POINT('',#2069);
#2071=EDGE_CURVE('E1171',#2036,#2070,#2063,.T.);
#2072=ORIENTED_EDGE('',*,*,#2071,.T.);
#2073=DIRECTION('',(0.,0.,-1.));
#2074=VECTOR('',#2073,1.);
#2075=CARTESIAN_POINT('',(37.7402006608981,19.3717367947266,-1.));
#2076=LINE('',#2075,#2074);
#2077=EDGE_CURVE('E592',#2070,#589,#2076,.T.);
#2078=ORIENTED_EDGE('',*,*,#2077,.T.);
#2079=EDGE_LOOP('',(#2067,#2068,#2072,#2078));
#2080=FACE_BOUND('',#2079,.T.);
#2081=ADVANCED_FACE('F1181',(#2080),#2066,.T.);
#2082=CARTESIAN_POINT('',(37.7402006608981,19.3717367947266,-1.));
#2083=CARTESIAN_POINT('',(37.691712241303,19.3699066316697,-1.));
#2084=CARTESIAN_POINT('',(37.5959036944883,19.3662904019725,-1.));
#2085=CARTESIAN_POINT('',(37.4550146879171,19.3398064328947,-1.));
#2086=CARTESIAN_POINT('',(37.3200736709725,19.2951697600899,-1.));
#2087=CARTESIAN_POINT('',(37.1918286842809,19.2334851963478,-1.));
#2088=CARTESIAN_POINT('',(37.0730892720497,19.1561642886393,-1.));
#2089=CARTESIAN_POINT('',(36.9663134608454,19.0640297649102,-1.));
#2090=CARTESIAN_POINT('',(36.8739379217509,18.9570242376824,-1.));
#2091=CARTESIAN_POINT('',(36.7961140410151,18.8377357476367,-1.));
#2092=CARTESIAN_POINT('',(36.7336440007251,18.7095687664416,-1.));
#2093=CARTESIAN_POINT('',(36.6885717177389,18.5757848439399,-1.));
#2094=CARTESIAN_POINT('',(36.6608260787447,18.437346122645,-1.));
#2095=CARTESIAN_POINT('',(36.6573297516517,18.3435516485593,-1.));
#2096=CARTESIAN_POINT('',(36.6555652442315,18.2962159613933,-1.));
#2097=B_SPLINE_CURVE_WITH_KNOTS('',3,(#2082,#2083,#2084,#2085,#2086,#2087,#2088,#2089,#2090,
#2091,#2092,#2093,#2094,#2095,#2096),.UNSPECIFIED.,.F.,.F.,(4,1,1,1,1,1,1,1,1,1,1,1,4),(0.,
0.0855321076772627,0.169003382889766,0.25194324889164,0.335682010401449,0.419408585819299,
0.501264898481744,0.583702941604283,0.668000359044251,0.751918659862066,0.834597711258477,
0.916525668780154,1.),.UNSPECIFIED.);
#2098=DIRECTION('',(0.,0.,-1.));
#2099=VECTOR('',#2098,1.);
#2100=SURFACE_OF_LINEAR_EXTRUSION('',#2097,#2099);
#2101=ORIENTED_EDGE('',*,*,#608,.F.);
#2102=ORIENTED_EDGE('',*,*,#2077,.F.);
#2103=CARTESIAN_POINT('',(36.6555652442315,18.2962159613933,-1.));
#2104=VERTEX_POINT('',#2103);
#2105=EDGE_CURVE('E529',#2070,#2104,#2097,.T.);
#2106=ORIENTED_EDGE('',*,*,#2105,.T.);
#2107=DIRECTION('',(0.,0.,-1.));
#2108=VECTOR('',#2107,1.);
#2109=CARTESIAN_POINT('',(36.6555652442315,18.2962159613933,-1.));
#2110=LINE('',#2109,#2108);
#2111=EDGE_CURVE('E590',#2104,#509,#2110,.T.);
#2112=ORIENTED_EDGE('',*,*,#2111,.T.);
#2113=EDGE_LOOP('',(#2101,#2102,#2106,#2112));
#2114=FACE_BOUND('',#2113,.T.);
#2115=ADVANCED_FACE('F519',(#2114),#2100,.T.);
#2116=CARTESIAN_POINT('',(36.6555652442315,18.2962159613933,-1.));
#2117=CARTESIAN_POINT('',(36.6567436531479,18.2594721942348,-1.));
#2118=CARTESIAN_POINT('',(36.65913376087,18.1849466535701,-1.));
#2119=CARTESIAN_POINT('',(36.6758700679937,18.0717163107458,-1.));
#2120=CARTESIAN_POINT('',(36.7042902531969,17.9562650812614,-1.));
#2121=CARTESIAN_POINT('',(36.736541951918,17.8585434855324,-1.));
#2122=CARTESIAN_POINT('',(36.7676741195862,17.7778350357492,-1.));
#2123=CARTESIAN_POINT('',(36.7969752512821,17.7140834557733,-1.));
#2124=CARTESIAN_POINT('',(36.8294874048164,17.6469821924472,-1.));
#2125=CARTESIAN_POINT('',(36.8674061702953,17.5772348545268,-1.));
#2126=CARTESIAN_POINT('',(36.9081684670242,17.5039523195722,-1.));
#2127=CARTESIAN_POINT('',(36.9542277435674,17.4278696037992,-1.));
#2128=CARTESIAN_POINT('',(37.0045333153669,17.3488846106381,-1.));
#2129=CARTESIAN_POINT('',(37.0403630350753,17.2956375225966,-1.));
#2130=CARTESIAN_POINT('',(37.0587102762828,17.2683714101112,-1.));
#2131=B_SPLINE_CURVE_WITH_KNOTS('',3,(#2116,#2117,#2118,#2119,#2120,#2121,#2122,#2123,#2124,
#2125,#2126,#2127,#2128,#2129,#2130),.UNSPECIFIED.,.F.,.F.,(4,1,1,1,1,1,1,1,1,1,1,1,4),(0.,
0.0983199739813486,0.19941747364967,0.305602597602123,0.416162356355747,0.474582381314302,
0.537006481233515,0.603857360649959,0.674089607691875,0.749416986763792,0.828253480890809,
0.912054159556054,1.),.UNSPECIFIED.);
#2132=DIRECTION('',(0.,0.,-1.));
#2133=VECTOR('',#2132,1.);
#2134=SURFACE_OF_LINEAR_EXTRUSION('',#2131,#2133);
#2135=ORIENTED_EDGE('',*,*,#512,.F.);
#2136=ORIENTED_EDGE('',*,*,#2111,.F.);
#2137=EDGE_CURVE('E523',#2104,#1918,#2131,.T.);
#2138=ORIENTED_EDGE('',*,*,#2137,.T.);
#2139=ORIENTED_EDGE('',*,*,#1919,.T.);
#2140=EDGE_LOOP('',(#2135,#2136,#2138,#2139));
#2141=FACE_BOUND('',#2140,.T.);
#2142=ADVANCED_FACE('F514',(#2141),#2134,.T.);
#2143=CARTESIAN_POINT('',(37.5977850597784,17.2699822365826,-1.));
#2144=DIRECTION('',(0.,0.,-1.));
#2145=DIRECTION('',(0.,1.,0.));
#2146=AXIS2_PLACEMENT_3D('',#2143,#2144,#2145);
#2147=PLANE('',#2146);
#2148=CARTESIAN_POINT('',(37.7563264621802,19.0127624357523,-1.));
#2149=CARTESIAN_POINT('',(37.7829906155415,19.0119856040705,-1.));
#2150=CARTESIAN_POINT('',(37.8353054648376,19.0104614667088,-1.));
#2151=CARTESIAN_POINT('',(37.9123696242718,19.0015102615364,-1.));
#2152=CARTESIAN_POINT('',(37.9862307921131,18.9851667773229,-1.));
#2153=CARTESIAN_POINT('',(38.0573724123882,18.9627345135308,-1.));
#2154=CARTESIAN_POINT('',(38.1256608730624,18.9338229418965,-1.));
#2155=CARTESIAN_POINT('',(38.1910327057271,18.898802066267,-1.));
#2156=CARTESIAN_POINT('',(38.253107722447,18.8570274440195,-1.));
#2157=CARTESIAN_POINT('',(38.3112864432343,18.8096326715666,-1.));
#2158=CARTESIAN_POINT('',(38.3653843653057,18.758545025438,-1.));
#2159=CARTESIAN_POINT('',(38.4115098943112,18.7027715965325,-1.));
#2160=CARTESIAN_POINT('',(38.4511037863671,18.6451240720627,-1.));
#2161=CARTESIAN_POINT('',(38.483978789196,18.5849055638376,-1.));
#2162=CARTESIAN_POINT('',(38.5089813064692,18.5217192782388,-0.999999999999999));
#2163=CARTESIAN_POINT('',(38.5276033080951,18.4560233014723,-1.));
#2164=CARTESIAN_POINT('',(38.5381914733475,18.3874742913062,-1.));
#2165=CARTESIAN_POINT('',(38.5395110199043,18.3408893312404,-1.));
#2166=CARTESIAN_POINT('',(38.5401806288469,18.3172496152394,-1.));
#2167=B_SPLINE_CURVE_WITH_KNOTS('',3,(#2148,#2149,#2150,#2151,#2152,#2153,#2154,#2155,#2156,
#2157,#2158,#2159,#2160,#2161,#2162,#2163,#2164,#2165,#2166),.UNSPECIFIED.,.F.,.F.,(4,1,1,1,1,1,
1,1,1,1,1,1,1,1,1,1,4),(0.,0.0687118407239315,0.134812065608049,0.19953759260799,
0.263334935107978,0.326747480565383,0.390328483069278,0.454125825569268,0.519203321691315,
0.583510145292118,0.645497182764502,0.705289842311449,0.763487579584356,0.821856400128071,
0.880004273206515,0.939107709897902,1.),.UNSPECIFIED.);
#2168=CARTESIAN_POINT('',(37.7563264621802,19.0127624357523,-1.));
#2169=VERTEX_POINT('',#2168);
#2170=CARTESIAN_POINT('',(38.5401806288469,18.3172496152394,-1.));
#2171=VERTEX_POINT('',#2170);
#2172=EDGE_CURVE('E1218',#2169,#2171,#2167,.T.);
#2173=ORIENTED_EDGE('',*,*,#2172,.F.);
#2174=CARTESIAN_POINT('',(36.969667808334,18.3172496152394,-1.));
#2175=CARTESIAN_POINT('',(36.9703374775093,18.3408892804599,-1.));
#2176=CARTESIAN_POINT('',(36.9716571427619,18.3874741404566,-1.));
#2177=CARTESIAN_POINT('',(36.9822444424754,18.4560238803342,-1.));
#2178=CARTESIAN_POINT('',(37.0008696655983,18.5217171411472,-1.));
#2179=CARTESIAN_POINT('',(37.0258601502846,18.5849135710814,-1.));
#2180=CARTESIAN_POINT('',(37.0587803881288,18.6450939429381,-1.));
#2181=CARTESIAN_POINT('',(37.0982838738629,18.7030138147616,-1.));
#2182=CARTESIAN_POINT('',(37.1452163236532,18.7583059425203,-1.));
#2183=CARTESIAN_POINT('',(37.1992188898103,18.8096699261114,-1.));
#2184=CARTESIAN_POINT('',(37.2574534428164,18.8570178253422,-1.));
#2185=CARTESIAN_POINT('',(37.3195139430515,18.8988039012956,-1.));
#2186=CARTESIAN_POINT('',(37.3848888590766,18.9338250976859,-0.999999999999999));
#2187=CARTESIAN_POINT('',(37.4531793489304,18.9627240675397,-1.));
#2188=CARTESIAN_POINT('',(37.5245276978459,18.9852758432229,-1.));
#2189=CARTESIAN_POINT('',(37.5988916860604,19.0014932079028,-1.));
#2190=CARTESIAN_POINT('',(37.6766470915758,19.0104649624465,-1.));
#2191=CARTESIAN_POINT('',(37.7294283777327,19.0119868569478,-1.));
#2192=CARTESIAN_POINT('',(37.7563264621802,19.0127624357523,-1.));
#2193=B_SPLINE_CURVE_WITH_KNOTS('',3,(#2174,#2175,#2176,#2177,#2178,#2179,#2180,#2181,#2182,
#2183,#2184,#2185,#2186,#2187,#2188,#2189,#2190,#2191,#2192),.UNSPECIFIED.,.F.,.F.,(4,1,1,1,1,1,
1,1,1,1,1,1,1,1,1,1,4),(0.,0.060760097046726,0.11973522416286,0.177756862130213,
0.235998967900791,0.294070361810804,0.353733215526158,0.415972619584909,0.480139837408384,
0.545076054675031,0.608734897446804,0.672177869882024,0.735452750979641,0.799111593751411,
0.864283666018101,0.930837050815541,1.),.UNSPECIFIED.);
#2194=CARTESIAN_POINT('',(36.969667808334,18.3172496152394,-1.));
#2195=VERTEX_POINT('',#2194);
#2196=EDGE_CURVE('E1258',#2195,#2169,#2193,.T.);
#2197=ORIENTED_EDGE('',*,*,#2196,.F.);
#2198=CARTESIAN_POINT('',(37.7240748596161,17.6217367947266,-1.));
#2199=CARTESIAN_POINT('',(37.6962408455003,17.6224971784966,-1.));
#2200=CARTESIAN_POINT('',(37.642057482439,17.6239773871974,-1.));
#2201=CARTESIAN_POINT('',(37.5626801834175,17.6329866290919,-1.));
#2202=CARTESIAN_POINT('',(37.4877559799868,17.648960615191,-1.));
#2203=CARTESIAN_POINT('',(37.4170847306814,17.6718803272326,-1.));
#2204=CARTESIAN_POINT('',(37.3499578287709,17.6995369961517,-1.));
#2205=CARTESIAN_POINT('',(37.2874415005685,17.7347489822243,-1.));
#2206=CARTESIAN_POINT('',(37.2294834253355,17.7767656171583,-1.));
#2207=CARTESIAN_POINT('',(37.1756954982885,17.8239756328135,-1.));
#2208=CARTESIAN_POINT('',(37.1279314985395,17.8764262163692,-1.));
#2209=CARTESIAN_POINT('',(37.0853884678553,17.9313233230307,-1.));
#2210=CARTESIAN_POINT('',(37.0492279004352,17.9889079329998,-1.));
#2211=CARTESIAN_POINT('',(37.0206646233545,18.0499011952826,-1.));
#2212=CARTESIAN_POINT('',(36.9971800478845,18.1128184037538,-1.));
#2213=CARTESIAN_POINT('',(36.9809620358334,18.1786727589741,-1.));
#2214=CARTESIAN_POINT('',(36.9719777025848,18.2471211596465,-1.));
#2215=CARTESIAN_POINT('',(36.9704461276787,18.2936198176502,-1.));
#2216=CARTESIAN_POINT('',(36.969667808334,18.3172496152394,-1.));
#2217=B_SPLINE_CURVE_WITH_KNOTS('',3,(#2198,#2199,#2200,#2201,#2202,#2203,#2204,#2205,#2206,
#2207,#2208,#2209,#2210,#2211,#2212,#2213,#2214,#2215,#2216),.UNSPECIFIED.,.F.,.F.,(4,1,1,1,1,1,
1,1,1,1,1,1,1,1,1,1,4),(0.,0.0727129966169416,0.1415474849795,0.208362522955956,
0.272461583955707,0.335389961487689,0.397711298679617,0.459383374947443,0.522098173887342,
0.584314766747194,0.644391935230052,0.703345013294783,0.761508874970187,0.820030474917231,
0.878517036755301,0.938264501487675,1.),.UNSPECIFIED.);
#2218=CARTESIAN_POINT('',(37.7240748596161,17.6217367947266,-1.));
#2219=VERTEX_POINT('',#2218);
#2220=EDGE_CURVE('E493',#2219,#2195,#2217,.T.);
#2221=ORIENTED_EDGE('',*,*,#2220,.F.);
#2222=CARTESIAN_POINT('',(38.5401806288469,18.3172496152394,-1.));
#2223=CARTESIAN_POINT('',(38.5395747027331,18.2936014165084,-1.));
#2224=CARTESIAN_POINT('',(38.5383797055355,18.2469628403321,-1.));
#2225=CARTESIAN_POINT('',(38.5268519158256,18.1784364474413,-1.));
#2226=CARTESIAN_POINT('',(38.5075736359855,18.1127482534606,-1.));
#2227=CARTESIAN_POINT('',(38.4817542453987,18.0492595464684,-1.));
#2228=CARTESIAN_POINT('',(38.4477526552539,17.9885876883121,-1.));
#2229=CARTESIAN_POINT('',(38.4060288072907,17.9310203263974,-1.));
#2230=CARTESIAN_POINT('',(38.3571232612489,17.875904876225,-0.999999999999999));
#2231=CARTESIAN_POINT('',(38.3016897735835,17.8240976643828,-1.));
#2232=CARTESIAN_POINT('',(38.2410216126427,17.7765454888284,-1.));
#2233=CARTESIAN_POINT('',(38.1762248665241,17.7350151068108,-1.));
#2234=CARTESIAN_POINT('',(38.1084150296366,17.6999426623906,-0.999999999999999));
#2235=CARTESIAN_POINT('',(38.0373533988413,17.6718012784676,-1.));
#2236=CARTESIAN_POINT('',(37.9635665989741,17.6491896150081,-1.));
#2237=CARTESIAN_POINT('',(37.88639146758,17.6330160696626,-1.));
#2238=CARTESIAN_POINT('',(37.8060832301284,17.624063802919,-1.));
#2239=CARTESIAN_POINT('',(37.7516732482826,17.6225199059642,-1.));
#2240=CARTESIAN_POINT('',(37.7240748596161,17.6217367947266,-1.));
#2241=B_SPLINE_CURVE_WITH_KNOTS('',3,(#2222,#2223,#2224,#2225,#2226,#2227,#2228,#2229,#2230,
#2231,#2232,#2233,#2234,#2235,#2236,#2237,#2238,#2239,#2240),.UNSPECIFIED.,.F.,.F.,(4,1,1,1,1,1,
1,1,1,1,1,1,1,1,1,1,4),(0.,0.0595395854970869,0.117422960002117,0.17444044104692,
0.231733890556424,0.28972197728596,0.349200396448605,0.41051553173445,0.475080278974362,
0.540094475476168,0.604444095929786,0.668696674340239,0.732110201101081,0.796739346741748,
0.862905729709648,0.930461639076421,1.),.UNSPECIFIED.);
#2242=EDGE_CURVE('E487',#2171,#2219,#2241,.T.);
#2243=ORIENTED_EDGE('',*,*,#2242,.F.);
#2244=EDGE_LOOP('',(#2173,#2197,#2221,#2243));
#2245=FACE_BOUND('',#2244,.T.);
#2246=ORIENTED_EDGE('',*,*,#1927,.F.);
#2247=ORIENTED_EDGE('',*,*,#2137,.F.);
#2248=ORIENTED_EDGE('',*,*,#2105,.F.);
#2249=ORIENTED_EDGE('',*,*,#2071,.F.);
#2250=ORIENTED_EDGE('',*,*,#2037,.F.);
#2251=ORIENTED_EDGE('',*,*,#1999,.F.);
#2252=ORIENTED_EDGE('',*,*,#1975,.F.);
#2253=ORIENTED_EDGE('',*,*,#1951,.F.);
#2254=EDGE_LOOP('',(#2246,#2247,#2248,#2249,#2250,#2251,#2252,#2253));
#2255=FACE_BOUND('',#2254,.T.);
#2256=ADVANCED_FACE('F508',(#2245,#2255),#2147,.T.);
#2257=DIRECTION('',(0.,0.,-1.));
#2258=VECTOR('',#2257,1.);
#2259=SURFACE_OF_LINEAR_EXTRUSION('',#2241,#2258);
#2260=CARTESIAN_POINT('',(38.5401806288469,18.3172496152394,-2.));
#2261=CARTESIAN_POINT('',(38.5395747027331,18.2936014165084,-2.));
#2262=CARTESIAN_POINT('',(38.5383797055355,18.2469628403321,-2.));
#2263=CARTESIAN_POINT('',(38.5268519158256,18.1784364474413,-2.));
#2264=CARTESIAN_POINT('',(38.5075736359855,18.1127482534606,-2.));
#2265=CARTESIAN_POINT('',(38.4817542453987,18.0492595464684,-2.));
#2266=CARTESIAN_POINT('',(38.4477526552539,17.9885876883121,-2.));
#2267=CARTESIAN_POINT('',(38.4060288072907,17.9310203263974,-2.));
#2268=CARTESIAN_POINT('',(38.3571232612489,17.875904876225,-2.));
#2269=CARTESIAN_POINT('',(38.3016897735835,17.8240976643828,-2.));
#2270=CARTESIAN_POINT('',(38.2410216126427,17.7765454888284,-2.));
#2271=CARTESIAN_POINT('',(38.1762248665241,17.7350151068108,-2.));
#2272=CARTESIAN_POINT('',(38.1084150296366,17.6999426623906,-2.));
#2273=CARTESIAN_POINT('',(38.0373533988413,17.6718012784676,-2.));
#2274=CARTESIAN_POINT('',(37.9635665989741,17.6491896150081,-2.));
#2275=CARTESIAN_POINT('',(37.88639146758,17.6330160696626,-2.));
#2276=CARTESIAN_POINT('',(37.8060832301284,17.624063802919,-2.));
#2277=CARTESIAN_POINT('',(37.7516732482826,17.6225199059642,-2.));
#2278=CARTESIAN_POINT('',(37.7240748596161,17.6217367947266,-2.));
#2279=B_SPLINE_CURVE_WITH_KNOTS('',3,(#2260,#2261,#2262,#2263,#2264,#2265,#2266,#2267,#2268,
#2269,#2270,#2271,#2272,#2273,#2274,#2275,#2276,#2277,#2278),.UNSPECIFIED.,.F.,.F.,(4,1,1,1,1,1,
1,1,1,1,1,1,1,1,1,1,4),(0.,0.0595395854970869,0.117422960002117,0.17444044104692,
0.231733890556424,0.28972197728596,0.349200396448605,0.41051553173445,0.475080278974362,
0.540094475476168,0.604444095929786,0.668696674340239,0.732110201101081,0.796739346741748,
0.862905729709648,0.930461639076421,1.),.UNSPECIFIED.);
#2280=CARTESIAN_POINT('',(38.5401806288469,18.3172496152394,-2.));
#2281=VERTEX_POINT('',#2280);
#2282=CARTESIAN_POINT('',(37.7240748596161,17.6217367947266,-2.));
#2283=VERTEX_POINT('',#2282);
#2284=EDGE_CURVE('E486',#2281,#2283,#2279,.T.);
#2285=ORIENTED_EDGE('',*,*,#2284,.F.);
#2286=DIRECTION('',(0.,0.,-1.));
#2287=VECTOR('',#2286,1.);
#2288=CARTESIAN_POINT('',(38.5401806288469,18.3172496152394,-1.));
#2289=LINE('',#2288,#2287);
#2290=EDGE_CURVE('E541',#2171,#2281,#2289,.T.);
#2291=ORIENTED_EDGE('',*,*,#2290,.F.);
#2292=ORIENTED_EDGE('',*,*,#2242,.T.);
#2293=DIRECTION('',(0.,0.,-1.));
#2294=VECTOR('',#2293,1.);
#2295=CARTESIAN_POINT('',(37.7240748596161,17.6217367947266,-1.));
#2296=LINE('',#2295,#2294);
#2297=EDGE_CURVE('E1215',#2219,#2283,#2296,.T.);
#2298=ORIENTED_EDGE('',*,*,#2297,.T.);
#2299=EDGE_LOOP('',(#2285,#2291,#2292,#2298));
#2300=FACE_BOUND('',#2299,.T.);
#2301=ADVANCED_FACE('F503',(#2300),#2259,.T.);
#2302=DIRECTION('',(0.,0.,-1.));
#2303=VECTOR('',#2302,1.);
#2304=SURFACE_OF_LINEAR_EXTRUSION('',#2167,#2303);
#2305=CARTESIAN_POINT('',(37.7563264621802,19.0127624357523,-2.));
#2306=CARTESIAN_POINT('',(37.7829906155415,19.0119856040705,-2.));
#2307=CARTESIAN_POINT('',(37.8353054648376,19.0104614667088,-2.));
#2308=CARTESIAN_POINT('',(37.9123696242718,19.0015102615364,-2.));
#2309=CARTESIAN_POINT('',(37.9862307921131,18.9851667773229,-2.));
#2310=CARTESIAN_POINT('',(38.0573724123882,18.9627345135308,-2.));
#2311=CARTESIAN_POINT('',(38.1256608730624,18.9338229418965,-2.));
#2312=CARTESIAN_POINT('',(38.1910327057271,18.898802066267,-2.));
#2313=CARTESIAN_POINT('',(38.253107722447,18.8570274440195,-2.));
#2314=CARTESIAN_POINT('',(38.3112864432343,18.8096326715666,-2.));
#2315=CARTESIAN_POINT('',(38.3653843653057,18.758545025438,-2.));
#2316=CARTESIAN_POINT('',(38.4115098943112,18.7027715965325,-2.));
#2317=CARTESIAN_POINT('',(38.4511037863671,18.6451240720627,-2.));
#2318=CARTESIAN_POINT('',(38.483978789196,18.5849055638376,-2.));
#2319=CARTESIAN_POINT('',(38.5089813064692,18.5217192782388,-2.));
#2320=CARTESIAN_POINT('',(38.5276033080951,18.4560233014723,-2.));
#2321=CARTESIAN_POINT('',(38.5381914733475,18.3874742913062,-2.));
#2322=CARTESIAN_POINT('',(38.5395110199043,18.3408893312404,-2.));
#2323=CARTESIAN_POINT('',(38.5401806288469,18.3172496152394,-2.));
#2324=B_SPLINE_CURVE_WITH_KNOTS('',3,(#2305,#2306,#2307,#2308,#2309,#2310,#2311,#2312,#2313,
#2314,#2315,#2316,#2317,#2318,#2319,#2320,#2321,#2322,#2323),.UNSPECIFIED.,.F.,.F.,(4,1,1,1,1,1,
1,1,1,1,1,1,1,1,1,1,4),(0.,0.0687118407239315,0.134812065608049,0.19953759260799,
0.263334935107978,0.326747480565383,0.390328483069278,0.454125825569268,0.519203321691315,
0.583510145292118,0.645497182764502,0.705289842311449,0.763487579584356,0.821856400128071,
0.880004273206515,0.939107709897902,1.),.UNSPECIFIED.);
#2325=CARTESIAN_POINT('',(37.7563264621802,19.0127624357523,-2.));
#2326=VERTEX_POINT('',#2325);
#2327=EDGE_CURVE('E494',#2326,#2281,#2324,.T.);
#2328=ORIENTED_EDGE('',*,*,#2327,.F.);
#2329=DIRECTION('',(0.,0.,-1.));
#2330=VECTOR('',#2329,1.);
#2331=CARTESIAN_POINT('',(37.7563264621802,19.0127624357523,-1.));
#2332=LINE('',#2331,#2330);
#2333=EDGE_CURVE('E1221',#2169,#2326,#2332,.T.);
#2334=ORIENTED_EDGE('',*,*,#2333,.F.);
#2335=ORIENTED_EDGE('',*,*,#2172,.T.);
#2336=ORIENTED_EDGE('',*,*,#2290,.T.);
#2337=EDGE_LOOP('',(#2328,#2334,#2335,#2336));
#2338=FACE_BOUND('',#2337,.T.);
#2339=ADVANCED_FACE('F507',(#2338),#2304,.T.);
#2340=DIRECTION('',(0.,0.,-1.));
#2341=VECTOR('',#2340,1.);
#2342=SURFACE_OF_LINEAR_EXTRUSION('',#2193,#2341);
#2343=CARTESIAN_POINT('',(36.969667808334,18.3172496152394,-2.));
#2344=CARTESIAN_POINT('',(36.9703374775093,18.3408892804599,-2.));
#2345=CARTESIAN_POINT('',(36.9716571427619,18.3874741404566,-2.));
#2346=CARTESIAN_POINT('',(36.9822444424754,18.4560238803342,-2.));
#2347=CARTESIAN_POINT('',(37.0008696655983,18.5217171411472,-2.));
#2348=CARTESIAN_POINT('',(37.0258601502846,18.5849135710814,-2.));
#2349=CARTESIAN_POINT('',(37.0587803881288,18.6450939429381,-2.));
#2350=CARTESIAN_POINT('',(37.0982838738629,18.7030138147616,-2.));
#2351=CARTESIAN_POINT('',(37.1452163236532,18.7583059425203,-2.));
#2352=CARTESIAN_POINT('',(37.1992188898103,18.8096699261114,-2.));
#2353=CARTESIAN_POINT('',(37.2574534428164,18.8570178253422,-2.));
#2354=CARTESIAN_POINT('',(37.3195139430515,18.8988039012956,-2.));
#2355=CARTESIAN_POINT('',(37.3848888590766,18.9338250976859,-2.));
#2356=CARTESIAN_POINT('',(37.4531793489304,18.9627240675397,-2.));
#2357=CARTESIAN_POINT('',(37.5245276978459,18.9852758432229,-2.));
#2358=CARTESIAN_POINT('',(37.5988916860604,19.0014932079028,-2.));
#2359=CARTESIAN_POINT('',(37.6766470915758,19.0104649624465,-2.));
#2360=CARTESIAN_POINT('',(37.7294283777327,19.0119868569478,-2.));
#2361=CARTESIAN_POINT('',(37.7563264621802,19.0127624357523,-2.));
#2362=B_SPLINE_CURVE_WITH_KNOTS('',3,(#2343,#2344,#2345,#2346,#2347,#2348,#2349,#2350,#2351,
#2352,#2353,#2354,#2355,#2356,#2357,#2358,#2359,#2360,#2361),.UNSPECIFIED.,.F.,.F.,(4,1,1,1,1,1,
1,1,1,1,1,1,1,1,1,1,4),(0.,0.060760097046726,0.11973522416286,0.177756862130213,
0.235998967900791,0.294070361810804,0.353733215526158,0.415972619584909,0.480139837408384,
0.545076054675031,0.608734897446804,0.672177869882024,0.735452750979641,0.799111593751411,
0.864283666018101,0.930837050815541,1.),.UNSPECIFIED.);
#2363=CARTESIAN_POINT('',(36.969667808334,18.3172496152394,-2.));
#2364=VERTEX_POINT('',#2363);
#2365=EDGE_CURVE('E1228',#2364,#2326,#2362,.T.);
#2366=ORIENTED_EDGE('',*,*,#2365,.F.);
#2367=DIRECTION('',(0.,0.,-1.));
#2368=VECTOR('',#2367,1.);
#2369=CARTESIAN_POINT('',(36.969667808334,18.3172496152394,-1.));
#2370=LINE('',#2369,#2368);
#2371=EDGE_CURVE('E1217',#2195,#2364,#2370,.T.);
#2372=ORIENTED_EDGE('',*,*,#2371,.F.);
#2373=ORIENTED_EDGE('',*,*,#2196,.T.);
#2374=ORIENTED_EDGE('',*,*,#2333,.T.);
#2375=EDGE_LOOP('',(#2366,#2372,#2373,#2374));
#2376=FACE_BOUND('',#2375,.T.);
#2377=ADVANCED_FACE('F1268',(#2376),#2342,.T.);
#2378=DIRECTION('',(0.,0.,-1.));
#2379=VECTOR('',#2378,1.);
#2380=SURFACE_OF_LINEAR_EXTRUSION('',#2217,#2379);
#2381=CARTESIAN_POINT('',(37.7240748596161,17.6217367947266,-2.));
#2382=CARTESIAN_POINT('',(37.6962408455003,17.6224971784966,-2.));
#2383=CARTESIAN_POINT('',(37.642057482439,17.6239773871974,-2.));
#2384=CARTESIAN_POINT('',(37.5626801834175,17.6329866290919,-2.));
#2385=CARTESIAN_POINT('',(37.4877559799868,17.648960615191,-2.));
#2386=CARTESIAN_POINT('',(37.4170847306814,17.6718803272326,-2.));
#2387=CARTESIAN_POINT('',(37.3499578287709,17.6995369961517,-2.));
#2388=CARTESIAN_POINT('',(37.2874415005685,17.7347489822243,-2.));
#2389=CARTESIAN_POINT('',(37.2294834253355,17.7767656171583,-2.));
#2390=CARTESIAN_POINT('',(37.1756954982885,17.8239756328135,-2.));
#2391=CARTESIAN_POINT('',(37.1279314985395,17.8764262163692,-2.));
#2392=CARTESIAN_POINT('',(37.0853884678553,17.9313233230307,-2.));
#2393=CARTESIAN_POINT('',(37.0492279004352,17.9889079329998,-2.));
#2394=CARTESIAN_POINT('',(37.0206646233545,18.0499011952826,-2.));
#2395=CARTESIAN_POINT('',(36.9971800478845,18.1128184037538,-2.));
#2396=CARTESIAN_POINT('',(36.9809620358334,18.1786727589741,-2.));
#2397=CARTESIAN_POINT('',(36.9719777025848,18.2471211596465,-2.));
#2398=CARTESIAN_POINT('',(36.9704461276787,18.2936198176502,-2.));
#2399=CARTESIAN_POINT('',(36.969667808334,18.3172496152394,-2.));
#2400=B_SPLINE_CURVE_WITH_KNOTS('',3,(#2381,#2382,#2383,#2384,#2385,#2386,#2387,#2388,#2389,
#2390,#2391,#2392,#2393,#2394,#2395,#2396,#2397,#2398,#2399),.UNSPECIFIED.,.F.,.F.,(4,1,1,1,1,1,
1,1,1,1,1,1,1,1,1,1,4),(0.,0.0727129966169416,0.1415474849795,0.208362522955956,
0.272461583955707,0.335389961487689,0.397711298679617,0.459383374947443,0.522098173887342,
0.584314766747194,0.644391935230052,0.703345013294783,0.761508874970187,0.820030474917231,
0.878517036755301,0.938264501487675,1.),.UNSPECIFIED.);
#2401=EDGE_CURVE('E1236',#2283,#2364,#2400,.T.);
#2402=ORIENTED_EDGE('',*,*,#2401,.F.);
#2403=ORIENTED_EDGE('',*,*,#2297,.F.);
#2404=ORIENTED_EDGE('',*,*,#2220,.T.);
#2405=ORIENTED_EDGE('',*,*,#2371,.T.);
#2406=EDGE_LOOP('',(#2402,#2403,#2404,#2405));
#2407=FACE_BOUND('',#2406,.T.);
#2408=ADVANCED_FACE('F510',(#2407),#2380,.T.);
#2409=ORIENTED_EDGE('',*,*,#2327,.T.);
#2410=ORIENTED_EDGE('',*,*,#2284,.T.);
#2411=ORIENTED_EDGE('',*,*,#2401,.T.);
#2412=ORIENTED_EDGE('',*,*,#2365,.T.);
#2413=EDGE_LOOP('',(#2409,#2410,#2411,#2412));
#2414=FACE_BOUND('',#2413,.T.);
#2415=ADVANCED_FACE('F707',(#2414),#23,.T.);
#2416=CARTESIAN_POINT('',(33.3350524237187,15.781993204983,-1.));
#2417=DIRECTION('',(-0.920967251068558,0.389639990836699,0.));
#2418=DIRECTION('',(-0.389639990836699,-0.920967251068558,0.));
#2419=AXIS2_PLACEMENT_3D('',#2416,#2417,#2418);
#2420=PLANE('',#2419);
#2421=ORIENTED_EDGE('',*,*,#40,.F.);
#2422=DIRECTION('',(0.,0.,-1.));
#2423=VECTOR('',#2422,1.);
#2424=CARTESIAN_POINT('',(33.3350524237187,15.781993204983,-1.));
#2425=LINE('',#2424,#2423);
#2426=CARTESIAN_POINT('',(33.3350524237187,15.781993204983,-1.));
#2427=VERTEX_POINT('',#2426);
#2428=EDGE_CURVE('E455',#2427,#31,#2425,.T.);
#2429=ORIENTED_EDGE('',*,*,#2428,.F.);
#2430=DIRECTION('',(0.389639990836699,0.920967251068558,0.));
#2431=VECTOR('',#2430,1.);
#2432=CARTESIAN_POINT('',(33.3350524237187,15.781993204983,-1.));
#2433=LINE('',#2432,#2431);
#2434=CARTESIAN_POINT('',(34.8158216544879,19.281993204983,-1.));
#2435=VERTEX_POINT('',#2434);
#2436=EDGE_CURVE('E440',#2427,#2435,#2433,.T.);
#2437=ORIENTED_EDGE('',*,*,#2436,.T.);
#2438=DIRECTION('',(0.,0.,-1.));
#2439=VECTOR('',#2438,1.);
#2440=CARTESIAN_POINT('',(34.8158216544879,19.281993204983,-1.));
#2441=LINE('',#2440,#2439);
#2442=EDGE_CURVE('E484',#2435,#39,#2441,.T.);
#2443=ORIENTED_EDGE('',*,*,#2442,.T.);
#2444=EDGE_LOOP('',(#2421,#2429,#2437,#2443));
#2445=FACE_BOUND('',#2444,.T.);
#2446=ADVANCED_FACE('F1270',(#2445),#2420,.T.);
#2447=CARTESIAN_POINT('',(34.8158216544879,19.281993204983,-1.));
#2448=DIRECTION('',(0.,-1.,0.));
#2449=DIRECTION('',(0.,0.,-1.));
#2450=AXIS2_PLACEMENT_3D('',#2447,#2448,#2449);
#2451=PLANE('',#2450);
#2452=ORIENTED_EDGE('',*,*,#48,.F.);
#2453=ORIENTED_EDGE('',*,*,#2442,.F.);
#2454=DIRECTION('',(-1.,0.,0.));
#2455=VECTOR('',#2454,1.);
#2456=CARTESIAN_POINT('',(34.8158216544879,19.281993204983,-1.));
#2457=LINE('',#2456,#2455);
#2458=CARTESIAN_POINT('',(34.4792831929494,19.281993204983,-1.));
#2459=VERTEX_POINT('',#2458);
#2460=EDGE_CURVE('E443',#2435,#2459,#2457,.T.);
#2461=ORIENTED_EDGE('',*,*,#2460,.T.);
#2462=DIRECTION('',(0.,0.,-1.));
#2463=VECTOR('',#2462,1.);
#2464=CARTESIAN_POINT('',(34.4792831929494,19.281993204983,-1.));
#2465=LINE('',#2464,#2463);
#2466=EDGE_CURVE('E482',#2459,#47,#2465,.T.);
#2467=ORIENTED_EDGE('',*,*,#2466,.T.);
#2468=EDGE_LOOP('',(#2452,#2453,#2461,#2467));
#2469=FACE_BOUND('',#2468,.T.);
#2470=ADVANCED_FACE('F1292',(#2469),#2451,.T.);
#2471=CARTESIAN_POINT('',(34.4792831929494,19.281993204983,-1.));
#2472=DIRECTION('',(0.920999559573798,-0.389563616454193,0.));
#2473=DIRECTION('',(0.389563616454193,0.920999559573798,0.));
#2474=AXIS2_PLACEMENT_3D('',#2471,#2472,#2473);
#2475=PLANE('',#2474);
#2476=ORIENTED_EDGE('',*,*,#56,.F.);
#2477=ORIENTED_EDGE('',*,*,#2466,.F.);
#2478=DIRECTION('',(-0.389563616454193,-0.920999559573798,0.));
#2479=VECTOR('',#2478,1.);
#2480=CARTESIAN_POINT('',(34.4792831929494,19.281993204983,-1.));
#2481=LINE('',#2480,#2479);
#2482=CARTESIAN_POINT('',(33.3126165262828,16.5237800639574,-1.));
#2483=VERTEX_POINT('',#2482);
#2484=EDGE_CURVE('E446',#2459,#2483,#2481,.T.);
#2485=ORIENTED_EDGE('',*,*,#2484,.T.);
#2486=DIRECTION('',(0.,0.,-1.));
#2487=VECTOR('',#2486,1.);
#2488=CARTESIAN_POINT('',(33.3126165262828,16.5237800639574,-1.));
#2489=LINE('',#2488,#2487);
#2490=EDGE_CURVE('E480',#2483,#55,#2489,.T.);
#2491=ORIENTED_EDGE('',*,*,#2490,.T.);
#2492=EDGE_LOOP('',(#2476,#2477,#2485,#2491));
#2493=FACE_BOUND('',#2492,.T.);
#2494=ADVANCED_FACE('F1296',(#2493),#2475,.T.);
#2495=CARTESIAN_POINT('',(33.3126165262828,16.5237800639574,-1.));
#2496=DIRECTION('',(-0.920999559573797,-0.389563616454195,0.));
#2497=DIRECTION('',(0.389563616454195,-0.920999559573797,0.));
#2498=AXIS2_PLACEMENT_3D('',#2495,#2496,#2497);
#2499=PLANE('',#2498);
#2500=ORIENTED_EDGE('',*,*,#64,.F.);
#2501=ORIENTED_EDGE('',*,*,#2490,.F.);
#2502=DIRECTION('',(-0.389563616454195,0.920999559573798,0.));
#2503=VECTOR('',#2502,1.);
#2504=CARTESIAN_POINT('',(33.3126165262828,16.5237800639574,-1.));
#2505=LINE('',#2504,#2503);
#2506=CARTESIAN_POINT('',(32.1459498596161,19.281993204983,-1.));
#2507=VERTEX_POINT('',#2506);
#2508=EDGE_CURVE('E448',#2483,#2507,#2505,.T.);
#2509=ORIENTED_EDGE('',*,*,#2508,.T.);
#2510=DIRECTION('',(0.,0.,-1.));
#2511=VECTOR('',#2510,1.);
#2512=CARTESIAN_POINT('',(32.1459498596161,19.281993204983,-1.));
#2513=LINE('',#2512,#2511);
#2514=EDGE_CURVE('E478',#2507,#63,#2513,.T.);
#2515=ORIENTED_EDGE('',*,*,#2514,.T.);
#2516=EDGE_LOOP('',(#2500,#2501,#2509,#2515));
#2517=FACE_BOUND('',#2516,.T.);
#2518=ADVANCED_FACE('F1301',(#2517),#2499,.T.);
#2519=CARTESIAN_POINT('',(32.1459498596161,19.281993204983,-1.));
#2520=DIRECTION('',(0.,-1.,0.));
#2521=DIRECTION('',(0.,0.,-1.));
#2522=AXIS2_PLACEMENT_3D('',#2519,#2520,#2521);
#2523=PLANE('',#2522);
#2524=ORIENTED_EDGE('',*,*,#72,.F.);
#2525=ORIENTED_EDGE('',*,*,#2514,.F.);
#2526=DIRECTION('',(-1.,0.,0.));
#2527=VECTOR('',#2526,1.);
#2528=CARTESIAN_POINT('',(32.1459498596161,19.281993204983,-1.));
#2529=LINE('',#2528,#2527);
#2530=CARTESIAN_POINT('',(31.8094113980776,19.281993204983,-1.));
#2531=VERTEX_POINT('',#2530);
#2532=EDGE_CURVE('E450',#2507,#2531,#2529,.T.);
#2533=ORIENTED_EDGE('',*,*,#2532,.T.);
#2534=DIRECTION('',(0.,0.,-1.));
#2535=VECTOR('',#2534,1.);
#2536=CARTESIAN_POINT('',(31.8094113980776,19.281993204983,-1.));
#2537=LINE('',#2536,#2535);
#2538=EDGE_CURVE('E476',#2531,#71,#2537,.T.);
#2539=ORIENTED_EDGE('',*,*,#2538,.T.);
#2540=EDGE_LOOP('',(#2524,#2525,#2533,#2539));
#2541=FACE_BOUND('',#2540,.T.);
#2542=ADVANCED_FACE('F1307',(#2541),#2523,.T.);
#2543=CARTESIAN_POINT('',(31.8094113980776,19.281993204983,-1.));
#2544=DIRECTION('',(0.920967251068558,0.389639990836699,0.));
#2545=DIRECTION('',(-0.389639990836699,0.920967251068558,0.));
#2546=AXIS2_PLACEMENT_3D('',#2543,#2544,#2545);
#2547=PLANE('',#2546);
#2548=ORIENTED_EDGE('',*,*,#78,.F.);
#2549=ORIENTED_EDGE('',*,*,#2538,.F.);
#2550=DIRECTION('',(0.389639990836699,-0.920967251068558,0.));
#2551=VECTOR('',#2550,1.);
#2552=CARTESIAN_POINT('',(31.8094113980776,19.281993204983,-1.));
#2553=LINE('',#2552,#2551);
#2554=CARTESIAN_POINT('',(33.2901806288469,15.781993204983,-1.));
#2555=VERTEX_POINT('',#2554);
#2556=EDGE_CURVE('E452',#2531,#2555,#2553,.T.);
#2557=ORIENTED_EDGE('',*,*,#2556,.T.);
#2558=DIRECTION('',(0.,0.,-1.));
#2559=VECTOR('',#2558,1.);
#2560=CARTESIAN_POINT('',(33.2901806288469,15.781993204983,-1.));
#2561=LINE('',#2560,#2559);
#2562=EDGE_CURVE('E474',#2555,#29,#2561,.T.);
#2563=ORIENTED_EDGE('',*,*,#2562,.T.);
#2564=EDGE_LOOP('',(#2548,#2549,#2557,#2563));
#2565=FACE_BOUND('',#2564,.T.);
#2566=ADVANCED_FACE('F1311',(#2565),#2547,.T.);
#2567=CARTESIAN_POINT('',(33.2901806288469,15.781993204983,-1.));
#2568=DIRECTION('',(0.,1.,0.));
#2569=DIRECTION('',(0.,0.,1.));
#2570=AXIS2_PLACEMENT_3D('',#2567,#2568,#2569);
#2571=PLANE('',#2570);
#2572=ORIENTED_EDGE('',*,*,#32,.F.);
#2573=ORIENTED_EDGE('',*,*,#2562,.F.);
#2574=DIRECTION('',(1.,0.,0.));
#2575=VECTOR('',#2574,1.);
#2576=CARTESIAN_POINT('',(33.2901806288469,15.781993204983,-1.));
#2577=LINE('',#2576,#2575);
#2578=EDGE_CURVE('E454',#2555,#2427,#2577,.T.);
#2579=ORIENTED_EDGE('',*,*,#2578,.T.);
#2580=ORIENTED_EDGE('',*,*,#2428,.T.);
#2581=EDGE_LOOP('',(#2572,#2573,#2579,#2580));
#2582=FACE_BOUND('',#2581,.T.);
#2583=ADVANCED_FACE('F1315',(#2582),#2571,.T.);
#2584=CARTESIAN_POINT('',(0.,0.,-1.));
#2585=DIRECTION('',(0.,0.,1.));
#2586=DIRECTION('',(1.,0.,0.));
#2587=AXIS2_PLACEMENT_3D('',#2584,#2585,#2586);
#2588=PLANE('',#2587);
#2589=ORIENTED_EDGE('',*,*,#2436,.F.);
#2590=ORIENTED_EDGE('',*,*,#2578,.F.);
#2591=ORIENTED_EDGE('',*,*,#2556,.F.);
#2592=ORIENTED_EDGE('',*,*,#2532,.F.);
#2593=ORIENTED_EDGE('',*,*,#2508,.F.);
#2594=ORIENTED_EDGE('',*,*,#2484,.F.);
#2595=ORIENTED_EDGE('',*,*,#2460,.F.);
#2596=EDGE_LOOP('',(#2589,#2590,#2591,#2592,#2593,#2594,#2595));
#2597=FACE_BOUND('',#2596,.T.);
#2598=ADVANCED_FACE('F1319',(#2597),#2588,.F.);
#2599=CARTESIAN_POINT('',(29.477480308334,19.3717367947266,-1.));
#2600=CARTESIAN_POINT('',(29.4372658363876,19.3712546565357,-1.));
#2601=CARTESIAN_POINT('',(29.3576653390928,19.3703003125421,-1.));
#2602=CARTESIAN_POINT('',(29.2399126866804,19.3609941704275,-1.));
#2603=CARTESIAN_POINT('',(29.1252703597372,19.3454805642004,-1.));
#2604=CARTESIAN_POINT('',(29.0136593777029,19.3243644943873,-1.));
#2605=CARTESIAN_POINT('',(28.9045367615,19.2981571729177,-1.));
#2606=CARTESIAN_POINT('',(28.7987365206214,19.2640168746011,-1.));
#2607=CARTESIAN_POINT('',(28.6956378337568,19.2249803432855,-1.));
#2608=CARTESIAN_POINT('',(28.5958909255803,19.1800218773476,-1.));
#2609=CARTESIAN_POINT('',(28.49997437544,19.1295551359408,-1.));
#2610=CARTESIAN_POINT('',(28.4079180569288,19.0741395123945,-1.));
#2611=CARTESIAN_POINT('',(28.3204531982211,19.01384370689,-1.));
#2612=CARTESIAN_POINT('',(28.2369643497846,18.9491805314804,-1.));
#2613=CARTESIAN_POINT('',(28.1588481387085,18.878781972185,-1.));
#2614=CARTESIAN_POINT('',(28.0838866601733,18.8045843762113,-1.));
#2615=CARTESIAN_POINT('',(28.0146255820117,18.724450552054,-1.));
#2616=CARTESIAN_POINT('',(27.9718723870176,18.668045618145,-1.));
#2617=CARTESIAN_POINT('',(27.9504370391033,18.6397656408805,-1.));
#2618=B_SPLINE_CURVE_WITH_KNOTS('',3,(#2599,#2600,#2601,#2602,#2603,#2604,#2605,#2606,#2607,
#2608,#2609,#2610,#2611,#2612,#2613,#2614,#2615,#2616,#2617),.UNSPECIFIED.,.F.,.F.,(4,1,1,1,1,1,
1,1,1,1,1,1,1,1,1,1,4),(0.,0.0685475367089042,0.135682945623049,0.20121498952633,
0.265682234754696,0.329266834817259,0.392395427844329,0.455069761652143,0.517126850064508,
0.578790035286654,0.639739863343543,0.700191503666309,0.759806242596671,0.819628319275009,
0.879354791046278,0.939511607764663,1.),.UNSPECIFIED.);
#2619=DIRECTION('',(0.,0.,-1.));
#2620=VECTOR('',#2619,1.);
#2621=SURFACE_OF_LINEAR_EXTRUSION('',#2618,#2620);
#2622=ORIENTED_EDGE('',*,*,#660,.F.);
#2623=DIRECTION('',(0.,0.,-1.));
#2624=VECTOR('',#2623,1.);
#2625=CARTESIAN_POINT('',(29.477480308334,19.3717367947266,-1.));
#2626=LINE('',#2625,#2624);
#2627=CARTESIAN_POINT('',(29.477480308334,19.3717367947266,-1.));
#2628=VERTEX_POINT('',#2627);
#2629=EDGE_CURVE('E426',#2628,#635,#2626,.T.);
#2630=ORIENTED_EDGE('',*,*,#2629,.F.);
#2631=CARTESIAN_POINT('',(27.9504370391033,18.6397656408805,-1.));
#2632=VERTEX_POINT('',#2631);
#2633=EDGE_CURVE('E417',#2628,#2632,#2618,.T.);
#2634=ORIENTED_EDGE('',*,*,#2633,.T.);
#2635=DIRECTION('',(0.,0.,-1.));
#2636=VECTOR('',#2635,1.);
#2637=CARTESIAN_POINT('',(27.9504370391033,18.6397656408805,-1.));
#2638=LINE('',#2637,#2636);
#2639=EDGE_CURVE('E425',#2632,#659,#2638,.T.);
#2640=ORIENTED_EDGE('',*,*,#2639,.T.);
#2641=EDGE_LOOP('',(#2622,#2630,#2634,#2640));
#2642=FACE_BOUND('',#2641,.T.);
#2643=ADVANCED_FACE('F424',(#2642),#2621,.T.);
#2644=CARTESIAN_POINT('',(27.9504370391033,18.6397656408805,-1.));
#2645=DIRECTION('',(0.607750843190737,0.794127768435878,0.));
#2646=DIRECTION('',(-0.794127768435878,0.607750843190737,0.));
#2647=AXIS2_PLACEMENT_3D('',#2644,#2645,#2646);
#2648=PLANE('',#2647);
#2649=ORIENTED_EDGE('',*,*,#668,.F.);
#2650=ORIENTED_EDGE('',*,*,#2639,.F.);
#2651=DIRECTION('',(0.794127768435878,-0.607750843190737,0.));
#2652=VECTOR('',#2651,1.);
#2653=CARTESIAN_POINT('',(27.9504370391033,18.6397656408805,-1.));
#2654=LINE('',#2653,#2652);
#2655=CARTESIAN_POINT('',(28.225276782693,18.4294291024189,-1.));
#2656=VERTEX_POINT('',#2655);
#2657=EDGE_CURVE('E413',#2632,#2656,#2654,.T.);
#2658=ORIENTED_EDGE('',*,*,#2657,.T.);
#2659=DIRECTION('',(0.,0.,-1.));
#2660=VECTOR('',#2659,1.);
#2661=CARTESIAN_POINT('',(28.225276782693,18.4294291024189,-1.));
#2662=LINE('',#2661,#2660);
#2663=EDGE_CURVE('E432',#2656,#667,#2662,.T.);
#2664=ORIENTED_EDGE('',*,*,#2663,.T.);
#2665=EDGE_LOOP('',(#2649,#2650,#2658,#2664));
#2666=FACE_BOUND('',#2665,.T.);
#2667=ADVANCED_FACE('F429',(#2666),#2648,.T.);
#2668=CARTESIAN_POINT('',(28.225276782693,18.4294291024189,-1.));
#2669=CARTESIAN_POINT('',(28.2448826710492,18.45279507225,-1.));
#2670=CARTESIAN_POINT('',(28.2838301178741,18.4992119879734,-1.));
#2671=CARTESIAN_POINT('',(28.346489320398,18.5643915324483,-1.));
#2672=CARTESIAN_POINT('',(28.4117909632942,18.625456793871,-1.));
#2673=CARTESIAN_POINT('',(28.4797100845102,18.6826986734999,-1.));
#2674=CARTESIAN_POINT('',(28.5514692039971,18.7341154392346,-1.));
#2675=CARTESIAN_POINT('',(28.6253300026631,18.7823865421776,-1.));
#2676=CARTESIAN_POINT('',(28.7025280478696,18.8256542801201,-1.));
#2677=CARTESIAN_POINT('',(28.8092797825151,18.878117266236,-1.));
#2678=CARTESIAN_POINT('',(28.9489276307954,18.9328634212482,-1.));
#2679=CARTESIAN_POINT('',(29.1247224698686,18.9787666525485,-1.));
#2680=CARTESIAN_POINT('',(29.3082335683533,19.0079878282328,-1.));
#2681=CARTESIAN_POINT('',(29.4334311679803,19.0111526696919,-1.));
#2682=CARTESIAN_POINT('',(29.4971117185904,19.0127624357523,-1.));
#2683=B_SPLINE_CURVE_WITH_KNOTS('',3,(#2668,#2669,#2670,#2671,#2672,#2673,#2674,#2675,#2676,
#2677,#2678,#2679,#2680,#2681,#2682),.UNSPECIFIED.,.F.,.F.,(4,1,1,1,1,1,1,1,1,1,1,1,4),(0.,
0.0631632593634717,0.125474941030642,0.187121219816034,0.248294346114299,0.309294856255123,
0.369850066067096,0.430973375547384,0.492455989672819,0.616147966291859,0.740843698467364,
0.868182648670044,1.),.UNSPECIFIED.);
#2684=DIRECTION('',(0.,0.,-1.));
#2685=VECTOR('',#2684,1.);
#2686=SURFACE_OF_LINEAR_EXTRUSION('',#2683,#2685);
#2687=ORIENTED_EDGE('',*,*,#688,.F.);
#2688=ORIENTED_EDGE('',*,*,#2663,.F.);
#2689=CARTESIAN_POINT('',(29.4971117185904,19.0127624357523,-1.));
#2690=VERTEX_POINT('',#2689);
#2691=EDGE_CURVE('E419',#2656,#2690,#2683,.T.);
#2692=ORIENTED_EDGE('',*,*,#2691,.T.);
#2693=DIRECTION('',(0.,0.,-1.));
#2694=VECTOR('',#2693,1.);
#2695=CARTESIAN_POINT('',(29.4971117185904,19.0127624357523,-1.));
#2696=LINE('',#2695,#2694);
#2697=EDGE_CURVE('E436',#2690,#687,#2696,.T.);
#2698=ORIENTED_EDGE('',*,*,#2697,.T.);
#2699=EDGE_LOOP('',(#2687,#2688,#2692,#2698));
#2700=FACE_BOUND('',#2699,.T.);
#2701=ADVANCED_FACE('F1346',(#2700),#2686,.T.);
#2702=CARTESIAN_POINT('',(29.4971117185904,19.0127624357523,-1.));
#2703=CARTESIAN_POINT('',(29.5321950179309,19.0123584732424,-1.));
#2704=CARTESIAN_POINT('',(29.6020360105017,19.0115542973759,-1.));
#2705=CARTESIAN_POINT('',(29.7056844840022,19.0009451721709,-1.));
#2706=CARTESIAN_POINT('',(29.8073975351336,18.9860339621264,-1.));
#2707=CARTESIAN_POINT('',(29.9071090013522,18.9639086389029,-1.));
#2708=CARTESIAN_POINT('',(30.0046919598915,18.9359360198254,-1.));
#2709=CARTESIAN_POINT('',(30.1007843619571,18.9025106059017,-1.));
#2710=CARTESIAN_POINT('',(30.1939949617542,18.8611557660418,-1.));
#2711=CARTESIAN_POINT('',(30.2856131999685,18.8154475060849,-1.));
#2712=CARTESIAN_POINT('',(30.3733924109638,18.7638200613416,-1.));
#2713=CARTESIAN_POINT('',(30.4564474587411,18.70750670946,-0.999999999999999));
#2714=CARTESIAN_POINT('',(30.5344754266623,18.6471376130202,-1.));
#2715=CARTESIAN_POINT('',(30.6075380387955,18.5824865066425,-1.));
#2716=CARTESIAN_POINT('',(30.6757099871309,18.5138445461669,-1.));
#2717=CARTESIAN_POINT('',(30.7384972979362,18.4404802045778,-1.));
#2718=CARTESIAN_POINT('',(30.7956827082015,18.3626280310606,-1.));
#2719=CARTESIAN_POINT('',(30.8483997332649,18.2813146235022,-1.));
#2720=CARTESIAN_POINT('',(30.8956124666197,18.1967768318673,-1.));
#2721=CARTESIAN_POINT('',(30.9351423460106,18.1087017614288,-1.));
#2722=CARTESIAN_POINT('',(30.9701474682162,18.0185976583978,-1.));
#2723=CARTESIAN_POINT('',(30.9978467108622,17.9254464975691,-1.));
#2724=CARTESIAN_POINT('',(31.0197712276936,17.8299037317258,-1.));
#2725=CARTESIAN_POINT('',(31.0348988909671,17.7317129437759,-1.));
#2726=CARTESIAN_POINT('',(31.0453873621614,17.6310792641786,-1.));
#2727=CARTESIAN_POINT('',(31.0461875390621,17.5628699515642,-1.));
#2728=CARTESIAN_POINT('',(31.0465908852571,17.5284875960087,-1.));
#2729=B_SPLINE_CURVE_WITH_KNOTS('',3,(#2702,#2703,#2704,#2705,#2706,#2707,#2708,#2709,#2710,
#2711,#2712,#2713,#2714,#2715,#2716,#2717,#2718,#2719,#2720,#2721,#2722,#2723,#2724,#2725,#2726,
#2727,#2728),.UNSPECIFIED.,.F.,.F.,(4,1,1,1,1,1,1,1,1,1,1,1,1,1,1,1,1,1,1,1,1,1,1,1,4),(0.,
0.0439549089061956,0.0875018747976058,0.130462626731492,0.172752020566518,0.215403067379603,
0.25764982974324,0.300152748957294,0.343121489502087,0.385925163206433,0.427685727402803,
0.46881795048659,0.509491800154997,0.54988303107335,0.589980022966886,0.630405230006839,
0.670868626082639,0.711383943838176,0.751627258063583,0.791775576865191,0.832458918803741,
0.873319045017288,0.914542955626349,0.956923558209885,1.),.UNSPECIFIED.);
#2730=DIRECTION('',(0.,0.,-1.));
#2731=VECTOR('',#2730,1.);
#2732=SURFACE_OF_LINEAR_EXTRUSION('',#2729,#2731);
#2733=ORIENTED_EDGE('',*,*,#720,.F.);
#2734=ORIENTED_EDGE('',*,*,#2697,.F.);
#2735=CARTESIAN_POINT('',(31.0465908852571,17.5284875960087,-1.));
#2736=VERTEX_POINT('',#2735);
#2737=EDGE_CURVE('E1338',#2690,#2736,#2729,.T.);
#2738=ORIENTED_EDGE('',*,*,#2737,.T.);
#2739=DIRECTION('',(0.,0.,-1.));
#2740=VECTOR('',#2739,1.);
#2741=CARTESIAN_POINT('',(31.0465908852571,17.5284875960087,-1.));
#2742=LINE('',#2741,#2740);
#2743=EDGE_CURVE('E1478',#2736,#719,#2742,.T.);
#2744=ORIENTED_EDGE('',*,*,#2743,.T.);
#2745=EDGE_LOOP('',(#2733,#2734,#2738,#2744));
#2746=FACE_BOUND('',#2745,.T.);
#2747=ADVANCED_FACE('F1349',(#2746),#2732,.T.);
#2748=CARTESIAN_POINT('',(31.0465908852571,17.5284875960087,-1.));
#2749=CARTESIAN_POINT('',(31.0453290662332,17.4767562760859,-1.));
#2750=CARTESIAN_POINT('',(31.0428516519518,17.3751886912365,-1.));
#2751=CARTESIAN_POINT('',(31.0208033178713,17.2264180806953,-1.));
#2752=CARTESIAN_POINT('',(30.9872982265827,17.083897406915,-1.));
#2753=CARTESIAN_POINT('',(30.937082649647,16.9485175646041,-1.));
#2754=CARTESIAN_POINT('',(30.8751635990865,16.8186092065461,-1.));
#2755=CARTESIAN_POINT('',(30.7969229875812,16.6963703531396,-1.));
#2756=CARTESIAN_POINT('',(30.706306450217,16.5799537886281,-1.));
#2757=CARTESIAN_POINT('',(30.6020320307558,16.4721108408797,-1.));
#2758=CARTESIAN_POINT('',(30.4876262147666,16.3735971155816,-1.));
#2759=CARTESIAN_POINT('',(30.3648783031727,16.2868465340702,-1.));
#2760=CARTESIAN_POINT('',(30.2340940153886,16.2145316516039,-1.));
#2761=CARTESIAN_POINT('',(30.096717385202,16.1543557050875,-1.));
#2762=CARTESIAN_POINT('',(29.9516912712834,16.108098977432,-1.));
#2763=CARTESIAN_POINT('',(29.7992764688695,16.0755348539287,-1.));
#2764=CARTESIAN_POINT('',(29.6398044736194,16.0542926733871,-1.));
#2765=CARTESIAN_POINT('',(29.5308350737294,16.052258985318,-1.));
#2766=CARTESIAN_POINT('',(29.4753769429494,16.0512239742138,-1.));
#2767=B_SPLINE_CURVE_WITH_KNOTS('',3,(#2748,#2749,#2750,#2751,#2752,#2753,#2754,#2755,#2756,
#2757,#2758,#2759,#2760,#2761,#2762,#2763,#2764,#2765,#2766),.UNSPECIFIED.,.F.,.F.,(4,1,1,1,1,1,
1,1,1,1,1,1,1,1,1,1,4),(0.,0.0643232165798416,0.126290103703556,0.186726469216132,
0.246146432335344,0.305575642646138,0.365429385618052,0.42632630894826,0.488839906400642,
0.551724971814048,0.613918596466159,0.675483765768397,0.737333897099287,0.800229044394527,
0.864502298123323,0.931040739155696,1.),.UNSPECIFIED.);
#2768=DIRECTION('',(0.,0.,-1.));
#2769=VECTOR('',#2768,1.);
#2770=SURFACE_OF_LINEAR_EXTRUSION('',#2767,#2769);
#2771=ORIENTED_EDGE('',*,*,#744,.F.);
#2772=ORIENTED_EDGE('',*,*,#2743,.F.);
#2773=CARTESIAN_POINT('',(29.4753769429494,16.0512239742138,-1.));
#2774=VERTEX_POINT('',#2773);
#2775=EDGE_CURVE('E1361',#2736,#2774,#2767,.T.);
#2776=ORIENTED_EDGE('',*,*,#2775,.T.);
#2777=DIRECTION('',(0.,0.,-1.));
#2778=VECTOR('',#2777,1.);
#2779=CARTESIAN_POINT('',(29.4753769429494,16.0512239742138,-1.));
#2780=LINE('',#2779,#2778);
#2781=EDGE_CURVE('E1476',#2774,#743,#2780,.T.);
#2782=ORIENTED_EDGE('',*,*,#2781,.T.);
#2783=EDGE_LOOP('',(#2771,#2772,#2776,#2782));
#2784=FACE_BOUND('',#2783,.T.);
#2785=ADVANCED_FACE('F1353',(#2784),#2770,.T.);
#2786=CARTESIAN_POINT('',(29.4753769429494,16.0512239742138,-1.));
#2787=CARTESIAN_POINT('',(29.4142742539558,16.0529127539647,-1.));
#2788=CARTESIAN_POINT('',(29.2940095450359,16.0562366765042,-1.));
#2789=CARTESIAN_POINT('',(29.1176415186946,16.0843959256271,-1.));
#2790=CARTESIAN_POINT('',(28.9488057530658,16.1300538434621,-1.));
#2791=CARTESIAN_POINT('',(28.7874931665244,16.1939517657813,-1.));
#2792=CARTESIAN_POINT('',(28.6341585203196,16.277017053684,-1.));
#2793=CARTESIAN_POINT('',(28.4885618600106,16.3777149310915,-1.));
#2794=CARTESIAN_POINT('',(28.3505802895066,16.4970032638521,-1.));
#2795=CARTESIAN_POINT('',(28.2676090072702,16.5880863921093,-1.));
#2796=CARTESIAN_POINT('',(28.225276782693,16.6345573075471,-1.));
#2797=B_SPLINE_CURVE_WITH_KNOTS('',3,(#2786,#2787,#2788,#2789,#2790,#2791,#2792,#2793,#2794,
#2795,#2796),.UNSPECIFIED.,.F.,.F.,(4,1,1,1,1,1,1,1,4),(0.,0.128515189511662,0.252948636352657,
0.374754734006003,0.495939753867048,0.617180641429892,0.740909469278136,0.867811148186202,1.),.UNSPECIFIED.);
#2798=DIRECTION('',(0.,0.,-1.));
#2799=VECTOR('',#2798,1.);
#2800=SURFACE_OF_LINEAR_EXTRUSION('',#2797,#2799);
#2801=ORIENTED_EDGE('',*,*,#760,.F.);
#2802=ORIENTED_EDGE('',*,*,#2781,.F.);
#2803=CARTESIAN_POINT('',(28.225276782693,16.6345573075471,-1.));
#2804=VERTEX_POINT('',#2803);
#2805=EDGE_CURVE('E1365',#2774,#2804,#2797,.T.);
#2806=ORIENTED_EDGE('',*,*,#2805,.T.);
#2807=DIRECTION('',(0.,0.,-1.));
#2808=VECTOR('',#2807,1.);
#2809=CARTESIAN_POINT('',(28.225276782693,16.6345573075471,-1.));
#2810=LINE('',#2809,#2808);
#2811=EDGE_CURVE('E1410',#2804,#759,#2810,.T.);
#2812=ORIENTED_EDGE('',*,*,#2811,.T.);
#2813=EDGE_LOOP('',(#2801,#2802,#2806,#2812));
#2814=FACE_BOUND('',#2813,.T.);
#2815=ADVANCED_FACE('F1357',(#2814),#2800,.T.);
#2816=CARTESIAN_POINT('',(28.225276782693,16.6345573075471,-1.));
#2817=DIRECTION('',(0.603896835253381,-0.797062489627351,0.));
#2818=DIRECTION('',(0.797062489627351,0.603896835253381,0.));
#2819=AXIS2_PLACEMENT_3D('',#2816,#2817,#2818);
#2820=PLANE('',#2819);
#2821=ORIENTED_EDGE('',*,*,#768,.F.);
#2822=ORIENTED_EDGE('',*,*,#2811,.F.);
#2823=DIRECTION('',(-0.797062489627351,-0.603896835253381,0.));
#2824=VECTOR('',#2823,1.);
#2825=CARTESIAN_POINT('',(28.225276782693,16.6345573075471,-1.));
#2826=LINE('',#2825,#2824);
#2827=CARTESIAN_POINT('',(27.9504370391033,16.4263241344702,-1.));
#2828=VERTEX_POINT('',#2827);
#2829=EDGE_CURVE('E1373',#2804,#2828,#2826,.T.);
#2830=ORIENTED_EDGE('',*,*,#2829,.T.);
#2831=DIRECTION('',(0.,0.,-1.));
#2832=VECTOR('',#2831,1.);
#2833=CARTESIAN_POINT('',(27.9504370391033,16.4263241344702,-1.));
#2834=LINE('',#2833,#2832);
#2835=EDGE_CURVE('E1413',#2828,#767,#2834,.T.);
#2836=ORIENTED_EDGE('',*,*,#2835,.T.);
#2837=EDGE_LOOP('',(#2821,#2822,#2830,#2836));
#2838=FACE_BOUND('',#2837,.T.);
#2839=ADVANCED_FACE('F1396',(#2838),#2820,.T.);
#2840=CARTESIAN_POINT('',(27.9504370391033,16.4263241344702,-1.));
#2841=CARTESIAN_POINT('',(27.9725551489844,16.3977856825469,-1.));
#2842=CARTESIAN_POINT('',(28.0166854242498,16.3408454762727,-1.));
#2843=CARTESIAN_POINT('',(28.0881434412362,16.2605737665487,-1.));
#2844=CARTESIAN_POINT('',(28.1634207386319,16.1850697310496,-1.));
#2845=CARTESIAN_POINT('',(28.2430764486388,16.1149421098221,-1.));
#2846=CARTESIAN_POINT('',(28.3261942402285,16.0487876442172,-1.));
#2847=CARTESIAN_POINT('',(28.4142665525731,15.9884858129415,-1.));
#2848=CARTESIAN_POINT('',(28.5061355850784,15.9331949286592,-1.));
#2849=CARTESIAN_POINT('',(28.601490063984,15.8825680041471,-1.));
#2850=CARTESIAN_POINT('',(28.7002286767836,15.8376507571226,-1.));
#2851=CARTESIAN_POINT('',(28.8022331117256,15.7991969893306,-1.));
#2852=CARTESIAN_POINT('',(28.9070636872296,15.766072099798,-0.999999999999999));
#2853=CARTESIAN_POINT('',(29.0147251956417,15.7388201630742,-1.));
#2854=CARTESIAN_POINT('',(29.1254409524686,15.7175490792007,-1.));
#2855=CARTESIAN_POINT('',(29.2388114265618,15.7033294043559,-1.));
#2856=CARTESIAN_POINT('',(29.3550813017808,15.6935874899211,-1.));
#2857=CARTESIAN_POINT('',(29.4335227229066,15.6926995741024,-1.));
#2858=CARTESIAN_POINT('',(29.4732735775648,15.6922496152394,-1.));
#2859=B_SPLINE_CURVE_WITH_KNOTS('',3,(#2840,#2841,#2842,#2843,#2844,#2845,#2846,#2847,#2848,
#2849,#2850,#2851,#2852,#2853,#2854,#2855,#2856,#2857,#2858),.UNSPECIFIED.,.F.,.F.,(4,1,1,1,1,1,
1,1,1,1,1,1,1,1,1,1,4),(0.,0.061674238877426,0.123053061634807,0.183475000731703,
0.243726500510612,0.304278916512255,0.364862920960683,0.42594620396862,0.487391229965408,
0.549220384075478,0.611143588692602,0.673528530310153,0.736961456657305,0.80078528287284,
0.866012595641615,0.932100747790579,1.),.UNSPECIFIED.);
#2860=DIRECTION('',(0.,0.,-1.));
#2861=VECTOR('',#2860,1.);
#2862=SURFACE_OF_LINEAR_EXTRUSION('',#2859,#2861);
#2863=ORIENTED_EDGE('',*,*,#792,.F.);
#2864=ORIENTED_EDGE('',*,*,#2835,.F.);
#2865=CARTESIAN_POINT('',(29.4732735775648,15.6922496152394,-1.));
#2866=VERTEX_POINT('',#2865);
#2867=EDGE_CURVE('E1378',#2828,#2866,#2859,.T.);
#2868=ORIENTED_EDGE('',*,*,#2867,.T.);
#2869=DIRECTION('',(0.,0.,-1.));
#2870=VECTOR('',#2869,1.);
#2871=CARTESIAN_POINT('',(29.4732735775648,15.6922496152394,-1.));
#2872=LINE('',#2871,#2870);
#2873=EDGE_CURVE('E1472',#2866,#791,#2872,.T.);
#2874=ORIENTED_EDGE('',*,*,#2873,.T.);
#2875=EDGE_LOOP('',(#2863,#2864,#2868,#2874));
#2876=FACE_BOUND('',#2875,.T.);
#2877=ADVANCED_FACE('F1392',(#2876),#2862,.T.);
#2878=CARTESIAN_POINT('',(29.4732735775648,15.6922496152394,-1.));
#2879=CARTESIAN_POINT('',(29.5109172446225,15.6925116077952,-1.));
#2880=CARTESIAN_POINT('',(29.5853529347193,15.6930296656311,-1.));
#2881=CARTESIAN_POINT('',(29.6952516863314,15.7014218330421,-1.));
#2882=CARTESIAN_POINT('',(29.802241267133,15.712871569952,-1.));
#2883=CARTESIAN_POINT('',(29.9060158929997,15.730111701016,-1.));
#2884=CARTESIAN_POINT('',(30.0071418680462,15.7504560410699,-1.));
#2885=CARTESIAN_POINT('',(30.104702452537,15.7777272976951,-1.));
#2886=CARTESIAN_POINT('',(30.1996576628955,15.8082764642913,-1.));
#2887=CARTESIAN_POINT('',(30.2916260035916,15.844181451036,-1.));
#2888=CARTESIAN_POINT('',(30.3806857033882,15.8846976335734,-0.999999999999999));
#2889=CARTESIAN_POINT('',(30.4665495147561,15.9304891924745,-1.));
#2890=CARTESIAN_POINT('',(30.5491779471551,15.9811710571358,-1.));
#2891=CARTESIAN_POINT('',(30.6293833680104,16.0356260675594,-1.));
#2892=CARTESIAN_POINT('',(30.7059809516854,16.0956033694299,-0.999999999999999));
#2893=CARTESIAN_POINT('',(30.7796344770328,16.1602700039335,-1.));
#2894=CARTESIAN_POINT('',(30.8507569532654,16.2294080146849,-0.999999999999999));
#2895=CARTESIAN_POINT('',(30.8947596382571,16.2792628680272,-1.));
#2896=CARTESIAN_POINT('',(30.9168833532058,16.3043289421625,-1.));
#2897=B_SPLINE_CURVE_WITH_KNOTS('',3,(#2878,#2879,#2880,#2881,#2882,#2883,#2884,#2885,#2886,
#2887,#2888,#2889,#2890,#2891,#2892,#2893,#2894,#2895,#2896),.UNSPECIFIED.,.F.,.F.,(4,1,1,1,1,1,
1,1,1,1,1,1,1,1,1,1,4),(0.,0.0696628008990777,0.137749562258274,0.203916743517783,
0.268779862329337,0.332413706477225,0.394753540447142,0.45618003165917,0.516995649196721,
0.577395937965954,0.637198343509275,0.696999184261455,0.75675619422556,0.816553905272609,
0.876947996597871,0.938131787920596,1.),.UNSPECIFIED.);
#2898=DIRECTION('',(0.,0.,-1.));
#2899=VECTOR('',#2898,1.);
#2900=SURFACE_OF_LINEAR_EXTRUSION('',#2897,#2899);
#2901=ORIENTED_EDGE('',*,*,#816,.F.);
#2902=ORIENTED_EDGE('',*,*,#2873,.F.);
#2903=CARTESIAN_POINT('',(30.9168833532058,16.3043289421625,-1.));
#2904=VERTEX_POINT('',#2903);
#2905=EDGE_CURVE('E1383',#2866,#2904,#2897,.T.);
#2906=ORIENTED_EDGE('',*,*,#2905,.T.);
#2907=DIRECTION('',(0.,0.,-1.));
#2908=VECTOR('',#2907,1.);
#2909=CARTESIAN_POINT('',(30.9168833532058,16.3043289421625,-1.));
#2910=LINE('',#2909,#2908);
#2911=EDGE_CURVE('E1470',#2904,#815,#2910,.T.);
#2912=ORIENTED_EDGE('',*,*,#2911,.T.);
#2913=EDGE_LOOP('',(#2901,#2902,#2906,#2912));
#2914=FACE_BOUND('',#2913,.T.);
#2915=ADVANCED_FACE('F1395',(#2914),#2900,.T.);
#2916=CARTESIAN_POINT('',(30.9168833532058,16.3043289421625,-1.));
#2917=CARTESIAN_POINT('',(30.9523189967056,16.3478701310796,-1.));
#2918=CARTESIAN_POINT('',(31.0227624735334,16.4344268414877,-0.999999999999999));
#2919=CARTESIAN_POINT('',(31.1128881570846,16.5747128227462,-1.));
#2920=CARTESIAN_POINT('',(31.1900357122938,16.721181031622,-1.));
#2921=CARTESIAN_POINT('',(31.252411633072,16.8746009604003,-1.));
#2922=CARTESIAN_POINT('',(31.3011743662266,17.0346283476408,-1.));
#2923=CARTESIAN_POINT('',(31.3349555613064,17.2013438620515,-1.));
#2924=CARTESIAN_POINT('',(31.3569071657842,17.3745918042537,-1.));
#2925=CARTESIAN_POINT('',(31.3594174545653,17.4924285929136,-1.));
#2926=CARTESIAN_POINT('',(31.3606934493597,17.5523257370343,-1.));
#2927=B_SPLINE_CURVE_WITH_KNOTS('',3,(#2916,#2917,#2918,#2919,#2920,#2921,#2922,#2923,#2924,
#2925,#2926),.UNSPECIFIED.,.F.,.F.,(4,1,1,1,1,1,1,1,4),(0.,0.12432850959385,0.247156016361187,
0.368779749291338,0.490733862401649,0.613613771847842,0.738957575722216,0.867310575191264,1.),.UNSPECIFIED.);
#2928=DIRECTION('',(0.,0.,-1.));
#2929=VECTOR('',#2928,1.);
#2930=SURFACE_OF_LINEAR_EXTRUSION('',#2927,#2929);
#2931=ORIENTED_EDGE('',*,*,#830,.F.);
#2932=ORIENTED_EDGE('',*,*,#2911,.F.);
#2933=CARTESIAN_POINT('',(31.3606934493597,17.5523257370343,-1.));
#2934=VERTEX_POINT('',#2933);
#2935=EDGE_CURVE('E1507',#2904,#2934,#2927,.T.);
#2936=ORIENTED_EDGE('',*,*,#2935,.T.);
#2937=DIRECTION('',(0.,0.,-1.));
#2938=VECTOR('',#2937,1.);
#2939=CARTESIAN_POINT('',(31.3606934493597,17.5523257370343,-1.));
#2940=LINE('',#2939,#2938);
#2941=EDGE_CURVE('E1467',#2934,#633,#2940,.T.);
#2942=ORIENTED_EDGE('',*,*,#2941,.T.);
#2943=EDGE_LOOP('',(#2931,#2932,#2936,#2942));
#2944=FACE_BOUND('',#2943,.T.);
#2945=ADVANCED_FACE('F1518',(#2944),#2930,.T.);
#2946=CARTESIAN_POINT('',(31.3606934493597,17.5523257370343,-1.));
#2947=CARTESIAN_POINT('',(31.3591382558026,17.6152811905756,-1.));
#2948=CARTESIAN_POINT('',(31.3560785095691,17.7391421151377,-1.));
#2949=CARTESIAN_POINT('',(31.3300827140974,17.9209160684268,-1.));
#2950=CARTESIAN_POINT('',(31.2882639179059,18.0950674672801,-1.));
#2951=CARTESIAN_POINT('',(31.2288670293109,18.261271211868,-1.));
#2952=CARTESIAN_POINT('',(31.1535616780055,18.4204014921,-1.));
#2953=CARTESIAN_POINT('',(31.060535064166,18.5712426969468,-1.));
#2954=CARTESIAN_POINT('',(30.9508679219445,18.7147594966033,-0.999999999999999));
#2955=CARTESIAN_POINT('',(30.8254203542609,18.8487742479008,-1.));
#2956=CARTESIAN_POINT('',(30.6878530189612,18.9713136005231,-1.));
#2957=CARTESIAN_POINT('',(30.5405342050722,19.0791198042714,-1.));
#2958=CARTESIAN_POINT('',(30.3837522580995,19.1688373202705,-1.));
#2959=CARTESIAN_POINT('',(30.219234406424,19.2438334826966,-1.));
#2960=CARTESIAN_POINT('',(30.0457487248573,19.3014779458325,-1.));
#2961=CARTESIAN_POINT('',(29.8636653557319,19.3418311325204,-1.));
#2962=CARTESIAN_POINT('',(29.6733264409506,19.3669482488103,-1.));
#2963=CARTESIAN_POINT('',(29.5434640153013,19.3701234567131,-1.));
#2964=CARTESIAN_POINT('',(29.477480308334,19.3717367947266,-1.));
#2965=B_SPLINE_CURVE_WITH_KNOTS('',3,(#2946,#2947,#2948,#2949,#2950,#2951,#2952,#2953,#2954,
#2955,#2956,#2957,#2958,#2959,#2960,#2961,#2962,#2963,#2964),.UNSPECIFIED.,.F.,.F.,(4,1,1,1,1,1,
1,1,1,1,1,1,1,1,1,1,4),(0.,0.0645578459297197,0.127013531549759,0.18795481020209,
0.248013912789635,0.307747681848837,0.368234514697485,0.42946984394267,0.492743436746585,
0.556257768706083,0.618216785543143,0.679655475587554,0.74124554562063,0.803415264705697,
0.866815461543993,0.932328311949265,1.),.UNSPECIFIED.);
#2966=DIRECTION('',(0.,0.,-1.));
#2967=VECTOR('',#2966,1.);
#2968=SURFACE_OF_LINEAR_EXTRUSION('',#2965,#2967);
#2969=ORIENTED_EDGE('',*,*,#636,.F.);
#2970=ORIENTED_EDGE('',*,*,#2941,.F.);
#2971=EDGE_CURVE('E1468',#2934,#2628,#2965,.T.);
#2972=ORIENTED_EDGE('',*,*,#2971,.T.);
#2973=ORIENTED_EDGE('',*,*,#2629,.T.);
#2974=EDGE_LOOP('',(#2969,#2970,#2972,#2973));
#2975=FACE_BOUND('',#2974,.T.);
#2976=ADVANCED_FACE('F1515',(#2975),#2968,.T.);
#2977=CARTESIAN_POINT('',(28.6233707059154,19.1919192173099,-1.));
#2978=DIRECTION('',(0.,0.,-1.));
#2979=DIRECTION('',(0.,1.,0.));
#2980=AXIS2_PLACEMENT_3D('',#2977,#2978,#2979);
#2981=PLANE('',#2980);
#2982=ORIENTED_EDGE('',*,*,#2633,.F.);
#2983=ORIENTED_EDGE('',*,*,#2971,.F.);
#2984=ORIENTED_EDGE('',*,*,#2935,.F.);
#2985=ORIENTED_EDGE('',*,*,#2905,.F.);
#2986=ORIENTED_EDGE('',*,*,#2867,.F.);
#2987=ORIENTED_EDGE('',*,*,#2829,.F.);
#2988=ORIENTED_EDGE('',*,*,#2805,.F.);
#2989=ORIENTED_EDGE('',*,*,#2775,.F.);
#2990=ORIENTED_EDGE('',*,*,#2737,.F.);
#2991=ORIENTED_EDGE('',*,*,#2691,.F.);
#2992=ORIENTED_EDGE('',*,*,#2657,.F.);
#2993=EDGE_LOOP('',(#2982,#2983,#2984,#2985,#2986,#2987,#2988,#2989,#2990,#2991,#2992));
#2994=FACE_BOUND('',#2993,.T.);
#2995=ADVANCED_FACE('F415',(#2994),#2981,.T.);
#2996=CLOSED_SHELL('',(#834,#865,#896,#927,#958,#1112,#1124,#1136,#1148,#1160,#1180,#1200,#1280,
#1292,#1304,#1316,#1338,#1355,#1372,#1389,#1406,#1423,#1440,#1452,#1483,#1507,#1531,#1555,#1581,
#1619,#1665,#1703,#1727,#1761,#1799,#1837,#1867,#1884,#1906,#1937,#1961,#1985,#2009,#2047,#2081,
#2115,#2142,#2256,#2301,#2339,#2377,#2408,#2415,#2446,#2470,#2494,#2518,#2542,#2566,#2583,#2598,
#2643,#2667,#2701,#2747,#2785,#2815,#2839,#2877,#2915,#2945,#2976,#2995));
#2997=MANIFOLD_SOLID_BREP('B2',#2996);
#2998=ADVANCED_BREP_SHAPE_REPRESENTATION('',(#18,#2997),#14);
#2999=SHAPE_DEFINITION_REPRESENTATION(#9,#2998);
ENDSEC;
END-ISO-10303-21;
